VERSION 5.8 ;
BUSBITCHARS "[]" ;
DIVIDERCHAR "/" ;
UNITS
    DATABASE MICRONS 1000 ;
END UNITS

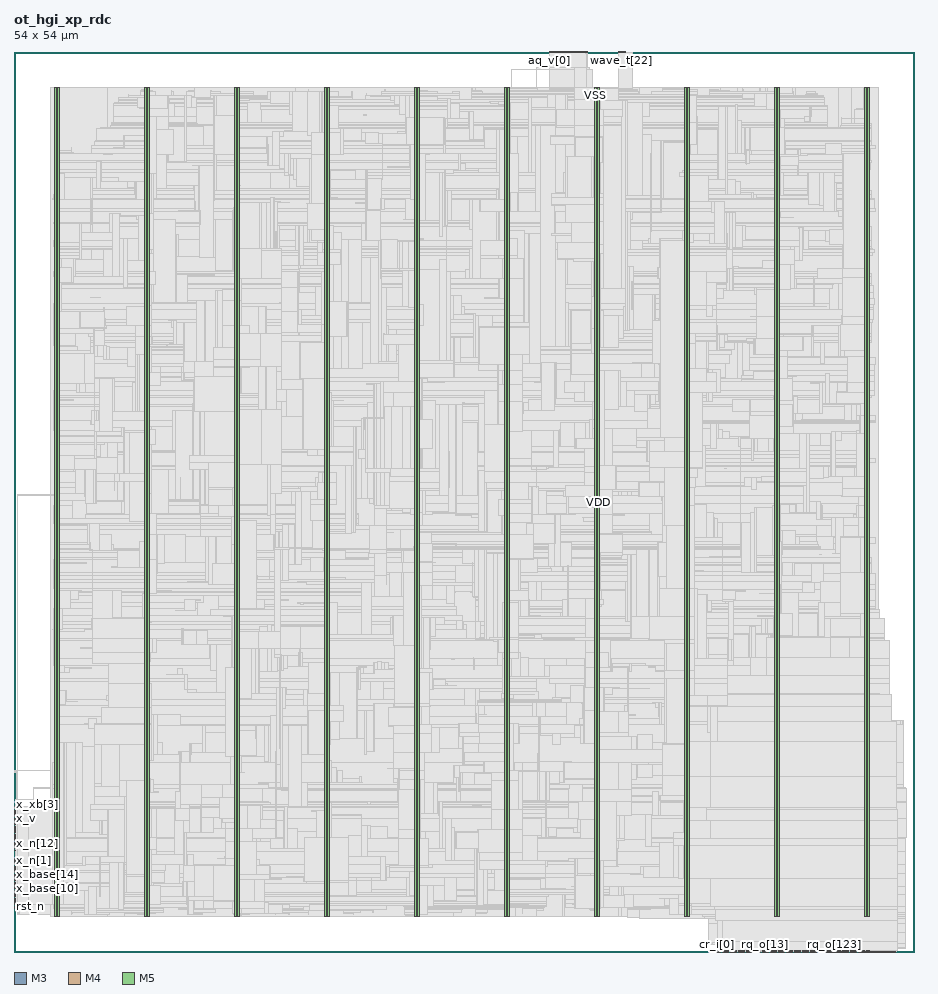
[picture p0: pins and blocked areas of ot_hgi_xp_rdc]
MACRO ot_hgi_xp_rdc
  FOREIGN ot_hgi_xp_rdc 0 0 ;
  CLASS BLOCK ;
  SIZE 54 BY 54 ;
  PIN aq_v[0]
    DIRECTION OUTPUT ;
    USE SIGNAL ;
    PORT
      LAYER M3 ;
        RECT  32.148 53.963 32.166 54 ;
    END
  END aq_v[0]
  PIN aq_v[1]
    DIRECTION OUTPUT ;
    USE SIGNAL ;
    PORT
      LAYER M3 ;
        RECT  32.22 53.963 32.238 54 ;
    END
  END aq_v[1]
  PIN bd_v
    DIRECTION OUTPUT ;
    USE SIGNAL ;
    PORT
      LAYER M3 ;
        RECT  32.292 53.963 32.31 54 ;
    END
  END bd_v
  PIN bf_v
    DIRECTION OUTPUT ;
    USE SIGNAL ;
    PORT
      LAYER M3 ;
        RECT  32.364 53.963 32.382 54 ;
    END
  END bf_v
  PIN clk
    DIRECTION INPUT ;
    USE SIGNAL ;
    PORT
      LAYER M4 ;
        RECT  0 2.64 0.084 2.664 ;
    END
  END clk
  PIN cr_i[0]
    DIRECTION INPUT ;
    USE SIGNAL ;
    PORT
      LAYER M5 ;
        RECT  42.192 0 42.216 0.084 ;
    END
  END cr_i[0]
  PIN cr_i[1]
    DIRECTION INPUT ;
    USE SIGNAL ;
    PORT
      LAYER M5 ;
        RECT  42.288 0 42.312 0.084 ;
    END
  END cr_i[1]
  PIN cr_i[2]
    DIRECTION INPUT ;
    USE SIGNAL ;
    PORT
      LAYER M5 ;
        RECT  42.384 0 42.408 0.084 ;
    END
  END cr_i[2]
  PIN cr_i[3]
    DIRECTION INPUT ;
    USE SIGNAL ;
    PORT
      LAYER M5 ;
        RECT  42.48 0 42.504 0.084 ;
    END
  END cr_i[3]
  PIN cr_i[4]
    DIRECTION INPUT ;
    USE SIGNAL ;
    PORT
      LAYER M5 ;
        RECT  42.576 0 42.6 0.084 ;
    END
  END cr_i[4]
  PIN cr_i[5]
    DIRECTION INPUT ;
    USE SIGNAL ;
    PORT
      LAYER M5 ;
        RECT  42.672 0 42.696 0.084 ;
    END
  END cr_i[5]
  PIN cr_i[6]
    DIRECTION INPUT ;
    USE SIGNAL ;
    PORT
      LAYER M5 ;
        RECT  42.768 0 42.792 0.084 ;
    END
  END cr_i[6]
  PIN cr_i[7]
    DIRECTION INPUT ;
    USE SIGNAL ;
    PORT
      LAYER M5 ;
        RECT  42.864 0 42.888 0.084 ;
    END
  END cr_i[7]
  PIN fault_i[0]
    DIRECTION INPUT ;
    USE SIGNAL ;
    PORT
      LAYER M3 ;
        RECT  32.436 53.963 32.454 54 ;
    END
  END fault_i[0]
  PIN fault_i[1]
    DIRECTION INPUT ;
    USE SIGNAL ;
    PORT
      LAYER M3 ;
        RECT  32.508 53.963 32.526 54 ;
    END
  END fault_i[1]
  PIN fault_i[2]
    DIRECTION INPUT ;
    USE SIGNAL ;
    PORT
      LAYER M3 ;
        RECT  32.58 53.963 32.598 54 ;
    END
  END fault_i[2]
  PIN fault_i[3]
    DIRECTION INPUT ;
    USE SIGNAL ;
    PORT
      LAYER M3 ;
        RECT  32.652 53.963 32.67 54 ;
    END
  END fault_i[3]
  PIN fault_i[4]
    DIRECTION INPUT ;
    USE SIGNAL ;
    PORT
      LAYER M3 ;
        RECT  32.724 53.963 32.742 54 ;
    END
  END fault_i[4]
  PIN fault_i[5]
    DIRECTION INPUT ;
    USE SIGNAL ;
    PORT
      LAYER M3 ;
        RECT  32.796 53.963 32.814 54 ;
    END
  END fault_i[5]
  PIN fault_i[6]
    DIRECTION INPUT ;
    USE SIGNAL ;
    PORT
      LAYER M3 ;
        RECT  32.868 53.963 32.886 54 ;
    END
  END fault_i[6]
  PIN fault_i[7]
    DIRECTION INPUT ;
    USE SIGNAL ;
    PORT
      LAYER M3 ;
        RECT  32.94 53.963 32.958 54 ;
    END
  END fault_i[7]
  PIN fault_i[8]
    DIRECTION INPUT ;
    USE SIGNAL ;
    PORT
      LAYER M3 ;
        RECT  33.012 53.963 33.03 54 ;
    END
  END fault_i[8]
  PIN lpop_o[0]
    DIRECTION OUTPUT ;
    USE SIGNAL ;
    PORT
      LAYER M5 ;
        RECT  42.96 0 42.984 0.084 ;
    END
  END lpop_o[0]
  PIN lpop_o[1]
    DIRECTION OUTPUT ;
    USE SIGNAL ;
    PORT
      LAYER M5 ;
        RECT  43.056 0 43.08 0.084 ;
    END
  END lpop_o[1]
  PIN lpop_o[2]
    DIRECTION OUTPUT ;
    USE SIGNAL ;
    PORT
      LAYER M5 ;
        RECT  43.152 0 43.176 0.084 ;
    END
  END lpop_o[2]
  PIN lpop_o[3]
    DIRECTION OUTPUT ;
    USE SIGNAL ;
    PORT
      LAYER M5 ;
        RECT  43.248 0 43.272 0.084 ;
    END
  END lpop_o[3]
  PIN lpop_o[4]
    DIRECTION OUTPUT ;
    USE SIGNAL ;
    PORT
      LAYER M5 ;
        RECT  43.344 0 43.368 0.084 ;
    END
  END lpop_o[4]
  PIN lpop_o[5]
    DIRECTION OUTPUT ;
    USE SIGNAL ;
    PORT
      LAYER M5 ;
        RECT  43.44 0 43.464 0.084 ;
    END
  END lpop_o[5]
  PIN lpop_o[6]
    DIRECTION OUTPUT ;
    USE SIGNAL ;
    PORT
      LAYER M5 ;
        RECT  43.536 0 43.56 0.084 ;
    END
  END lpop_o[6]
  PIN lpop_o[7]
    DIRECTION OUTPUT ;
    USE SIGNAL ;
    PORT
      LAYER M5 ;
        RECT  43.632 0 43.656 0.084 ;
    END
  END lpop_o[7]
  PIN pop_o
    DIRECTION OUTPUT ;
    USE SIGNAL ;
    PORT
      LAYER M5 ;
        RECT  43.728 0 43.752 0.084 ;
    END
  END pop_o
  PIN rq_o[0]
    DIRECTION OUTPUT ;
    USE SIGNAL ;
    PORT
      LAYER M5 ;
        RECT  43.824 0 43.848 0.084 ;
    END
  END rq_o[0]
  PIN rq_o[100]
    DIRECTION OUTPUT ;
    USE SIGNAL ;
    PORT
      LAYER M3 ;
        RECT  52.164 0 52.182 0.037 ;
    END
  END rq_o[100]
  PIN rq_o[101]
    DIRECTION OUTPUT ;
    USE SIGNAL ;
    PORT
      LAYER M3 ;
        RECT  52.236 0 52.254 0.037 ;
    END
  END rq_o[101]
  PIN rq_o[102]
    DIRECTION OUTPUT ;
    USE SIGNAL ;
    PORT
      LAYER M3 ;
        RECT  52.308 0 52.326 0.037 ;
    END
  END rq_o[102]
  PIN rq_o[103]
    DIRECTION OUTPUT ;
    USE SIGNAL ;
    PORT
      LAYER M3 ;
        RECT  52.38 0 52.398 0.037 ;
    END
  END rq_o[103]
  PIN rq_o[104]
    DIRECTION OUTPUT ;
    USE SIGNAL ;
    PORT
      LAYER M3 ;
        RECT  52.452 0 52.47 0.037 ;
    END
  END rq_o[104]
  PIN rq_o[105]
    DIRECTION OUTPUT ;
    USE SIGNAL ;
    PORT
      LAYER M3 ;
        RECT  52.524 0 52.542 0.037 ;
    END
  END rq_o[105]
  PIN rq_o[106]
    DIRECTION OUTPUT ;
    USE SIGNAL ;
    PORT
      LAYER M3 ;
        RECT  52.596 0 52.614 0.037 ;
    END
  END rq_o[106]
  PIN rq_o[107]
    DIRECTION OUTPUT ;
    USE SIGNAL ;
    PORT
      LAYER M3 ;
        RECT  52.668 0 52.686 0.037 ;
    END
  END rq_o[107]
  PIN rq_o[108]
    DIRECTION OUTPUT ;
    USE SIGNAL ;
    PORT
      LAYER M3 ;
        RECT  52.74 0 52.758 0.037 ;
    END
  END rq_o[108]
  PIN rq_o[109]
    DIRECTION OUTPUT ;
    USE SIGNAL ;
    PORT
      LAYER M3 ;
        RECT  52.812 0 52.83 0.037 ;
    END
  END rq_o[109]
  PIN rq_o[10]
    DIRECTION OUTPUT ;
    USE SIGNAL ;
    PORT
      LAYER M5 ;
        RECT  44.784 0 44.808 0.084 ;
    END
  END rq_o[10]
  PIN rq_o[110]
    DIRECTION OUTPUT ;
    USE SIGNAL ;
    PORT
      LAYER M3 ;
        RECT  52.884 0 52.902 0.037 ;
    END
  END rq_o[110]
  PIN rq_o[111]
    DIRECTION OUTPUT ;
    USE SIGNAL ;
    PORT
      LAYER M3 ;
        RECT  48.348 0 48.366 0.037 ;
    END
  END rq_o[111]
  PIN rq_o[112]
    DIRECTION OUTPUT ;
    USE SIGNAL ;
    PORT
      LAYER M3 ;
        RECT  48.42 0 48.438 0.037 ;
    END
  END rq_o[112]
  PIN rq_o[113]
    DIRECTION OUTPUT ;
    USE SIGNAL ;
    PORT
      LAYER M3 ;
        RECT  48.492 0 48.51 0.037 ;
    END
  END rq_o[113]
  PIN rq_o[114]
    DIRECTION OUTPUT ;
    USE SIGNAL ;
    PORT
      LAYER M3 ;
        RECT  48.564 0 48.582 0.037 ;
    END
  END rq_o[114]
  PIN rq_o[115]
    DIRECTION OUTPUT ;
    USE SIGNAL ;
    PORT
      LAYER M3 ;
        RECT  48.636 0 48.654 0.037 ;
    END
  END rq_o[115]
  PIN rq_o[116]
    DIRECTION OUTPUT ;
    USE SIGNAL ;
    PORT
      LAYER M3 ;
        RECT  48.708 0 48.726 0.037 ;
    END
  END rq_o[116]
  PIN rq_o[117]
    DIRECTION OUTPUT ;
    USE SIGNAL ;
    PORT
      LAYER M3 ;
        RECT  48.78 0 48.798 0.037 ;
    END
  END rq_o[117]
  PIN rq_o[118]
    DIRECTION OUTPUT ;
    USE SIGNAL ;
    PORT
      LAYER M3 ;
        RECT  48.852 0 48.87 0.037 ;
    END
  END rq_o[118]
  PIN rq_o[119]
    DIRECTION OUTPUT ;
    USE SIGNAL ;
    PORT
      LAYER M3 ;
        RECT  48.924 0 48.942 0.037 ;
    END
  END rq_o[119]
  PIN rq_o[11]
    DIRECTION OUTPUT ;
    USE SIGNAL ;
    PORT
      LAYER M5 ;
        RECT  44.88 0 44.904 0.084 ;
    END
  END rq_o[11]
  PIN rq_o[120]
    DIRECTION OUTPUT ;
    USE SIGNAL ;
    PORT
      LAYER M3 ;
        RECT  48.996 0 49.014 0.037 ;
    END
  END rq_o[120]
  PIN rq_o[121]
    DIRECTION OUTPUT ;
    USE SIGNAL ;
    PORT
      LAYER M3 ;
        RECT  49.068 0 49.086 0.037 ;
    END
  END rq_o[121]
  PIN rq_o[122]
    DIRECTION OUTPUT ;
    USE SIGNAL ;
    PORT
      LAYER M3 ;
        RECT  49.14 0 49.158 0.037 ;
    END
  END rq_o[122]
  PIN rq_o[123]
    DIRECTION OUTPUT ;
    USE SIGNAL ;
    PORT
      LAYER M3 ;
        RECT  49.212 0 49.23 0.037 ;
    END
  END rq_o[123]
  PIN rq_o[124]
    DIRECTION OUTPUT ;
    USE SIGNAL ;
    PORT
      LAYER M3 ;
        RECT  49.284 0 49.302 0.037 ;
    END
  END rq_o[124]
  PIN rq_o[125]
    DIRECTION OUTPUT ;
    USE SIGNAL ;
    PORT
      LAYER M3 ;
        RECT  49.356 0 49.374 0.037 ;
    END
  END rq_o[125]
  PIN rq_o[126]
    DIRECTION OUTPUT ;
    USE SIGNAL ;
    PORT
      LAYER M3 ;
        RECT  49.428 0 49.446 0.037 ;
    END
  END rq_o[126]
  PIN rq_o[127]
    DIRECTION OUTPUT ;
    USE SIGNAL ;
    PORT
      LAYER M3 ;
        RECT  49.5 0 49.518 0.037 ;
    END
  END rq_o[127]
  PIN rq_o[12]
    DIRECTION OUTPUT ;
    USE SIGNAL ;
    PORT
      LAYER M5 ;
        RECT  44.976 0 45 0.084 ;
    END
  END rq_o[12]
  PIN rq_o[13]
    DIRECTION OUTPUT ;
    USE SIGNAL ;
    PORT
      LAYER M5 ;
        RECT  45.072 0 45.096 0.084 ;
    END
  END rq_o[13]
  PIN rq_o[14]
    DIRECTION OUTPUT ;
    USE SIGNAL ;
    PORT
      LAYER M5 ;
        RECT  45.168 0 45.192 0.084 ;
    END
  END rq_o[14]
  PIN rq_o[15]
    DIRECTION OUTPUT ;
    USE SIGNAL ;
    PORT
      LAYER M5 ;
        RECT  45.264 0 45.288 0.084 ;
    END
  END rq_o[15]
  PIN rq_o[16]
    DIRECTION OUTPUT ;
    USE SIGNAL ;
    PORT
      LAYER M5 ;
        RECT  45.36 0 45.384 0.084 ;
    END
  END rq_o[16]
  PIN rq_o[17]
    DIRECTION OUTPUT ;
    USE SIGNAL ;
    PORT
      LAYER M5 ;
        RECT  45.456 0 45.48 0.084 ;
    END
  END rq_o[17]
  PIN rq_o[18]
    DIRECTION OUTPUT ;
    USE SIGNAL ;
    PORT
      LAYER M5 ;
        RECT  45.552 0 45.576 0.084 ;
    END
  END rq_o[18]
  PIN rq_o[19]
    DIRECTION OUTPUT ;
    USE SIGNAL ;
    PORT
      LAYER M5 ;
        RECT  45.648 0 45.672 0.084 ;
    END
  END rq_o[19]
  PIN rq_o[1]
    DIRECTION OUTPUT ;
    USE SIGNAL ;
    PORT
      LAYER M5 ;
        RECT  43.92 0 43.944 0.084 ;
    END
  END rq_o[1]
  PIN rq_o[20]
    DIRECTION OUTPUT ;
    USE SIGNAL ;
    PORT
      LAYER M5 ;
        RECT  45.744 0 45.768 0.084 ;
    END
  END rq_o[20]
  PIN rq_o[21]
    DIRECTION OUTPUT ;
    USE SIGNAL ;
    PORT
      LAYER M5 ;
        RECT  45.84 0 45.864 0.084 ;
    END
  END rq_o[21]
  PIN rq_o[22]
    DIRECTION OUTPUT ;
    USE SIGNAL ;
    PORT
      LAYER M5 ;
        RECT  45.936 0 45.96 0.084 ;
    END
  END rq_o[22]
  PIN rq_o[23]
    DIRECTION OUTPUT ;
    USE SIGNAL ;
    PORT
      LAYER M5 ;
        RECT  46.032 0 46.056 0.084 ;
    END
  END rq_o[23]
  PIN rq_o[24]
    DIRECTION OUTPUT ;
    USE SIGNAL ;
    PORT
      LAYER M5 ;
        RECT  46.128 0 46.152 0.084 ;
    END
  END rq_o[24]
  PIN rq_o[25]
    DIRECTION OUTPUT ;
    USE SIGNAL ;
    PORT
      LAYER M5 ;
        RECT  46.224 0 46.248 0.084 ;
    END
  END rq_o[25]
  PIN rq_o[26]
    DIRECTION OUTPUT ;
    USE SIGNAL ;
    PORT
      LAYER M5 ;
        RECT  46.32 0 46.344 0.084 ;
    END
  END rq_o[26]
  PIN rq_o[27]
    DIRECTION OUTPUT ;
    USE SIGNAL ;
    PORT
      LAYER M5 ;
        RECT  46.416 0 46.44 0.084 ;
    END
  END rq_o[27]
  PIN rq_o[28]
    DIRECTION OUTPUT ;
    USE SIGNAL ;
    PORT
      LAYER M5 ;
        RECT  46.512 0 46.536 0.084 ;
    END
  END rq_o[28]
  PIN rq_o[29]
    DIRECTION OUTPUT ;
    USE SIGNAL ;
    PORT
      LAYER M5 ;
        RECT  46.608 0 46.632 0.084 ;
    END
  END rq_o[29]
  PIN rq_o[2]
    DIRECTION OUTPUT ;
    USE SIGNAL ;
    PORT
      LAYER M5 ;
        RECT  44.016 0 44.04 0.084 ;
    END
  END rq_o[2]
  PIN rq_o[30]
    DIRECTION OUTPUT ;
    USE SIGNAL ;
    PORT
      LAYER M5 ;
        RECT  46.704 0 46.728 0.084 ;
    END
  END rq_o[30]
  PIN rq_o[31]
    DIRECTION OUTPUT ;
    USE SIGNAL ;
    PORT
      LAYER M5 ;
        RECT  46.8 0 46.824 0.084 ;
    END
  END rq_o[31]
  PIN rq_o[32]
    DIRECTION OUTPUT ;
    USE SIGNAL ;
    PORT
      LAYER M5 ;
        RECT  46.896 0 46.92 0.084 ;
    END
  END rq_o[32]
  PIN rq_o[33]
    DIRECTION OUTPUT ;
    USE SIGNAL ;
    PORT
      LAYER M5 ;
        RECT  46.992 0 47.016 0.084 ;
    END
  END rq_o[33]
  PIN rq_o[34]
    DIRECTION OUTPUT ;
    USE SIGNAL ;
    PORT
      LAYER M5 ;
        RECT  47.088 0 47.112 0.084 ;
    END
  END rq_o[34]
  PIN rq_o[35]
    DIRECTION OUTPUT ;
    USE SIGNAL ;
    PORT
      LAYER M5 ;
        RECT  47.184 0 47.208 0.084 ;
    END
  END rq_o[35]
  PIN rq_o[36]
    DIRECTION OUTPUT ;
    USE SIGNAL ;
    PORT
      LAYER M5 ;
        RECT  47.28 0 47.304 0.084 ;
    END
  END rq_o[36]
  PIN rq_o[37]
    DIRECTION OUTPUT ;
    USE SIGNAL ;
    PORT
      LAYER M5 ;
        RECT  47.376 0 47.4 0.084 ;
    END
  END rq_o[37]
  PIN rq_o[38]
    DIRECTION OUTPUT ;
    USE SIGNAL ;
    PORT
      LAYER M5 ;
        RECT  47.472 0 47.496 0.084 ;
    END
  END rq_o[38]
  PIN rq_o[39]
    DIRECTION OUTPUT ;
    USE SIGNAL ;
    PORT
      LAYER M5 ;
        RECT  47.568 0 47.592 0.084 ;
    END
  END rq_o[39]
  PIN rq_o[3]
    DIRECTION OUTPUT ;
    USE SIGNAL ;
    PORT
      LAYER M5 ;
        RECT  44.112 0 44.136 0.084 ;
    END
  END rq_o[3]
  PIN rq_o[40]
    DIRECTION OUTPUT ;
    USE SIGNAL ;
    PORT
      LAYER M5 ;
        RECT  47.664 0 47.688 0.084 ;
    END
  END rq_o[40]
  PIN rq_o[41]
    DIRECTION OUTPUT ;
    USE SIGNAL ;
    PORT
      LAYER M5 ;
        RECT  47.76 0 47.784 0.084 ;
    END
  END rq_o[41]
  PIN rq_o[42]
    DIRECTION OUTPUT ;
    USE SIGNAL ;
    PORT
      LAYER M5 ;
        RECT  47.856 0 47.88 0.084 ;
    END
  END rq_o[42]
  PIN rq_o[43]
    DIRECTION OUTPUT ;
    USE SIGNAL ;
    PORT
      LAYER M5 ;
        RECT  47.952 0 47.976 0.084 ;
    END
  END rq_o[43]
  PIN rq_o[44]
    DIRECTION OUTPUT ;
    USE SIGNAL ;
    PORT
      LAYER M5 ;
        RECT  48.048 0 48.072 0.084 ;
    END
  END rq_o[44]
  PIN rq_o[45]
    DIRECTION OUTPUT ;
    USE SIGNAL ;
    PORT
      LAYER M5 ;
        RECT  48.144 0 48.168 0.084 ;
    END
  END rq_o[45]
  PIN rq_o[46]
    DIRECTION OUTPUT ;
    USE SIGNAL ;
    PORT
      LAYER M5 ;
        RECT  48.24 0 48.264 0.084 ;
    END
  END rq_o[46]
  PIN rq_o[47]
    DIRECTION OUTPUT ;
    USE SIGNAL ;
    PORT
      LAYER M5 ;
        RECT  48.336 0 48.36 0.084 ;
    END
  END rq_o[47]
  PIN rq_o[48]
    DIRECTION OUTPUT ;
    USE SIGNAL ;
    PORT
      LAYER M5 ;
        RECT  48.432 0 48.456 0.084 ;
    END
  END rq_o[48]
  PIN rq_o[49]
    DIRECTION OUTPUT ;
    USE SIGNAL ;
    PORT
      LAYER M5 ;
        RECT  48.528 0 48.552 0.084 ;
    END
  END rq_o[49]
  PIN rq_o[4]
    DIRECTION OUTPUT ;
    USE SIGNAL ;
    PORT
      LAYER M5 ;
        RECT  44.208 0 44.232 0.084 ;
    END
  END rq_o[4]
  PIN rq_o[50]
    DIRECTION OUTPUT ;
    USE SIGNAL ;
    PORT
      LAYER M5 ;
        RECT  48.624 0 48.648 0.084 ;
    END
  END rq_o[50]
  PIN rq_o[51]
    DIRECTION OUTPUT ;
    USE SIGNAL ;
    PORT
      LAYER M5 ;
        RECT  48.72 0 48.744 0.084 ;
    END
  END rq_o[51]
  PIN rq_o[52]
    DIRECTION OUTPUT ;
    USE SIGNAL ;
    PORT
      LAYER M5 ;
        RECT  48.816 0 48.84 0.084 ;
    END
  END rq_o[52]
  PIN rq_o[53]
    DIRECTION OUTPUT ;
    USE SIGNAL ;
    PORT
      LAYER M5 ;
        RECT  48.912 0 48.936 0.084 ;
    END
  END rq_o[53]
  PIN rq_o[54]
    DIRECTION OUTPUT ;
    USE SIGNAL ;
    PORT
      LAYER M5 ;
        RECT  49.008 0 49.032 0.084 ;
    END
  END rq_o[54]
  PIN rq_o[55]
    DIRECTION OUTPUT ;
    USE SIGNAL ;
    PORT
      LAYER M5 ;
        RECT  49.104 0 49.128 0.084 ;
    END
  END rq_o[55]
  PIN rq_o[56]
    DIRECTION OUTPUT ;
    USE SIGNAL ;
    PORT
      LAYER M5 ;
        RECT  49.2 0 49.224 0.084 ;
    END
  END rq_o[56]
  PIN rq_o[57]
    DIRECTION OUTPUT ;
    USE SIGNAL ;
    PORT
      LAYER M5 ;
        RECT  49.296 0 49.32 0.084 ;
    END
  END rq_o[57]
  PIN rq_o[58]
    DIRECTION OUTPUT ;
    USE SIGNAL ;
    PORT
      LAYER M5 ;
        RECT  49.392 0 49.416 0.084 ;
    END
  END rq_o[58]
  PIN rq_o[59]
    DIRECTION OUTPUT ;
    USE SIGNAL ;
    PORT
      LAYER M5 ;
        RECT  49.488 0 49.512 0.084 ;
    END
  END rq_o[59]
  PIN rq_o[5]
    DIRECTION OUTPUT ;
    USE SIGNAL ;
    PORT
      LAYER M5 ;
        RECT  44.304 0 44.328 0.084 ;
    END
  END rq_o[5]
  PIN rq_o[60]
    DIRECTION OUTPUT ;
    USE SIGNAL ;
    PORT
      LAYER M5 ;
        RECT  49.584 0 49.608 0.084 ;
    END
  END rq_o[60]
  PIN rq_o[61]
    DIRECTION OUTPUT ;
    USE SIGNAL ;
    PORT
      LAYER M5 ;
        RECT  49.68 0 49.704 0.084 ;
    END
  END rq_o[61]
  PIN rq_o[62]
    DIRECTION OUTPUT ;
    USE SIGNAL ;
    PORT
      LAYER M5 ;
        RECT  49.776 0 49.8 0.084 ;
    END
  END rq_o[62]
  PIN rq_o[63]
    DIRECTION OUTPUT ;
    USE SIGNAL ;
    PORT
      LAYER M5 ;
        RECT  49.872 0 49.896 0.084 ;
    END
  END rq_o[63]
  PIN rq_o[64]
    DIRECTION OUTPUT ;
    USE SIGNAL ;
    PORT
      LAYER M5 ;
        RECT  49.968 0 49.992 0.084 ;
    END
  END rq_o[64]
  PIN rq_o[65]
    DIRECTION OUTPUT ;
    USE SIGNAL ;
    PORT
      LAYER M5 ;
        RECT  50.064 0 50.088 0.084 ;
    END
  END rq_o[65]
  PIN rq_o[66]
    DIRECTION OUTPUT ;
    USE SIGNAL ;
    PORT
      LAYER M5 ;
        RECT  50.16 0 50.184 0.084 ;
    END
  END rq_o[66]
  PIN rq_o[67]
    DIRECTION OUTPUT ;
    USE SIGNAL ;
    PORT
      LAYER M5 ;
        RECT  50.256 0 50.28 0.084 ;
    END
  END rq_o[67]
  PIN rq_o[68]
    DIRECTION OUTPUT ;
    USE SIGNAL ;
    PORT
      LAYER M5 ;
        RECT  50.352 0 50.376 0.084 ;
    END
  END rq_o[68]
  PIN rq_o[69]
    DIRECTION OUTPUT ;
    USE SIGNAL ;
    PORT
      LAYER M5 ;
        RECT  50.448 0 50.472 0.084 ;
    END
  END rq_o[69]
  PIN rq_o[6]
    DIRECTION OUTPUT ;
    USE SIGNAL ;
    PORT
      LAYER M5 ;
        RECT  44.4 0 44.424 0.084 ;
    END
  END rq_o[6]
  PIN rq_o[70]
    DIRECTION OUTPUT ;
    USE SIGNAL ;
    PORT
      LAYER M5 ;
        RECT  50.544 0 50.568 0.084 ;
    END
  END rq_o[70]
  PIN rq_o[71]
    DIRECTION OUTPUT ;
    USE SIGNAL ;
    PORT
      LAYER M5 ;
        RECT  50.64 0 50.664 0.084 ;
    END
  END rq_o[71]
  PIN rq_o[72]
    DIRECTION OUTPUT ;
    USE SIGNAL ;
    PORT
      LAYER M5 ;
        RECT  50.736 0 50.76 0.084 ;
    END
  END rq_o[72]
  PIN rq_o[73]
    DIRECTION OUTPUT ;
    USE SIGNAL ;
    PORT
      LAYER M5 ;
        RECT  50.832 0 50.856 0.084 ;
    END
  END rq_o[73]
  PIN rq_o[74]
    DIRECTION OUTPUT ;
    USE SIGNAL ;
    PORT
      LAYER M5 ;
        RECT  50.928 0 50.952 0.084 ;
    END
  END rq_o[74]
  PIN rq_o[75]
    DIRECTION OUTPUT ;
    USE SIGNAL ;
    PORT
      LAYER M5 ;
        RECT  51.024 0 51.048 0.084 ;
    END
  END rq_o[75]
  PIN rq_o[76]
    DIRECTION OUTPUT ;
    USE SIGNAL ;
    PORT
      LAYER M5 ;
        RECT  51.12 0 51.144 0.084 ;
    END
  END rq_o[76]
  PIN rq_o[77]
    DIRECTION OUTPUT ;
    USE SIGNAL ;
    PORT
      LAYER M5 ;
        RECT  51.216 0 51.24 0.084 ;
    END
  END rq_o[77]
  PIN rq_o[78]
    DIRECTION OUTPUT ;
    USE SIGNAL ;
    PORT
      LAYER M5 ;
        RECT  51.312 0 51.336 0.084 ;
    END
  END rq_o[78]
  PIN rq_o[79]
    DIRECTION OUTPUT ;
    USE SIGNAL ;
    PORT
      LAYER M3 ;
        RECT  50.652 0 50.67 0.037 ;
    END
  END rq_o[79]
  PIN rq_o[7]
    DIRECTION OUTPUT ;
    USE SIGNAL ;
    PORT
      LAYER M5 ;
        RECT  44.496 0 44.52 0.084 ;
    END
  END rq_o[7]
  PIN rq_o[80]
    DIRECTION OUTPUT ;
    USE SIGNAL ;
    PORT
      LAYER M3 ;
        RECT  50.724 0 50.742 0.037 ;
    END
  END rq_o[80]
  PIN rq_o[81]
    DIRECTION OUTPUT ;
    USE SIGNAL ;
    PORT
      LAYER M3 ;
        RECT  50.796 0 50.814 0.037 ;
    END
  END rq_o[81]
  PIN rq_o[82]
    DIRECTION OUTPUT ;
    USE SIGNAL ;
    PORT
      LAYER M3 ;
        RECT  50.868 0 50.886 0.037 ;
    END
  END rq_o[82]
  PIN rq_o[83]
    DIRECTION OUTPUT ;
    USE SIGNAL ;
    PORT
      LAYER M3 ;
        RECT  50.94 0 50.958 0.037 ;
    END
  END rq_o[83]
  PIN rq_o[84]
    DIRECTION OUTPUT ;
    USE SIGNAL ;
    PORT
      LAYER M3 ;
        RECT  51.012 0 51.03 0.037 ;
    END
  END rq_o[84]
  PIN rq_o[85]
    DIRECTION OUTPUT ;
    USE SIGNAL ;
    PORT
      LAYER M3 ;
        RECT  51.084 0 51.102 0.037 ;
    END
  END rq_o[85]
  PIN rq_o[86]
    DIRECTION OUTPUT ;
    USE SIGNAL ;
    PORT
      LAYER M3 ;
        RECT  51.156 0 51.174 0.037 ;
    END
  END rq_o[86]
  PIN rq_o[87]
    DIRECTION OUTPUT ;
    USE SIGNAL ;
    PORT
      LAYER M3 ;
        RECT  51.228 0 51.246 0.037 ;
    END
  END rq_o[87]
  PIN rq_o[88]
    DIRECTION OUTPUT ;
    USE SIGNAL ;
    PORT
      LAYER M3 ;
        RECT  51.3 0 51.318 0.037 ;
    END
  END rq_o[88]
  PIN rq_o[89]
    DIRECTION OUTPUT ;
    USE SIGNAL ;
    PORT
      LAYER M3 ;
        RECT  51.372 0 51.39 0.037 ;
    END
  END rq_o[89]
  PIN rq_o[8]
    DIRECTION OUTPUT ;
    USE SIGNAL ;
    PORT
      LAYER M5 ;
        RECT  44.592 0 44.616 0.084 ;
    END
  END rq_o[8]
  PIN rq_o[90]
    DIRECTION OUTPUT ;
    USE SIGNAL ;
    PORT
      LAYER M3 ;
        RECT  51.444 0 51.462 0.037 ;
    END
  END rq_o[90]
  PIN rq_o[91]
    DIRECTION OUTPUT ;
    USE SIGNAL ;
    PORT
      LAYER M3 ;
        RECT  51.516 0 51.534 0.037 ;
    END
  END rq_o[91]
  PIN rq_o[92]
    DIRECTION OUTPUT ;
    USE SIGNAL ;
    PORT
      LAYER M3 ;
        RECT  51.588 0 51.606 0.037 ;
    END
  END rq_o[92]
  PIN rq_o[93]
    DIRECTION OUTPUT ;
    USE SIGNAL ;
    PORT
      LAYER M3 ;
        RECT  51.66 0 51.678 0.037 ;
    END
  END rq_o[93]
  PIN rq_o[94]
    DIRECTION OUTPUT ;
    USE SIGNAL ;
    PORT
      LAYER M3 ;
        RECT  51.732 0 51.75 0.037 ;
    END
  END rq_o[94]
  PIN rq_o[95]
    DIRECTION OUTPUT ;
    USE SIGNAL ;
    PORT
      LAYER M3 ;
        RECT  51.804 0 51.822 0.037 ;
    END
  END rq_o[95]
  PIN rq_o[96]
    DIRECTION OUTPUT ;
    USE SIGNAL ;
    PORT
      LAYER M3 ;
        RECT  51.876 0 51.894 0.037 ;
    END
  END rq_o[96]
  PIN rq_o[97]
    DIRECTION OUTPUT ;
    USE SIGNAL ;
    PORT
      LAYER M3 ;
        RECT  51.948 0 51.966 0.037 ;
    END
  END rq_o[97]
  PIN rq_o[98]
    DIRECTION OUTPUT ;
    USE SIGNAL ;
    PORT
      LAYER M3 ;
        RECT  52.02 0 52.038 0.037 ;
    END
  END rq_o[98]
  PIN rq_o[99]
    DIRECTION OUTPUT ;
    USE SIGNAL ;
    PORT
      LAYER M3 ;
        RECT  52.092 0 52.11 0.037 ;
    END
  END rq_o[99]
  PIN rq_o[9]
    DIRECTION OUTPUT ;
    USE SIGNAL ;
    PORT
      LAYER M5 ;
        RECT  44.688 0 44.712 0.084 ;
    END
  END rq_o[9]
  PIN rst_n
    DIRECTION INPUT ;
    USE SIGNAL ;
    PORT
      LAYER M4 ;
        RECT  0 2.736 0.084 2.76 ;
    END
  END rst_n
  PIN rsv_i[0]
    DIRECTION INPUT ;
    USE SIGNAL ;
    PORT
      LAYER M3 ;
        RECT  49.572 0 49.59 0.037 ;
    END
  END rsv_i[0]
  PIN rsv_i[1]
    DIRECTION INPUT ;
    USE SIGNAL ;
    PORT
      LAYER M3 ;
        RECT  49.644 0 49.662 0.037 ;
    END
  END rsv_i[1]
  PIN rsv_i[2]
    DIRECTION INPUT ;
    USE SIGNAL ;
    PORT
      LAYER M3 ;
        RECT  49.716 0 49.734 0.037 ;
    END
  END rsv_i[2]
  PIN rsv_i[3]
    DIRECTION INPUT ;
    USE SIGNAL ;
    PORT
      LAYER M3 ;
        RECT  49.788 0 49.806 0.037 ;
    END
  END rsv_i[3]
  PIN rsv_i[4]
    DIRECTION INPUT ;
    USE SIGNAL ;
    PORT
      LAYER M3 ;
        RECT  49.86 0 49.878 0.037 ;
    END
  END rsv_i[4]
  PIN rsv_i[5]
    DIRECTION INPUT ;
    USE SIGNAL ;
    PORT
      LAYER M3 ;
        RECT  49.932 0 49.95 0.037 ;
    END
  END rsv_i[5]
  PIN rsv_i[6]
    DIRECTION INPUT ;
    USE SIGNAL ;
    PORT
      LAYER M3 ;
        RECT  50.004 0 50.022 0.037 ;
    END
  END rsv_i[6]
  PIN rsv_i[7]
    DIRECTION INPUT ;
    USE SIGNAL ;
    PORT
      LAYER M3 ;
        RECT  50.076 0 50.094 0.037 ;
    END
  END rsv_i[7]
  PIN wave_t[0]
    DIRECTION OUTPUT ;
    USE SIGNAL ;
    PORT
      LAYER M3 ;
        RECT  33.084 53.963 33.102 54 ;
    END
  END wave_t[0]
  PIN wave_t[10]
    DIRECTION OUTPUT ;
    USE SIGNAL ;
    PORT
      LAYER M3 ;
        RECT  33.804 53.963 33.822 54 ;
    END
  END wave_t[10]
  PIN wave_t[11]
    DIRECTION OUTPUT ;
    USE SIGNAL ;
    PORT
      LAYER M3 ;
        RECT  33.876 53.963 33.894 54 ;
    END
  END wave_t[11]
  PIN wave_t[12]
    DIRECTION OUTPUT ;
    USE SIGNAL ;
    PORT
      LAYER M3 ;
        RECT  33.948 53.963 33.966 54 ;
    END
  END wave_t[12]
  PIN wave_t[13]
    DIRECTION OUTPUT ;
    USE SIGNAL ;
    PORT
      LAYER M3 ;
        RECT  34.02 53.963 34.038 54 ;
    END
  END wave_t[13]
  PIN wave_t[14]
    DIRECTION OUTPUT ;
    USE SIGNAL ;
    PORT
      LAYER M3 ;
        RECT  34.092 53.963 34.11 54 ;
    END
  END wave_t[14]
  PIN wave_t[15]
    DIRECTION OUTPUT ;
    USE SIGNAL ;
    PORT
      LAYER M3 ;
        RECT  34.164 53.963 34.182 54 ;
    END
  END wave_t[15]
  PIN wave_t[16]
    DIRECTION OUTPUT ;
    USE SIGNAL ;
    PORT
      LAYER M3 ;
        RECT  34.236 53.963 34.254 54 ;
    END
  END wave_t[16]
  PIN wave_t[17]
    DIRECTION OUTPUT ;
    USE SIGNAL ;
    PORT
      LAYER M3 ;
        RECT  34.308 53.963 34.326 54 ;
    END
  END wave_t[17]
  PIN wave_t[18]
    DIRECTION OUTPUT ;
    USE SIGNAL ;
    PORT
      LAYER M3 ;
        RECT  34.38 53.963 34.398 54 ;
    END
  END wave_t[18]
  PIN wave_t[19]
    DIRECTION OUTPUT ;
    USE SIGNAL ;
    PORT
      LAYER M3 ;
        RECT  36.252 53.963 36.27 54 ;
    END
  END wave_t[19]
  PIN wave_t[1]
    DIRECTION OUTPUT ;
    USE SIGNAL ;
    PORT
      LAYER M3 ;
        RECT  33.156 53.963 33.174 54 ;
    END
  END wave_t[1]
  PIN wave_t[20]
    DIRECTION OUTPUT ;
    USE SIGNAL ;
    PORT
      LAYER M3 ;
        RECT  36.324 53.963 36.342 54 ;
    END
  END wave_t[20]
  PIN wave_t[21]
    DIRECTION OUTPUT ;
    USE SIGNAL ;
    PORT
      LAYER M3 ;
        RECT  36.396 53.963 36.414 54 ;
    END
  END wave_t[21]
  PIN wave_t[22]
    DIRECTION OUTPUT ;
    USE SIGNAL ;
    PORT
      LAYER M3 ;
        RECT  36.468 53.963 36.486 54 ;
    END
  END wave_t[22]
  PIN wave_t[23]
    DIRECTION OUTPUT ;
    USE SIGNAL ;
    PORT
      LAYER M3 ;
        RECT  36.54 53.963 36.558 54 ;
    END
  END wave_t[23]
  PIN wave_t[24]
    DIRECTION OUTPUT ;
    USE SIGNAL ;
    PORT
      LAYER M3 ;
        RECT  36.612 53.963 36.63 54 ;
    END
  END wave_t[24]
  PIN wave_t[2]
    DIRECTION OUTPUT ;
    USE SIGNAL ;
    PORT
      LAYER M3 ;
        RECT  33.228 53.963 33.246 54 ;
    END
  END wave_t[2]
  PIN wave_t[3]
    DIRECTION OUTPUT ;
    USE SIGNAL ;
    PORT
      LAYER M3 ;
        RECT  33.3 53.963 33.318 54 ;
    END
  END wave_t[3]
  PIN wave_t[4]
    DIRECTION OUTPUT ;
    USE SIGNAL ;
    PORT
      LAYER M3 ;
        RECT  33.372 53.963 33.39 54 ;
    END
  END wave_t[4]
  PIN wave_t[5]
    DIRECTION OUTPUT ;
    USE SIGNAL ;
    PORT
      LAYER M3 ;
        RECT  33.444 53.963 33.462 54 ;
    END
  END wave_t[5]
  PIN wave_t[6]
    DIRECTION OUTPUT ;
    USE SIGNAL ;
    PORT
      LAYER M3 ;
        RECT  33.516 53.963 33.534 54 ;
    END
  END wave_t[6]
  PIN wave_t[7]
    DIRECTION OUTPUT ;
    USE SIGNAL ;
    PORT
      LAYER M3 ;
        RECT  33.588 53.963 33.606 54 ;
    END
  END wave_t[7]
  PIN wave_t[8]
    DIRECTION OUTPUT ;
    USE SIGNAL ;
    PORT
      LAYER M3 ;
        RECT  33.66 53.963 33.678 54 ;
    END
  END wave_t[8]
  PIN wave_t[9]
    DIRECTION OUTPUT ;
    USE SIGNAL ;
    PORT
      LAYER M3 ;
        RECT  33.732 53.963 33.75 54 ;
    END
  END wave_t[9]
  PIN x_base[0]
    DIRECTION INPUT ;
    USE SIGNAL ;
    PORT
      LAYER M4 ;
        RECT  0 2.832 0.084 2.856 ;
    END
  END x_base[0]
  PIN x_base[10]
    DIRECTION INPUT ;
    USE SIGNAL ;
    PORT
      LAYER M4 ;
        RECT  0 3.792 0.084 3.816 ;
    END
  END x_base[10]
  PIN x_base[11]
    DIRECTION INPUT ;
    USE SIGNAL ;
    PORT
      LAYER M4 ;
        RECT  0 3.888 0.084 3.912 ;
    END
  END x_base[11]
  PIN x_base[12]
    DIRECTION INPUT ;
    USE SIGNAL ;
    PORT
      LAYER M4 ;
        RECT  0 3.984 0.084 4.008 ;
    END
  END x_base[12]
  PIN x_base[13]
    DIRECTION INPUT ;
    USE SIGNAL ;
    PORT
      LAYER M4 ;
        RECT  0 4.08 0.084 4.104 ;
    END
  END x_base[13]
  PIN x_base[14]
    DIRECTION INPUT ;
    USE SIGNAL ;
    PORT
      LAYER M4 ;
        RECT  0 4.176 0.084 4.2 ;
    END
  END x_base[14]
  PIN x_base[15]
    DIRECTION INPUT ;
    USE SIGNAL ;
    PORT
      LAYER M4 ;
        RECT  0 4.272 0.084 4.296 ;
    END
  END x_base[15]
  PIN x_base[16]
    DIRECTION INPUT ;
    USE SIGNAL ;
    PORT
      LAYER M4 ;
        RECT  0 4.368 0.084 4.392 ;
    END
  END x_base[16]
  PIN x_base[17]
    DIRECTION INPUT ;
    USE SIGNAL ;
    PORT
      LAYER M4 ;
        RECT  0 4.464 0.084 4.488 ;
    END
  END x_base[17]
  PIN x_base[1]
    DIRECTION INPUT ;
    USE SIGNAL ;
    PORT
      LAYER M4 ;
        RECT  0 2.928 0.084 2.952 ;
    END
  END x_base[1]
  PIN x_base[2]
    DIRECTION INPUT ;
    USE SIGNAL ;
    PORT
      LAYER M4 ;
        RECT  0 3.024 0.084 3.048 ;
    END
  END x_base[2]
  PIN x_base[3]
    DIRECTION INPUT ;
    USE SIGNAL ;
    PORT
      LAYER M4 ;
        RECT  0 3.12 0.084 3.144 ;
    END
  END x_base[3]
  PIN x_base[4]
    DIRECTION INPUT ;
    USE SIGNAL ;
    PORT
      LAYER M4 ;
        RECT  0 3.216 0.084 3.24 ;
    END
  END x_base[4]
  PIN x_base[5]
    DIRECTION INPUT ;
    USE SIGNAL ;
    PORT
      LAYER M4 ;
        RECT  0 3.312 0.084 3.336 ;
    END
  END x_base[5]
  PIN x_base[6]
    DIRECTION INPUT ;
    USE SIGNAL ;
    PORT
      LAYER M4 ;
        RECT  0 3.408 0.084 3.432 ;
    END
  END x_base[6]
  PIN x_base[7]
    DIRECTION INPUT ;
    USE SIGNAL ;
    PORT
      LAYER M4 ;
        RECT  0 3.504 0.084 3.528 ;
    END
  END x_base[7]
  PIN x_base[8]
    DIRECTION INPUT ;
    USE SIGNAL ;
    PORT
      LAYER M4 ;
        RECT  0 3.6 0.084 3.624 ;
    END
  END x_base[8]
  PIN x_base[9]
    DIRECTION INPUT ;
    USE SIGNAL ;
    PORT
      LAYER M4 ;
        RECT  0 3.696 0.084 3.72 ;
    END
  END x_base[9]
  PIN x_done
    DIRECTION OUTPUT ;
    USE SIGNAL ;
    PORT
      LAYER M4 ;
        RECT  0 4.56 0.084 4.584 ;
    END
  END x_done
  PIN x_fault
    DIRECTION OUTPUT ;
    USE SIGNAL ;
    PORT
      LAYER M4 ;
        RECT  0 4.656 0.084 4.68 ;
    END
  END x_fault
  PIN x_fmt[0]
    DIRECTION INPUT ;
    USE SIGNAL ;
    PORT
      LAYER M4 ;
        RECT  0 4.752 0.084 4.776 ;
    END
  END x_fmt[0]
  PIN x_fmt[1]
    DIRECTION INPUT ;
    USE SIGNAL ;
    PORT
      LAYER M4 ;
        RECT  0 4.848 0.084 4.872 ;
    END
  END x_fmt[1]
  PIN x_n[0]
    DIRECTION INPUT ;
    USE SIGNAL ;
    PORT
      LAYER M4 ;
        RECT  0 4.944 0.084 4.968 ;
    END
  END x_n[0]
  PIN x_n[10]
    DIRECTION INPUT ;
    USE SIGNAL ;
    PORT
      LAYER M4 ;
        RECT  0 6.288 0.084 6.312 ;
    END
  END x_n[10]
  PIN x_n[11]
    DIRECTION INPUT ;
    USE SIGNAL ;
    PORT
      LAYER M4 ;
        RECT  0 6.384 0.084 6.408 ;
    END
  END x_n[11]
  PIN x_n[12]
    DIRECTION INPUT ;
    USE SIGNAL ;
    PORT
      LAYER M4 ;
        RECT  0 6.48 0.084 6.504 ;
    END
  END x_n[12]
  PIN x_n[13]
    DIRECTION INPUT ;
    USE SIGNAL ;
    PORT
      LAYER M4 ;
        RECT  0 6.576 0.084 6.6 ;
    END
  END x_n[13]
  PIN x_n[14]
    DIRECTION INPUT ;
    USE SIGNAL ;
    PORT
      LAYER M4 ;
        RECT  0 6.672 0.084 6.696 ;
    END
  END x_n[14]
  PIN x_n[15]
    DIRECTION INPUT ;
    USE SIGNAL ;
    PORT
      LAYER M4 ;
        RECT  0 6.768 0.084 6.792 ;
    END
  END x_n[15]
  PIN x_n[16]
    DIRECTION INPUT ;
    USE SIGNAL ;
    PORT
      LAYER M4 ;
        RECT  0 6.864 0.084 6.888 ;
    END
  END x_n[16]
  PIN x_n[17]
    DIRECTION INPUT ;
    USE SIGNAL ;
    PORT
      LAYER M4 ;
        RECT  0 6.96 0.084 6.984 ;
    END
  END x_n[17]
  PIN x_n[18]
    DIRECTION INPUT ;
    USE SIGNAL ;
    PORT
      LAYER M4 ;
        RECT  0 7.056 0.084 7.08 ;
    END
  END x_n[18]
  PIN x_n[19]
    DIRECTION INPUT ;
    USE SIGNAL ;
    PORT
      LAYER M4 ;
        RECT  0 7.152 0.084 7.176 ;
    END
  END x_n[19]
  PIN x_n[1]
    DIRECTION INPUT ;
    USE SIGNAL ;
    PORT
      LAYER M4 ;
        RECT  0 5.04 0.084 5.064 ;
    END
  END x_n[1]
  PIN x_n[20]
    DIRECTION INPUT ;
    USE SIGNAL ;
    PORT
      LAYER M4 ;
        RECT  0 7.248 0.084 7.272 ;
    END
  END x_n[20]
  PIN x_n[2]
    DIRECTION INPUT ;
    USE SIGNAL ;
    PORT
      LAYER M4 ;
        RECT  0 5.136 0.084 5.16 ;
    END
  END x_n[2]
  PIN x_n[3]
    DIRECTION INPUT ;
    USE SIGNAL ;
    PORT
      LAYER M4 ;
        RECT  0 5.232 0.084 5.256 ;
    END
  END x_n[3]
  PIN x_n[4]
    DIRECTION INPUT ;
    USE SIGNAL ;
    PORT
      LAYER M4 ;
        RECT  0 5.328 0.084 5.352 ;
    END
  END x_n[4]
  PIN x_n[5]
    DIRECTION INPUT ;
    USE SIGNAL ;
    PORT
      LAYER M4 ;
        RECT  0 5.424 0.084 5.448 ;
    END
  END x_n[5]
  PIN x_n[6]
    DIRECTION INPUT ;
    USE SIGNAL ;
    PORT
      LAYER M4 ;
        RECT  0 5.52 0.084 5.544 ;
    END
  END x_n[6]
  PIN x_n[7]
    DIRECTION INPUT ;
    USE SIGNAL ;
    PORT
      LAYER M4 ;
        RECT  0 5.616 0.084 5.64 ;
    END
  END x_n[7]
  PIN x_n[8]
    DIRECTION INPUT ;
    USE SIGNAL ;
    PORT
      LAYER M4 ;
        RECT  0 6.096 0.084 6.12 ;
    END
  END x_n[8]
  PIN x_n[9]
    DIRECTION INPUT ;
    USE SIGNAL ;
    PORT
      LAYER M4 ;
        RECT  0 6.192 0.084 6.216 ;
    END
  END x_n[9]
  PIN x_p[0]
    DIRECTION INPUT ;
    USE SIGNAL ;
    PORT
      LAYER M4 ;
        RECT  0 7.344 0.084 7.368 ;
    END
  END x_p[0]
  PIN x_p[1]
    DIRECTION INPUT ;
    USE SIGNAL ;
    PORT
      LAYER M4 ;
        RECT  0 7.44 0.084 7.464 ;
    END
  END x_p[1]
  PIN x_p[2]
    DIRECTION INPUT ;
    USE SIGNAL ;
    PORT
      LAYER M4 ;
        RECT  0 7.536 0.084 7.56 ;
    END
  END x_p[2]
  PIN x_p[3]
    DIRECTION INPUT ;
    USE SIGNAL ;
    PORT
      LAYER M4 ;
        RECT  0 7.632 0.084 7.656 ;
    END
  END x_p[3]
  PIN x_rdy
    DIRECTION OUTPUT ;
    USE SIGNAL ;
    PORT
      LAYER M4 ;
        RECT  0 7.728 0.084 7.752 ;
    END
  END x_rdy
  PIN x_space[0]
    DIRECTION INPUT ;
    USE SIGNAL ;
    PORT
      LAYER M4 ;
        RECT  0 7.824 0.084 7.848 ;
    END
  END x_space[0]
  PIN x_space[1]
    DIRECTION INPUT ;
    USE SIGNAL ;
    PORT
      LAYER M4 ;
        RECT  0 7.92 0.084 7.944 ;
    END
  END x_space[1]
  PIN x_v
    DIRECTION INPUT ;
    USE SIGNAL ;
    PORT
      LAYER M4 ;
        RECT  0 8.016 0.084 8.04 ;
    END
  END x_v
  PIN x_xb[0]
    DIRECTION INPUT ;
    USE SIGNAL ;
    PORT
      LAYER M4 ;
        RECT  0 8.112 0.084 8.136 ;
    END
  END x_xb[0]
  PIN x_xb[1]
    DIRECTION INPUT ;
    USE SIGNAL ;
    PORT
      LAYER M4 ;
        RECT  0 8.208 0.084 8.232 ;
    END
  END x_xb[1]
  PIN x_xb[2]
    DIRECTION INPUT ;
    USE SIGNAL ;
    PORT
      LAYER M4 ;
        RECT  0 8.304 0.084 8.328 ;
    END
  END x_xb[2]
  PIN x_xb[3]
    DIRECTION INPUT ;
    USE SIGNAL ;
    PORT
      LAYER M4 ;
        RECT  0 8.4 0.084 8.424 ;
    END
  END x_xb[3]
  PIN x_xb[4]
    DIRECTION INPUT ;
    USE SIGNAL ;
    PORT
      LAYER M4 ;
        RECT  0 8.496 0.084 8.52 ;
    END
  END x_xb[4]
  PIN x_xb[5]
    DIRECTION INPUT ;
    USE SIGNAL ;
    PORT
      LAYER M4 ;
        RECT  0 8.592 0.084 8.616 ;
    END
  END x_xb[5]
  PIN x_xb[6]
    DIRECTION INPUT ;
    USE SIGNAL ;
    PORT
      LAYER M4 ;
        RECT  0 8.688 0.084 8.712 ;
    END
  END x_xb[6]
  PIN xw_eop_i
    DIRECTION INPUT ;
    USE SIGNAL ;
    PORT
      LAYER M3 ;
        RECT  36.684 53.963 36.702 54 ;
    END
  END xw_eop_i
  PIN VDD
    DIRECTION INOUT ;
    USE POWER ;
    PORT
      LAYER M5 ;
        RECT  51.192 2.151 51.312 51.849 ;
        RECT  45.792 2.151 45.912 51.849 ;
        RECT  40.392 2.151 40.512 51.849 ;
        RECT  34.992 2.151 35.112 51.849 ;
        RECT  29.592 2.151 29.712 51.849 ;
        RECT  24.192 2.151 24.312 51.849 ;
        RECT  18.792 2.151 18.912 51.849 ;
        RECT  13.392 2.151 13.512 51.849 ;
        RECT  7.992 2.151 8.112 51.849 ;
        RECT  2.592 2.151 2.712 51.849 ;
    END
  END VDD
  PIN VSS
    DIRECTION INOUT ;
    USE GROUND ;
    PORT
      LAYER M5 ;
        RECT  51 2.137 51.12 51.863 ;
        RECT  45.6 2.137 45.72 51.863 ;
        RECT  40.2 2.137 40.32 51.863 ;
        RECT  34.8 2.137 34.92 51.863 ;
        RECT  29.4 2.137 29.52 51.863 ;
        RECT  24 2.137 24.12 51.863 ;
        RECT  18.6 2.137 18.72 51.863 ;
        RECT  13.2 2.137 13.32 51.863 ;
        RECT  7.8 2.137 7.92 51.863 ;
        RECT  2.4 2.137 2.52 51.863 ;
    END
  END VSS
  # OT_OBS_CLOSED layer=M5 d_um=1.536 added=251
  OBS
    LAYER RVTN ;
     RECT  2.16 2.16 51.84 2.295 ;
     RECT  2.16 2.565 51.84 2.835 ;
     RECT  2.16 3.105 51.84 3.375 ;
     RECT  2.16 3.645 51.84 3.915 ;
     RECT  2.16 4.185 51.84 4.455 ;
     RECT  2.16 4.725 51.84 4.995 ;
     RECT  2.16 5.265 51.84 5.535 ;
     RECT  2.16 5.805 51.84 6.075 ;
     RECT  2.16 6.345 51.84 6.615 ;
     RECT  2.16 6.885 51.84 7.155 ;
     RECT  2.16 7.425 51.84 7.695 ;
     RECT  2.16 7.965 51.84 8.235 ;
     RECT  2.16 8.505 51.84 8.775 ;
     RECT  2.16 9.045 51.84 9.315 ;
     RECT  2.16 9.585 51.84 9.855 ;
     RECT  2.16 10.125 51.84 10.395 ;
     RECT  2.16 10.665 51.84 10.935 ;
     RECT  2.16 11.205 51.84 11.475 ;
     RECT  2.16 11.745 51.84 12.015 ;
     RECT  2.16 12.285 51.84 12.555 ;
     RECT  2.16 12.825 51.84 13.095 ;
     RECT  2.16 13.365 51.84 13.635 ;
     RECT  2.16 13.905 51.84 14.175 ;
     RECT  2.16 14.445 51.84 14.715 ;
     RECT  2.16 14.985 51.84 15.255 ;
     RECT  2.16 15.525 51.84 15.795 ;
     RECT  2.16 16.065 51.84 16.335 ;
     RECT  2.16 16.605 51.84 16.875 ;
     RECT  2.16 17.145 51.84 17.415 ;
     RECT  2.16 17.685 51.84 17.955 ;
     RECT  2.16 18.225 51.84 18.495 ;
     RECT  2.16 18.765 51.84 19.035 ;
     RECT  2.16 19.305 51.84 19.575 ;
     RECT  2.16 19.845 51.84 20.115 ;
     RECT  2.16 20.385 51.84 20.655 ;
     RECT  2.16 20.925 51.84 21.195 ;
     RECT  2.16 21.465 51.84 21.735 ;
     RECT  2.16 22.005 51.84 22.275 ;
     RECT  2.16 22.545 51.84 22.815 ;
     RECT  2.16 23.085 51.84 23.355 ;
     RECT  2.16 23.625 51.84 23.895 ;
     RECT  2.16 24.165 51.84 24.435 ;
     RECT  2.16 24.705 51.84 24.975 ;
     RECT  2.16 25.245 51.84 25.515 ;
     RECT  2.16 25.785 51.84 26.055 ;
     RECT  2.16 26.325 51.84 26.595 ;
     RECT  2.16 26.865 51.84 27.135 ;
     RECT  2.16 27.405 51.84 27.675 ;
     RECT  2.16 27.945 51.84 28.215 ;
     RECT  2.16 28.485 51.84 28.755 ;
     RECT  2.16 29.025 51.84 29.295 ;
     RECT  2.16 29.565 51.84 29.835 ;
     RECT  2.16 30.105 51.84 30.375 ;
     RECT  2.16 30.645 51.84 30.915 ;
     RECT  2.16 31.185 51.84 31.455 ;
     RECT  2.16 31.725 51.84 31.995 ;
     RECT  2.16 32.265 51.84 32.535 ;
     RECT  2.16 32.805 51.84 33.075 ;
     RECT  2.16 33.345 51.84 33.615 ;
     RECT  2.16 33.885 51.84 34.155 ;
     RECT  2.16 34.425 51.84 34.695 ;
     RECT  2.16 34.965 51.84 35.235 ;
     RECT  2.16 35.505 51.84 35.775 ;
     RECT  2.16 36.045 51.84 36.315 ;
     RECT  2.16 36.585 51.84 36.855 ;
     RECT  2.16 37.125 51.84 37.395 ;
     RECT  2.16 37.665 51.84 37.935 ;
     RECT  2.16 38.205 51.84 38.475 ;
     RECT  2.16 38.745 51.84 39.015 ;
     RECT  2.16 39.285 51.84 39.555 ;
     RECT  2.16 39.825 51.84 40.095 ;
     RECT  2.16 40.365 51.84 40.635 ;
     RECT  2.16 40.905 51.84 41.175 ;
     RECT  2.16 41.445 51.84 41.715 ;
     RECT  2.16 41.985 51.84 42.255 ;
     RECT  2.16 42.525 51.84 42.795 ;
     RECT  2.16 43.065 51.84 43.335 ;
     RECT  2.16 43.605 51.84 43.875 ;
     RECT  2.16 44.145 51.84 44.415 ;
     RECT  2.16 44.685 51.84 44.955 ;
     RECT  2.16 45.225 51.84 45.495 ;
     RECT  2.16 45.765 51.84 46.035 ;
     RECT  2.16 46.305 51.84 46.575 ;
     RECT  2.16 46.845 51.84 47.115 ;
     RECT  2.16 47.385 51.84 47.655 ;
     RECT  2.16 47.925 51.84 48.195 ;
     RECT  2.16 48.465 51.84 48.735 ;
     RECT  2.16 49.005 51.84 49.275 ;
     RECT  2.16 49.545 51.84 49.815 ;
     RECT  2.16 50.085 51.84 50.355 ;
     RECT  2.16 50.625 51.84 50.895 ;
     RECT  2.16 51.165 51.84 51.435 ;
     RECT  2.16 51.705 51.84 51.84 ;
    LAYER RVTP ;
     RECT  2.16 2.295 51.84 2.565 ;
     RECT  2.16 2.835 51.84 3.105 ;
     RECT  2.16 3.375 51.84 3.645 ;
     RECT  2.16 3.915 51.84 4.185 ;
     RECT  2.16 4.455 51.84 4.725 ;
     RECT  2.16 4.995 51.84 5.265 ;
     RECT  2.16 5.535 51.84 5.805 ;
     RECT  2.16 6.075 51.84 6.345 ;
     RECT  2.16 6.615 51.84 6.885 ;
     RECT  2.16 7.155 51.84 7.425 ;
     RECT  2.16 7.695 51.84 7.965 ;
     RECT  2.16 8.235 51.84 8.505 ;
     RECT  2.16 8.775 51.84 9.045 ;
     RECT  2.16 9.315 51.84 9.585 ;
     RECT  2.16 9.855 51.84 10.125 ;
     RECT  2.16 10.395 51.84 10.665 ;
     RECT  2.16 10.935 51.84 11.205 ;
     RECT  2.16 11.475 51.84 11.745 ;
     RECT  2.16 12.015 51.84 12.285 ;
     RECT  2.16 12.555 51.84 12.825 ;
     RECT  2.16 13.095 51.84 13.365 ;
     RECT  2.16 13.635 51.84 13.905 ;
     RECT  2.16 14.175 51.84 14.445 ;
     RECT  2.16 14.715 51.84 14.985 ;
     RECT  2.16 15.255 51.84 15.525 ;
     RECT  2.16 15.795 51.84 16.065 ;
     RECT  2.16 16.335 51.84 16.605 ;
     RECT  2.16 16.875 51.84 17.145 ;
     RECT  2.16 17.415 51.84 17.685 ;
     RECT  2.16 17.955 51.84 18.225 ;
     RECT  2.16 18.495 51.84 18.765 ;
     RECT  2.16 19.035 51.84 19.305 ;
     RECT  2.16 19.575 51.84 19.845 ;
     RECT  2.16 20.115 51.84 20.385 ;
     RECT  2.16 20.655 51.84 20.925 ;
     RECT  2.16 21.195 51.84 21.465 ;
     RECT  2.16 21.735 51.84 22.005 ;
     RECT  2.16 22.275 51.84 22.545 ;
     RECT  2.16 22.815 51.84 23.085 ;
     RECT  2.16 23.355 51.84 23.625 ;
     RECT  2.16 23.895 51.84 24.165 ;
     RECT  2.16 24.435 51.84 24.705 ;
     RECT  2.16 24.975 51.84 25.245 ;
     RECT  2.16 25.515 51.84 25.785 ;
     RECT  2.16 26.055 51.84 26.325 ;
     RECT  2.16 26.595 51.84 26.865 ;
     RECT  2.16 27.135 51.84 27.405 ;
     RECT  2.16 27.675 51.84 27.945 ;
     RECT  2.16 28.215 51.84 28.485 ;
     RECT  2.16 28.755 51.84 29.025 ;
     RECT  2.16 29.295 51.84 29.565 ;
     RECT  2.16 29.835 51.84 30.105 ;
     RECT  2.16 30.375 51.84 30.645 ;
     RECT  2.16 30.915 51.84 31.185 ;
     RECT  2.16 31.455 51.84 31.725 ;
     RECT  2.16 31.995 51.84 32.265 ;
     RECT  2.16 32.535 51.84 32.805 ;
     RECT  2.16 33.075 51.84 33.345 ;
     RECT  2.16 33.615 51.84 33.885 ;
     RECT  2.16 34.155 51.84 34.425 ;
     RECT  2.16 34.695 51.84 34.965 ;
     RECT  2.16 35.235 51.84 35.505 ;
     RECT  2.16 35.775 51.84 36.045 ;
     RECT  2.16 36.315 51.84 36.585 ;
     RECT  2.16 36.855 51.84 37.125 ;
     RECT  2.16 37.395 51.84 37.665 ;
     RECT  2.16 37.935 51.84 38.205 ;
     RECT  2.16 38.475 51.84 38.745 ;
     RECT  2.16 39.015 51.84 39.285 ;
     RECT  2.16 39.555 51.84 39.825 ;
     RECT  2.16 40.095 51.84 40.365 ;
     RECT  2.16 40.635 51.84 40.905 ;
     RECT  2.16 41.175 51.84 41.445 ;
     RECT  2.16 41.715 51.84 41.985 ;
     RECT  2.16 42.255 51.84 42.525 ;
     RECT  2.16 42.795 51.84 43.065 ;
     RECT  2.16 43.335 51.84 43.605 ;
     RECT  2.16 43.875 51.84 44.145 ;
     RECT  2.16 44.415 51.84 44.685 ;
     RECT  2.16 44.955 51.84 45.225 ;
     RECT  2.16 45.495 51.84 45.765 ;
     RECT  2.16 46.035 51.84 46.305 ;
     RECT  2.16 46.575 51.84 46.845 ;
     RECT  2.16 47.115 51.84 47.385 ;
     RECT  2.16 47.655 51.84 47.925 ;
     RECT  2.16 48.195 51.84 48.465 ;
     RECT  2.16 48.735 51.84 49.005 ;
     RECT  2.16 49.275 51.84 49.545 ;
     RECT  2.16 49.815 51.84 50.085 ;
     RECT  2.16 50.355 51.84 50.625 ;
     RECT  2.16 50.895 51.84 51.165 ;
     RECT  2.16 51.435 51.84 51.705 ;
    LAYER M1 ;
     RECT  2.16 2.151 51.84 51.849 ;
    LAYER M2 ;
     RECT  0.103 2.502 0.139 2.52 ;
     RECT  0.103 3.96 0.139 5.022 ;
     RECT  0.031 10.791 0.167 10.89 ;
     RECT  0.139 2.502 0.211 5.022 ;
     RECT  0.103 6.822 0.247 6.912 ;
     RECT  0.175 7.668 0.247 7.686 ;
     RECT  0.211 2.232 0.319 5.022 ;
     RECT  0.247 6.822 0.419 7.686 ;
     RECT  0.103 9.126 1.147 9.144 ;
     RECT  1.147 9.126 1.175 9.846 ;
     RECT  0.319 2.232 2.16 5.058 ;
     RECT  1.723 6.012 2.16 6.03 ;
     RECT  0.419 6.822 2.16 7.38 ;
     RECT  1.175 9.828 2.16 9.846 ;
     RECT  0.167 10.872 2.16 10.89 ;
     RECT  2.16 2.151 5.611 51.849 ;
     RECT  5.611 2.106 27.707 51.849 ;
     RECT  27.707 2.151 30.091 51.849 ;
     RECT  29.839 52.956 31.351 52.974 ;
     RECT  30.091 2.151 31.379 51.894 ;
     RECT  31.351 52.956 32.531 53.046 ;
     RECT  32.531 52.956 32.603 52.974 ;
     RECT  31.379 2.151 32.899 51.849 ;
     RECT  32.899 2.151 33.035 51.894 ;
     RECT  33.295 52.911 33.367 52.929 ;
     RECT  33.367 52.911 33.899 53.01 ;
     RECT  33.727 53.946 34.007 53.964 ;
     RECT  33.899 52.956 34.015 53.01 ;
     RECT  34.015 52.956 34.547 53.046 ;
     RECT  34.547 52.956 34.727 52.974 ;
     RECT  33.035 2.151 36.247 51.849 ;
     RECT  36.247 2.151 36.455 51.894 ;
     RECT  36.283 52.992 36.491 53.01 ;
     RECT  36.535 53.874 36.607 53.892 ;
     RECT  36.607 53.874 36.635 53.964 ;
     RECT  36.455 2.151 36.787 51.849 ;
     RECT  36.635 53.91 36.923 53.964 ;
     RECT  36.923 53.946 37.103 53.964 ;
     RECT  36.787 2.07 37.507 51.849 ;
     RECT  37.507 1.998 42.403 51.849 ;
     RECT  42.403 1.962 43.403 51.849 ;
     RECT  43.403 1.998 43.727 51.849 ;
     RECT  43.727 2.07 45.067 51.849 ;
     RECT  45.067 1.998 45.239 51.849 ;
     RECT  43.159 0.846 45.283 0.864 ;
     RECT  45.283 0.846 45.455 1.17 ;
     RECT  45.455 0.846 46.687 0.864 ;
     RECT  45.239 2.07 46.715 51.849 ;
     RECT  46.687 0.846 46.831 0.9 ;
     RECT  46.715 2.106 46.895 51.849 ;
     RECT  46.831 0.846 47.515 1.17 ;
     RECT  48.307 0.036 48.343 0.054 ;
     RECT  47.515 0.846 48.343 1.242 ;
     RECT  48.343 0.036 48.443 1.242 ;
     RECT  48.443 0.18 49.279 1.242 ;
     RECT  49.279 0.036 49.343 1.242 ;
     RECT  46.895 2.151 49.459 51.849 ;
     RECT  49.343 0.036 49.595 1.17 ;
     RECT  49.595 0.036 49.739 0.126 ;
     RECT  49.595 0.882 49.739 1.17 ;
     RECT  49.459 2.106 50.251 51.849 ;
     RECT  49.739 1.152 50.719 1.17 ;
     RECT  50.719 0.531 50.755 1.17 ;
     RECT  50.755 0.531 50.791 1.242 ;
     RECT  50.791 0.108 50.827 1.242 ;
     RECT  50.827 0.036 50.971 1.242 ;
     RECT  50.251 1.998 50.971 51.849 ;
     RECT  50.971 0.036 51.251 51.849 ;
     RECT  51.251 0.036 51.323 1.17 ;
     RECT  51.323 1.152 51.755 1.17 ;
     RECT  51.323 0.036 51.827 0.198 ;
     RECT  51.251 1.998 51.84 51.849 ;
     RECT  51.84 1.998 51.899 15.624 ;
     RECT  51.84 20.016 51.935 20.574 ;
     RECT  51.899 1.998 51.971 15.048 ;
     RECT  51.971 5.706 52.151 15.048 ;
     RECT  51.84 18.666 52.187 18.954 ;
     RECT  51.935 20.016 52.259 20.034 ;
     RECT  51.971 1.998 52.331 4.716 ;
     RECT  52.151 15.03 52.403 15.048 ;
     RECT  52.151 5.706 52.475 13.896 ;
     RECT  51.84 16.506 52.475 16.524 ;
     RECT  52.187 18.666 52.547 18.684 ;
     RECT  51.827 0.18 52.591 0.198 ;
     RECT  52.475 5.706 52.619 6.102 ;
     RECT  52.475 6.966 52.619 13.896 ;
     RECT  52.331 2.106 52.763 4.716 ;
     RECT  52.619 6.966 52.763 10.188 ;
     RECT  52.619 10.944 52.799 13.896 ;
     RECT  52.763 8.586 52.871 10.188 ;
     RECT  52.591 0.108 52.879 0.198 ;
     RECT  52.763 6.966 52.907 7.614 ;
     RECT  52.879 0.036 52.943 0.198 ;
     RECT  52.943 0.036 52.979 0.054 ;
     RECT  52.619 5.706 53.051 5.724 ;
     RECT  52.907 6.966 53.087 7.416 ;
     RECT  52.799 10.944 53.087 11.844 ;
     RECT  52.763 2.232 53.159 4.716 ;
     RECT  53.087 11.25 53.159 11.844 ;
     RECT  53.087 6.966 53.195 7.074 ;
     RECT  52.799 12.996 53.195 13.896 ;
     RECT  53.159 2.232 53.231 4.284 ;
     RECT  53.159 11.376 53.231 11.844 ;
     RECT  53.231 3.186 53.267 4.284 ;
     RECT  53.231 11.826 53.267 11.844 ;
     RECT  53.267 3.186 53.303 3.978 ;
     RECT  53.303 3.186 53.339 3.834 ;
     RECT  53.195 13.446 53.339 13.896 ;
     RECT  53.339 3.816 53.375 3.834 ;
     RECT  53.339 13.878 53.375 13.896 ;
     RECT  53.195 6.966 53.383 6.984 ;
     RECT  53.383 6.858 53.411 6.984 ;
     RECT  53.231 2.232 53.447 2.322 ;
     RECT  52.871 8.586 53.447 9.882 ;
     RECT  53.447 9.126 53.483 9.882 ;
     RECT  53.447 2.232 53.519 2.25 ;
     RECT  53.483 9.126 53.519 9.81 ;
     RECT  53.411 6.858 53.555 6.876 ;
     RECT  53.519 9.792 53.555 9.81 ;
    LAYER M3 ;
     RECT  48.348 0.012 52.902 0.031 ;
     RECT  48.312 0.031 52.974 0.091 ;
     RECT  46.98 0.091 52.974 0.187 ;
     RECT  46.98 0.187 53.406 0.235 ;
     RECT  41.688 0.475 41.706 0.523 ;
     RECT  45.432 0.091 46.17 0.523 ;
     RECT  46.98 0.235 53.478 0.523 ;
     RECT  41.688 0.523 41.958 0.571 ;
     RECT  42.948 0.091 44.226 0.571 ;
     RECT  45.072 0.523 53.478 1.147 ;
     RECT  41.688 0.571 44.226 1.723 ;
     RECT  45 1.147 53.478 1.723 ;
     RECT  41.688 1.723 53.478 2.029 ;
     RECT  37.512 1.993 37.53 2.065 ;
     RECT  41.4 2.029 53.478 2.101 ;
     RECT  13.215 2.143 13.305 2.191 ;
     RECT  24.015 2.143 24.105 2.191 ;
     RECT  13.215 2.191 13.662 2.227 ;
     RECT  23.472 2.191 24.105 2.227 ;
     RECT  41.328 2.101 53.478 2.227 ;
     RECT  4.248 2.227 4.266 2.251 ;
     RECT  5.616 2.101 5.634 2.251 ;
     RECT  0.216 2.227 0.234 2.263 ;
     RECT  4.248 2.251 5.634 2.263 ;
     RECT  7.815 2.143 7.905 2.263 ;
     RECT  10.728 2.227 10.746 2.263 ;
     RECT  13.215 2.227 14.13 2.263 ;
     RECT  23.472 2.227 24.822 2.263 ;
     RECT  7.416 2.263 7.905 2.299 ;
     RECT  10.728 2.263 11.286 2.299 ;
     RECT  13.14 2.263 14.13 2.299 ;
     RECT  15.696 2.227 15.714 2.299 ;
     RECT  16.488 2.227 16.506 2.299 ;
     RECT  18.615 2.143 18.705 2.299 ;
     RECT  27.684 2.101 27.702 2.299 ;
     RECT  3.42 2.263 3.438 2.335 ;
     RECT  6.624 2.191 6.642 2.335 ;
     RECT  7.416 2.299 8.478 2.335 ;
     RECT  20.376 2.263 20.394 2.335 ;
     RECT  39.348 2.251 39.366 2.335 ;
     RECT  40.215 2.143 40.305 2.335 ;
     RECT  3.42 2.335 3.51 2.371 ;
     RECT  4.248 2.263 5.742 2.371 ;
     RECT  6.624 2.335 8.478 2.371 ;
     RECT  10.584 2.299 11.286 2.371 ;
     RECT  15.696 2.299 16.506 2.371 ;
     RECT  17.676 2.263 17.694 2.371 ;
     RECT  19.764 2.335 20.394 2.371 ;
     RECT  23.436 2.263 24.822 2.371 ;
     RECT  26.352 2.191 26.37 2.371 ;
     RECT  27.684 2.299 28.35 2.371 ;
     RECT  41.328 2.227 53.514 2.371 ;
     RECT  2.415 2.143 2.505 2.413 ;
     RECT  18.615 2.299 18.774 2.413 ;
     RECT  29.415 2.143 29.505 2.413 ;
     RECT  34.815 2.143 34.905 2.413 ;
     RECT  39.348 2.335 40.305 2.413 ;
     RECT  2.415 2.413 2.697 2.461 ;
     RECT  3.42 2.371 8.946 2.461 ;
     RECT  15.66 2.371 17.694 2.461 ;
     RECT  18.615 2.413 18.897 2.461 ;
     RECT  19.764 2.371 20.79 2.461 ;
     RECT  21.528 2.371 21.546 2.461 ;
     RECT  15.588 2.461 17.694 2.491 ;
     RECT  0.216 2.263 0.27 2.497 ;
     RECT  34.815 2.413 35.097 2.497 ;
     RECT  18.615 2.461 21.582 2.533 ;
     RECT  23.4 2.371 26.838 2.533 ;
     RECT  13.14 2.299 14.562 2.539 ;
     RECT  15.588 2.491 17.874 2.539 ;
     RECT  10.584 2.371 12.114 2.569 ;
     RECT  18.615 2.533 21.906 2.569 ;
     RECT  23.4 2.533 26.874 2.569 ;
     RECT  27.684 2.371 28.386 2.569 ;
     RECT  29.415 2.413 29.697 2.569 ;
     RECT  34.596 2.497 35.097 2.569 ;
     RECT  36.792 2.065 37.53 2.569 ;
     RECT  9.864 2.569 12.114 2.587 ;
     RECT  13.14 2.539 17.874 2.587 ;
     RECT  34.524 2.569 35.097 2.587 ;
     RECT  2.415 2.461 8.946 2.605 ;
     RECT  23.4 2.569 26.91 2.605 ;
     RECT  27.684 2.569 29.697 2.605 ;
     RECT  30.492 2.299 30.51 2.605 ;
     RECT  31.356 2.461 31.77 2.605 ;
     RECT  36.792 2.569 38.178 2.605 ;
     RECT  39.348 2.413 40.497 2.605 ;
     RECT  2.34 2.605 8.946 2.641 ;
     RECT  9.864 2.587 17.874 2.641 ;
     RECT  23.4 2.605 29.697 2.641 ;
     RECT  30.492 2.605 31.77 2.641 ;
     RECT  34.524 2.587 35.154 2.641 ;
     RECT  36.792 2.605 40.497 2.641 ;
     RECT  33.084 2.641 35.154 2.683 ;
     RECT  0.108 2.497 0.27 2.731 ;
     RECT  23.4 2.641 31.842 2.731 ;
     RECT  36.576 2.641 40.497 2.731 ;
     RECT  41.22 2.371 53.514 2.731 ;
     RECT  18.615 2.569 22.374 2.779 ;
     RECT  23.364 2.731 31.95 2.779 ;
     RECT  2.34 2.641 17.874 2.911 ;
     RECT  18.615 2.779 31.95 2.911 ;
     RECT  33.084 2.683 35.622 2.911 ;
     RECT  2.34 2.911 31.95 3.019 ;
     RECT  33.084 2.911 35.802 3.137 ;
     RECT  2.304 3.019 31.95 3.307 ;
     RECT  2.304 3.307 32.094 3.451 ;
     RECT  33.084 3.137 35.73 3.451 ;
     RECT  36.576 2.731 53.514 3.451 ;
     RECT  2.304 3.451 35.73 3.569 ;
     RECT  21.456 3.569 35.73 3.749 ;
     RECT  34.56 3.749 35.73 3.955 ;
     RECT  36.54 3.451 53.514 3.955 ;
     RECT  2.304 3.569 20.538 4.109 ;
     RECT  0.108 2.731 0.846 4.145 ;
     RECT  2.304 4.109 9.018 4.189 ;
     RECT  9.9 4.109 20.538 4.459 ;
     RECT  21.456 3.749 33.822 4.459 ;
     RECT  9.9 4.459 33.822 4.693 ;
     RECT  34.56 3.955 53.514 4.693 ;
     RECT  2.232 4.189 9.018 4.747 ;
     RECT  1.728 4.747 9.018 4.891 ;
     RECT  0.108 4.145 0.126 4.999 ;
     RECT  0.108 4.999 0.27 5.035 ;
     RECT  0.108 5.035 0.342 5.165 ;
     RECT  0.252 5.165 0.342 5.213 ;
     RECT  1.728 4.891 9.09 5.269 ;
     RECT  9.9 4.693 53.514 5.269 ;
     RECT  1.728 5.269 53.514 6.035 ;
     RECT  0.324 5.213 0.342 6.221 ;
     RECT  2.268 6.035 53.514 6.817 ;
     RECT  2.232 6.817 53.514 6.853 ;
     RECT  2.232 6.853 53.55 6.893 ;
     RECT  0.108 6.817 0.198 6.955 ;
     RECT  0.108 6.955 0.342 7.531 ;
     RECT  0.108 7.531 0.378 7.66 ;
     RECT  0.108 7.66 0.414 7.757 ;
     RECT  2.268 6.893 53.55 8.033 ;
     RECT  2.268 8.033 33.282 8.683 ;
     RECT  2.232 8.683 33.282 8.735 ;
     RECT  2.304 8.735 33.282 8.879 ;
     RECT  2.304 8.879 15.39 8.969 ;
     RECT  16.452 8.879 33.282 8.971 ;
     RECT  34.092 8.033 53.55 8.971 ;
     RECT  2.304 8.969 15.282 9.005 ;
     RECT  16.452 8.971 53.55 9.005 ;
     RECT  32.112 9.005 53.55 9.011 ;
     RECT  0.108 7.757 0.162 9.149 ;
     RECT  16.452 9.005 31.374 9.661 ;
     RECT  16.056 9.661 31.374 9.751 ;
     RECT  32.112 9.011 33.246 9.751 ;
     RECT  2.304 9.005 14.886 9.787 ;
     RECT  15.804 9.751 33.246 9.787 ;
     RECT  34.092 9.011 53.55 9.815 ;
     RECT  1.152 9.121 1.17 9.851 ;
     RECT  34.092 9.815 53.478 9.887 ;
     RECT  2.304 9.787 33.354 10.021 ;
     RECT  34.092 9.887 53.37 10.021 ;
     RECT  0.144 9.149 0.162 10.786 ;
     RECT  0.036 10.786 0.162 10.814 ;
     RECT  0.036 10.814 0.054 10.895 ;
     RECT  2.304 10.021 53.37 11.399 ;
     RECT  2.415 11.399 53.37 13.631 ;
     RECT  33.912 13.631 53.37 13.667 ;
     RECT  53.352 13.667 53.37 13.901 ;
     RECT  33.912 13.667 52.542 14.009 ;
     RECT  2.415 13.631 33.174 14.135 ;
     RECT  2.415 14.135 31.086 14.813 ;
     RECT  34.128 14.009 52.542 14.917 ;
     RECT  27.792 14.813 31.086 14.953 ;
     RECT  31.896 14.135 33.174 14.953 ;
     RECT  27.792 14.953 33.174 14.989 ;
     RECT  27.792 14.989 33.246 15.025 ;
     RECT  27.792 15.025 33.282 15.089 ;
     RECT  27.9 15.089 33.282 15.151 ;
     RECT  34.056 14.917 52.542 15.151 ;
     RECT  2.415 14.813 27.018 15.179 ;
     RECT  27.9 15.151 52.542 15.179 ;
     RECT  32.328 15.179 52.542 15.251 ;
     RECT  27.9 15.179 31.482 15.629 ;
     RECT  22.14 15.179 27.018 15.835 ;
     RECT  27.9 15.629 31.374 15.835 ;
     RECT  32.508 15.251 52.542 16.105 ;
     RECT  2.415 15.179 21.402 16.231 ;
     RECT  22.14 15.835 31.374 16.231 ;
     RECT  2.415 16.231 31.374 16.411 ;
     RECT  32.112 16.105 52.542 16.411 ;
     RECT  2.415 16.411 52.542 17.179 ;
     RECT  2.376 17.179 52.542 17.581 ;
     RECT  2.34 17.581 52.542 18.689 ;
     RECT  2.34 18.689 52.254 18.803 ;
     RECT  27.9 18.803 52.254 18.869 ;
     RECT  27.972 18.869 52.254 19.139 ;
     RECT  2.34 18.803 27.126 19.373 ;
     RECT  27.972 19.139 44.838 19.607 ;
     RECT  2.376 19.373 27.126 19.679 ;
     RECT  2.376 19.679 26.946 19.853 ;
     RECT  28.008 19.607 44.838 20.011 ;
     RECT  45.576 19.139 52.254 20.011 ;
     RECT  28.008 20.011 52.254 20.039 ;
     RECT  2.376 19.853 26.91 20.183 ;
     RECT  11.772 20.183 26.91 20.219 ;
     RECT  28.008 20.039 51.93 20.353 ;
     RECT  11.772 20.219 26.55 20.579 ;
     RECT  27.936 20.353 51.93 20.579 ;
     RECT  27.936 20.579 51.678 20.587 ;
     RECT  2.376 20.183 10.998 20.621 ;
     RECT  27.9 20.587 51.678 20.731 ;
     RECT  12.24 20.579 26.55 20.759 ;
     RECT  2.415 20.621 10.998 20.965 ;
     RECT  27.684 20.731 51.678 21.119 ;
     RECT  27.684 21.119 30.906 21.149 ;
     RECT  27.684 21.149 30.87 21.271 ;
     RECT  2.415 20.965 11.358 21.361 ;
     RECT  12.24 20.759 26.406 21.361 ;
     RECT  2.415 21.361 26.406 21.541 ;
     RECT  27.54 21.271 30.87 21.541 ;
     RECT  2.415 21.541 26.514 21.631 ;
     RECT  31.644 21.119 51.678 21.731 ;
     RECT  2.415 21.631 26.586 21.811 ;
     RECT  27.396 21.541 30.87 21.811 ;
     RECT  48.564 21.731 51.678 22.045 ;
     RECT  2.376 21.811 30.87 22.199 ;
     RECT  27.612 22.199 30.87 22.207 ;
     RECT  31.644 21.731 47.826 22.207 ;
     RECT  2.376 22.199 26.478 22.343 ;
     RECT  2.376 22.343 14.598 22.577 ;
     RECT  27.612 22.207 47.826 22.577 ;
     RECT  48.564 22.045 51.714 22.739 ;
     RECT  2.376 22.577 14.562 22.781 ;
     RECT  15.336 22.343 26.478 22.811 ;
     RECT  27.612 22.577 46.098 22.847 ;
     RECT  27.612 22.847 32.238 23.009 ;
     RECT  18.576 22.811 26.478 23.161 ;
     RECT  27.612 23.009 32.202 23.161 ;
     RECT  32.976 22.847 46.098 23.189 ;
     RECT  33.12 23.189 46.098 23.279 ;
     RECT  46.836 22.577 47.826 23.287 ;
     RECT  48.564 22.739 51.462 23.287 ;
     RECT  33.192 23.279 46.098 23.359 ;
     RECT  46.836 23.287 51.462 23.359 ;
     RECT  2.376 22.781 14.526 23.521 ;
     RECT  15.336 22.811 17.802 23.521 ;
     RECT  2.376 23.521 17.802 23.549 ;
     RECT  33.192 23.359 51.462 23.657 ;
     RECT  2.415 23.549 17.802 23.665 ;
     RECT  18.576 23.161 32.202 23.665 ;
     RECT  2.415 23.665 32.202 23.971 ;
     RECT  33.192 23.657 51.297 24.161 ;
     RECT  2.415 23.971 32.31 24.169 ;
     RECT  33.192 24.161 48.402 24.169 ;
     RECT  2.415 24.169 48.402 24.233 ;
     RECT  23.94 24.233 48.402 24.269 ;
     RECT  23.94 24.269 24.318 24.359 ;
     RECT  25.056 24.269 48.402 24.359 ;
     RECT  25.056 24.359 48.258 24.431 ;
     RECT  49.176 24.161 51.297 24.511 ;
     RECT  25.056 24.431 48.222 24.629 ;
     RECT  49.176 24.511 51.714 24.899 ;
     RECT  49.176 24.899 51.297 24.907 ;
     RECT  25.056 24.629 48.15 25.079 ;
     RECT  24.015 24.359 24.297 25.177 ;
     RECT  25.056 25.079 38.25 25.177 ;
     RECT  24.015 25.177 38.25 25.205 ;
     RECT  2.415 24.233 23.202 25.321 ;
     RECT  24.015 25.205 38.142 25.321 ;
     RECT  38.988 25.079 48.15 25.591 ;
     RECT  49.14 24.907 51.297 25.591 ;
     RECT  2.415 25.321 38.142 25.613 ;
     RECT  2.415 25.613 20.682 25.681 ;
     RECT  2.376 25.681 20.682 26.015 ;
     RECT  4.284 26.015 20.682 26.249 ;
     RECT  4.32 26.249 20.682 26.285 ;
     RECT  21.6 25.613 38.142 26.293 ;
     RECT  38.988 25.591 51.297 26.293 ;
     RECT  7.236 26.285 20.682 26.321 ;
     RECT  2.376 26.015 3.51 26.789 ;
     RECT  7.236 26.321 20.574 26.789 ;
     RECT  21.6 26.293 51.297 26.905 ;
     RECT  4.32 26.285 6.426 27.031 ;
     RECT  7.236 26.789 20.502 27.031 ;
     RECT  4.32 27.031 20.502 27.067 ;
     RECT  2.415 26.789 3.51 27.103 ;
     RECT  4.284 27.067 20.502 27.103 ;
     RECT  21.312 26.905 51.297 27.401 ;
     RECT  2.415 27.103 20.502 27.787 ;
     RECT  21.312 27.401 36.27 27.787 ;
     RECT  2.415 27.787 36.27 28.147 ;
     RECT  37.044 27.401 51.297 28.147 ;
     RECT  2.415 28.147 51.297 28.823 ;
     RECT  2.415 28.823 3.546 28.985 ;
     RECT  4.5 28.823 51.297 29.117 ;
     RECT  4.5 29.117 39.15 29.219 ;
     RECT  40.14 29.117 51.297 29.219 ;
     RECT  40.176 29.219 51.297 29.371 ;
     RECT  40.176 29.371 51.714 29.633 ;
     RECT  4.5 29.219 5.382 29.641 ;
     RECT  4.104 29.641 5.382 29.645 ;
     RECT  2.415 28.985 3.366 29.755 ;
     RECT  4.104 29.645 5.166 29.755 ;
     RECT  40.176 29.633 51.297 29.831 ;
     RECT  6.228 29.219 39.15 29.995 ;
     RECT  6.228 29.995 39.222 30.001 ;
     RECT  40.212 29.831 51.297 30.065 ;
     RECT  2.415 29.755 5.166 30.451 ;
     RECT  6.192 30.001 39.222 30.541 ;
     RECT  2.415 30.451 5.454 30.577 ;
     RECT  6.192 30.541 39.33 30.577 ;
     RECT  2.415 30.577 39.33 30.955 ;
     RECT  2.415 30.955 39.402 31.019 ;
     RECT  2.415 31.019 39.33 31.261 ;
     RECT  40.215 30.065 51.297 31.729 ;
     RECT  40.176 31.729 51.297 31.765 ;
     RECT  40.176 31.765 51.714 31.801 ;
     RECT  2.376 31.261 39.33 31.891 ;
     RECT  40.14 31.801 51.714 31.891 ;
     RECT  2.376 31.891 51.714 31.919 ;
     RECT  47.268 31.919 49.806 31.955 ;
     RECT  50.544 31.919 51.714 32.189 ;
     RECT  2.376 31.919 46.278 32.737 ;
     RECT  47.304 31.955 49.806 32.737 ;
     RECT  2.376 32.737 49.806 32.845 ;
     RECT  50.544 32.189 51.354 32.845 ;
     RECT  2.376 32.845 51.354 33.241 ;
     RECT  2.376 33.241 51.462 33.385 ;
     RECT  2.376 33.385 51.606 33.719 ;
     RECT  2.415 33.719 51.606 34.253 ;
     RECT  2.415 34.253 42.678 34.493 ;
     RECT  43.632 34.253 51.606 34.619 ;
     RECT  43.776 34.619 51.606 34.889 ;
     RECT  44.136 34.889 51.606 35.275 ;
     RECT  2.415 34.493 37.638 35.311 ;
     RECT  38.412 34.493 42.678 35.311 ;
     RECT  44.136 35.275 51.714 35.699 ;
     RECT  2.415 35.311 42.93 35.851 ;
     RECT  2.415 35.851 43.074 36.077 ;
     RECT  4.608 36.077 43.074 36.121 ;
     RECT  2.415 36.077 3.798 36.311 ;
     RECT  2.415 36.311 3.69 36.391 ;
     RECT  44.136 35.699 51.354 36.481 ;
     RECT  44.028 36.481 51.354 36.553 ;
     RECT  4.608 36.121 43.254 36.589 ;
     RECT  43.992 36.553 51.354 36.589 ;
     RECT  4.608 36.589 51.462 36.689 ;
     RECT  4.608 36.689 51.426 36.931 ;
     RECT  2.376 36.391 3.69 37.093 ;
     RECT  4.464 36.931 51.426 37.093 ;
     RECT  2.376 37.093 51.426 37.741 ;
     RECT  2.376 37.741 51.498 37.975 ;
     RECT  2.376 37.975 51.57 38.579 ;
     RECT  49.68 38.579 51.57 38.669 ;
     RECT  50.04 38.669 51.57 38.821 ;
     RECT  50.04 38.821 51.642 38.849 ;
     RECT  2.376 38.579 48.942 38.939 ;
     RECT  50.076 38.849 51.642 39.209 ;
     RECT  50.076 39.209 51.57 39.595 ;
     RECT  2.415 38.939 48.942 39.793 ;
     RECT  49.968 39.595 51.57 40.019 ;
     RECT  2.415 39.793 49.122 40.063 ;
     RECT  2.415 40.063 49.194 40.135 ;
     RECT  49.968 40.019 51.426 40.135 ;
     RECT  2.415 40.135 51.426 40.531 ;
     RECT  2.376 40.531 51.426 40.703 ;
     RECT  2.376 40.703 51.354 40.829 ;
     RECT  2.415 40.829 51.354 41.791 ;
     RECT  2.415 41.791 51.498 41.989 ;
     RECT  2.415 41.989 51.642 42.179 ;
     RECT  2.415 42.179 51.498 42.215 ;
     RECT  2.415 42.215 51.426 42.331 ;
     RECT  2.376 42.331 51.426 42.719 ;
     RECT  2.415 42.719 51.426 43.529 ;
     RECT  2.415 43.529 51.354 43.681 ;
     RECT  2.376 43.681 51.354 43.799 ;
     RECT  2.415 43.799 51.354 44.455 ;
     RECT  2.415 44.455 51.714 44.609 ;
     RECT  2.415 44.609 51.642 45.157 ;
     RECT  2.34 45.157 51.642 45.185 ;
     RECT  2.34 45.185 51.462 45.455 ;
     RECT  2.415 45.455 51.462 45.689 ;
     RECT  2.415 45.689 51.354 45.833 ;
     RECT  16.524 45.833 51.354 46.615 ;
     RECT  2.415 45.833 15.39 46.777 ;
     RECT  16.236 46.615 51.354 46.777 ;
     RECT  2.415 46.777 51.354 46.921 ;
     RECT  2.415 46.921 51.39 47.389 ;
     RECT  2.415 47.389 51.462 47.489 ;
     RECT  2.415 47.489 51.39 47.885 ;
     RECT  2.415 47.885 3.582 47.957 ;
     RECT  2.415 47.957 3.474 48.119 ;
     RECT  4.644 47.885 51.39 48.235 ;
     RECT  3.456 48.119 3.474 48.263 ;
     RECT  4.644 48.235 51.714 48.389 ;
     RECT  4.824 48.389 51.462 48.659 ;
     RECT  4.896 48.659 51.462 48.695 ;
     RECT  4.968 48.695 51.462 49.421 ;
     RECT  5.184 49.421 51.462 49.469 ;
     RECT  5.796 49.469 48.798 49.577 ;
     RECT  49.572 49.469 51.462 49.613 ;
     RECT  5.832 49.577 48.798 49.649 ;
     RECT  5.868 49.649 10.998 49.739 ;
     RECT  49.644 49.613 51.462 49.739 ;
     RECT  5.868 49.739 10.926 49.775 ;
     RECT  12.06 49.649 48.798 49.775 ;
     RECT  50.4 49.739 51.354 50.009 ;
     RECT  49.644 49.739 49.662 50.045 ;
     RECT  5.976 49.775 10.926 50.153 ;
     RECT  14.832 49.775 48.798 50.521 ;
     RECT  50.4 50.009 51.297 50.549 ;
     RECT  12.06 49.775 14.022 50.557 ;
     RECT  50.544 50.549 51.297 50.585 ;
     RECT  9.612 50.153 10.926 50.701 ;
     RECT  12.024 50.557 14.022 50.701 ;
     RECT  14.796 50.521 48.798 50.701 ;
     RECT  5.976 50.153 8.622 50.791 ;
     RECT  14.796 50.701 48.834 50.819 ;
     RECT  5.94 50.791 8.622 50.891 ;
     RECT  6.012 50.891 8.622 50.935 ;
     RECT  9.612 50.701 14.022 50.935 ;
     RECT  6.012 50.935 14.022 50.963 ;
     RECT  6.264 50.963 14.022 50.971 ;
     RECT  14.796 50.819 48.618 50.971 ;
     RECT  6.264 50.971 48.618 50.999 ;
     RECT  6.264 50.999 8.586 51.089 ;
     RECT  6.264 51.089 8.514 51.125 ;
     RECT  9.324 50.999 48.618 51.125 ;
     RECT  9.432 51.125 20.286 51.269 ;
     RECT  27.468 51.125 48.618 51.269 ;
     RECT  6.264 51.125 8.478 51.293 ;
     RECT  9.432 51.269 10.854 51.359 ;
     RECT  11.808 51.269 20.286 51.359 ;
     RECT  27.468 51.269 48.546 51.359 ;
     RECT  21.096 51.125 26.73 51.389 ;
     RECT  6.84 51.293 8.478 51.395 ;
     RECT  11.808 51.359 17.874 51.395 ;
     RECT  21.096 51.389 21.15 51.395 ;
     RECT  41.724 51.359 48.546 51.395 ;
     RECT  27.468 51.359 40.986 51.431 ;
     RECT  47.484 51.395 48.222 51.431 ;
     RECT  6.84 51.395 6.858 51.467 ;
     RECT  27.468 51.431 37.458 51.503 ;
     RECT  41.724 51.395 46.746 51.503 ;
     RECT  11.808 51.395 14.346 51.539 ;
     RECT  21.132 51.395 21.15 51.539 ;
     RECT  22.068 51.389 26.73 51.539 ;
     RECT  47.52 51.431 48.222 51.539 ;
     RECT  2.415 48.119 2.697 51.587 ;
     RECT  51.015 50.585 51.297 51.587 ;
     RECT  7.596 51.395 8.478 51.629 ;
     RECT  9.432 51.359 9.594 51.629 ;
     RECT  10.368 51.359 10.854 51.629 ;
     RECT  11.808 51.539 12.402 51.629 ;
     RECT  13.215 51.539 14.346 51.629 ;
     RECT  15.228 51.395 17.874 51.629 ;
     RECT  18.615 51.359 19.494 51.629 ;
     RECT  20.268 51.359 20.286 51.629 ;
     RECT  22.068 51.539 25.398 51.629 ;
     RECT  26.28 51.539 26.73 51.629 ;
     RECT  27.468 51.503 28.098 51.629 ;
     RECT  29.415 51.503 37.458 51.629 ;
     RECT  38.268 51.431 40.986 51.629 ;
     RECT  41.724 51.503 45.954 51.629 ;
     RECT  46.728 51.503 46.746 51.629 ;
     RECT  47.52 51.539 48.114 51.629 ;
     RECT  16.308 51.629 17.694 51.635 ;
     RECT  7.596 51.629 8.334 51.665 ;
     RECT  9.432 51.629 9.45 51.665 ;
     RECT  10.476 51.629 10.854 51.665 ;
     RECT  11.808 51.629 11.826 51.665 ;
     RECT  24.015 51.629 24.786 51.665 ;
     RECT  27.468 51.629 28.026 51.665 ;
     RECT  29.415 51.629 37.386 51.665 ;
     RECT  41.724 51.629 42.93 51.665 ;
     RECT  22.248 51.629 22.266 51.737 ;
     RECT  41.724 51.665 42.246 51.737 ;
     RECT  7.632 51.665 7.905 51.773 ;
     RECT  17.676 51.635 17.694 51.773 ;
     RECT  32.148 51.665 37.386 51.773 ;
     RECT  38.88 51.629 40.986 51.773 ;
     RECT  43.74 51.629 43.758 51.773 ;
     RECT  10.836 51.665 10.854 51.809 ;
     RECT  16.884 51.635 16.902 51.809 ;
     RECT  27.468 51.665 27.486 51.809 ;
     RECT  29.415 51.665 31.41 51.809 ;
     RECT  32.148 51.773 37.098 51.809 ;
     RECT  38.88 51.773 40.305 51.809 ;
     RECT  44.748 51.629 44.766 51.809 ;
     RECT  32.148 51.809 35.514 51.821 ;
     RECT  2.415 51.587 2.505 51.857 ;
     RECT  7.815 51.773 7.905 51.857 ;
     RECT  13.215 51.629 13.305 51.857 ;
     RECT  18.615 51.629 18.705 51.857 ;
     RECT  24.015 51.665 24.105 51.857 ;
     RECT  29.415 51.809 30.114 51.857 ;
     RECT  32.148 51.821 34.905 51.857 ;
     RECT  40.215 51.809 40.305 51.857 ;
     RECT  45.615 51.629 45.705 51.857 ;
     RECT  51.015 51.587 51.105 51.857 ;
     RECT  29.844 51.857 30.114 51.899 ;
     RECT  29.844 51.899 29.862 52.979 ;
     RECT  32.148 51.857 34.722 52.979 ;
     RECT  31.356 51.809 31.374 53.051 ;
     RECT  32.148 52.979 34.542 53.051 ;
     RECT  36.252 51.809 37.098 53.969 ;
     RECT  32.148 53.051 34.398 53.981 ;
     RECT  36.252 53.969 36.702 53.981 ;
    LAYER M4 ;
     RECT  0.06 2.64 0.227 8.712 ;
     RECT  0.227 2.736 0.857 8.712 ;
     RECT  0.857 2.832 2.293 8.712 ;
     RECT  2.293 2.832 2.408 8.76 ;
     RECT  2.365 17.184 2.408 17.208 ;
     RECT  2.329 19.344 2.408 19.368 ;
     RECT  2.365 20.592 2.408 20.616 ;
     RECT  2.365 23.376 2.408 23.4 ;
     RECT  0.181 27.408 2.408 27.432 ;
     RECT  2.365 33.12 2.408 33.144 ;
     RECT  2.365 38.16 2.408 38.184 ;
     RECT  2.365 40.56 2.408 40.584 ;
     RECT  2.329 45.168 2.408 45.192 ;
     RECT  2.408 2.148 2.512 51.852 ;
     RECT  2.512 2.418 2.704 51.582 ;
     RECT  2.704 38.16 2.873 41.592 ;
     RECT  2.704 2.832 2.945 12.552 ;
     RECT  2.945 5.04 3.017 12.552 ;
     RECT  2.704 16.8 3.053 17.208 ;
     RECT  2.704 45.168 3.053 46.728 ;
     RECT  2.704 14.832 3.089 15.72 ;
     RECT  3.017 5.184 3.125 12.552 ;
     RECT  3.089 15.024 3.161 15.72 ;
     RECT  3.053 16.8 3.341 17.064 ;
     RECT  2.704 20.592 3.413 21.672 ;
     RECT  2.704 33.12 3.593 33.144 ;
     RECT  2.873 40.176 3.593 41.592 ;
     RECT  2.704 28.944 3.635 29.784 ;
     RECT  3.125 6.864 3.665 12.552 ;
     RECT  2.704 27.504 3.697 27.864 ;
     RECT  3.635 28.944 3.697 29.256 ;
     RECT  3.593 40.512 3.701 41.592 ;
     RECT  2.704 34.608 3.733 35.064 ;
     RECT  3.161 15.024 3.809 15.048 ;
     RECT  3.413 21.168 3.881 21.672 ;
     RECT  2.873 38.16 3.884 38.424 ;
     RECT  3.733 33.552 3.949 35.064 ;
     RECT  3.701 41.568 3.949 41.592 ;
     RECT  2.704 42.576 3.949 43.704 ;
     RECT  3.881 21.648 4.061 21.672 ;
     RECT  3.949 41.568 4.061 43.704 ;
     RECT  3.125 5.184 4.129 5.304 ;
     RECT  3.665 7.2 4.133 12.552 ;
     RECT  3.697 27.504 4.201 29.256 ;
     RECT  2.945 2.832 4.237 3.672 ;
     RECT  2.704 19.248 4.241 19.416 ;
     RECT  4.129 5.184 4.277 5.736 ;
     RECT  3.884 37.44 4.277 38.424 ;
     RECT  3.949 33.552 4.3 35.88 ;
     RECT  4.201 27.36 4.309 29.256 ;
     RECT  2.704 23.328 4.349 23.4 ;
     RECT  2.704 24.48 4.381 24.552 ;
     RECT  2.704 25.68 4.381 25.704 ;
     RECT  4.237 2.256 4.453 3.672 ;
     RECT  4.237 13.68 4.453 13.704 ;
     RECT  4.453 13.392 4.489 13.704 ;
     RECT  4.381 24.48 4.549 25.704 ;
     RECT  4.417 31.872 4.561 31.896 ;
     RECT  4.3 35.712 4.597 35.88 ;
     RECT  4.061 43.152 4.604 43.704 ;
     RECT  3.053 45.168 4.604 46.488 ;
     RECT  4.241 19.392 4.652 19.416 ;
     RECT  4.561 31.632 4.669 31.896 ;
     RECT  4.061 41.568 4.669 42.168 ;
     RECT  3.341 17.04 4.673 17.064 ;
     RECT  4.604 43.152 4.691 46.488 ;
     RECT  3.985 18.24 4.693 18.264 ;
     RECT  4.652 19.392 4.709 19.992 ;
     RECT  4.309 26.928 4.789 29.256 ;
     RECT  4.597 35.712 4.789 36.36 ;
     RECT  4.277 37.44 4.789 38.04 ;
     RECT  4.789 26.928 4.892 29.64 ;
     RECT  4.489 13.392 4.925 13.992 ;
     RECT  4.892 26.928 4.925 30.12 ;
     RECT  4.669 31.632 4.957 32.472 ;
     RECT  4.691 45.792 4.957 46.488 ;
     RECT  4.453 2.256 4.961 3.912 ;
     RECT  4.925 27.072 4.979 30.12 ;
     RECT  4.789 35.712 5.033 38.04 ;
     RECT  4.957 31.44 5.077 32.472 ;
     RECT  4.133 7.2 5.101 12.36 ;
     RECT  5.077 31.248 5.137 32.472 ;
     RECT  4.3 33.552 5.137 34.392 ;
     RECT  4.549 24.096 5.141 25.704 ;
     RECT  4.561 39.264 5.177 39.288 ;
     RECT  4.693 17.328 5.213 18.264 ;
     RECT  4.957 45.792 5.213 47.448 ;
     RECT  5.101 7.056 5.221 12.36 ;
     RECT  4.925 13.392 5.221 13.56 ;
     RECT  5.213 46.224 5.267 47.448 ;
     RECT  5.221 7.056 5.308 13.56 ;
     RECT  5.033 37.44 5.372 38.04 ;
     RECT  5.033 35.712 5.389 36.408 ;
     RECT  3.701 40.512 5.389 40.536 ;
     RECT  4.669 41.52 5.389 42.168 ;
     RECT  5.372 37.44 5.459 38.664 ;
     RECT  5.459 37.44 5.465 38.04 ;
     RECT  5.221 14.64 5.501 14.664 ;
     RECT  5.465 37.44 5.555 37.608 ;
     RECT  5.389 35.52 5.573 36.408 ;
     RECT  4.277 5.712 5.605 5.736 ;
     RECT  5.605 5.376 5.651 5.736 ;
     RECT  5.308 7.056 5.713 13.32 ;
     RECT  4.691 43.152 5.713 43.704 ;
     RECT  4.961 2.64 5.749 3.912 ;
     RECT  5.651 5.376 5.749 5.4 ;
     RECT  5.573 35.52 5.753 36.36 ;
     RECT  5.141 24.096 5.825 25.032 ;
     RECT  5.213 17.424 5.852 18.264 ;
     RECT  4.957 49.392 5.861 49.416 ;
     RECT  4.709 19.968 5.893 19.992 ;
     RECT  5.425 21.648 5.893 21.672 ;
     RECT  5.389 40.512 5.893 42.168 ;
     RECT  5.713 43.152 5.893 44.328 ;
     RECT  5.713 7.008 5.897 13.32 ;
     RECT  5.137 31.248 5.897 34.392 ;
     RECT  5.353 47.856 5.897 47.88 ;
     RECT  5.852 17.424 5.939 18.744 ;
     RECT  5.825 24.096 5.969 24.456 ;
     RECT  5.897 11.664 6.041 13.32 ;
     RECT  5.897 32.448 6.041 34.392 ;
     RECT  6.041 11.664 6.077 13.08 ;
     RECT  5.821 23.088 6.181 23.112 ;
     RECT  5.969 24.096 6.181 24.12 ;
     RECT  4.979 27.072 6.217 29.64 ;
     RECT  5.897 7.008 6.253 10.632 ;
     RECT  5.749 2.64 6.289 5.4 ;
     RECT  5.267 46.224 6.293 46.488 ;
     RECT  5.533 15.12 6.329 15.384 ;
     RECT  5.893 40.512 6.329 44.328 ;
     RECT  6.329 44.112 6.401 44.328 ;
     RECT  5.897 31.248 6.433 31.464 ;
     RECT  5.893 19.968 6.437 21.672 ;
     RECT  6.289 2.544 6.545 5.4 ;
     RECT  6.217 27.072 6.577 29.88 ;
     RECT  6.433 30.96 6.577 31.464 ;
     RECT  6.329 40.512 6.577 42.792 ;
     RECT  5.965 48.24 6.577 48.264 ;
     RECT  6.577 27.072 6.613 31.464 ;
     RECT  6.545 2.832 6.617 5.4 ;
     RECT  6.577 48.24 6.617 48.984 ;
     RECT  6.613 26.256 6.653 31.464 ;
     RECT  6.617 3.552 6.659 5.4 ;
     RECT  6.253 6.816 6.689 10.632 ;
     RECT  6.659 3.552 6.755 4.68 ;
     RECT  5.555 37.584 6.757 37.608 ;
     RECT  6.689 6.816 6.761 9.624 ;
     RECT  6.329 15.12 6.793 15.192 ;
     RECT  5.753 35.52 6.793 36.264 ;
     RECT  6.293 46.224 6.793 46.248 ;
     RECT  6.577 39.888 6.797 42.792 ;
     RECT  6.653 26.256 6.901 31.176 ;
     RECT  6.689 10.608 7.009 10.632 ;
     RECT  6.041 32.448 7.117 33.96 ;
     RECT  6.793 45.888 7.225 46.248 ;
     RECT  7.225 45.456 7.261 46.248 ;
     RECT  7.117 32.448 7.297 34.152 ;
     RECT  6.793 35.136 7.297 36.264 ;
     RECT  6.401 44.112 7.369 44.184 ;
     RECT  7.261 45.216 7.369 46.248 ;
     RECT  6.253 51.264 7.381 51.288 ;
     RECT  7.297 32.448 7.405 36.264 ;
     RECT  6.797 41.472 7.477 42.792 ;
     RECT  7.369 43.92 7.477 44.184 ;
     RECT  7.405 32.448 7.513 36.36 ;
     RECT  6.181 23.088 7.549 24.12 ;
     RECT  7.381 50.688 7.549 51.288 ;
     RECT  6.077 12.528 7.657 12.792 ;
     RECT  6.793 14.208 7.657 15.192 ;
     RECT  6.761 9.6 7.669 9.624 ;
     RECT  7.009 10.608 7.669 11.4 ;
     RECT  7.657 12.528 7.669 15.192 ;
     RECT  6.437 19.968 7.729 20.712 ;
     RECT  6.755 3.552 7.808 4.536 ;
     RECT  6.761 6.816 7.808 8.568 ;
     RECT  7.669 9.6 7.808 15.192 ;
     RECT  5.939 17.424 7.808 18.552 ;
     RECT  7.729 19.968 7.808 21.528 ;
     RECT  7.549 23.088 7.808 24.648 ;
     RECT  6.901 25.824 7.808 31.176 ;
     RECT  7.513 32.448 7.808 36.504 ;
     RECT  6.757 37.584 7.808 38.76 ;
     RECT  6.797 39.888 7.808 40.056 ;
     RECT  7.477 41.472 7.808 44.184 ;
     RECT  7.369 45.168 7.808 46.248 ;
     RECT  6.617 48.96 7.808 48.984 ;
     RECT  7.549 50.592 7.808 51.288 ;
     RECT  7.808 2.148 7.912 51.852 ;
     RECT  7.912 2.418 8.104 51.582 ;
     RECT  8.104 9.6 8.165 10.44 ;
     RECT  8.104 17.424 8.201 18.792 ;
     RECT  8.104 26.256 8.237 31.512 ;
     RECT  8.104 33.984 8.237 37.608 ;
     RECT  8.104 5.184 8.243 8.616 ;
     RECT  8.104 11.472 8.243 16.104 ;
     RECT  8.237 36.24 8.243 37.608 ;
     RECT  8.104 38.736 8.243 49.56 ;
     RECT  8.104 19.776 8.273 19.8 ;
     RECT  8.243 36.24 8.284 36.936 ;
     RECT  8.243 11.472 8.345 14.232 ;
     RECT  8.104 2.832 8.381 4.152 ;
     RECT  8.165 9.6 8.381 10.344 ;
     RECT  8.243 38.976 8.387 49.56 ;
     RECT  8.201 18 8.525 18.792 ;
     RECT  8.387 45.216 8.525 49.56 ;
     RECT  8.243 5.856 8.572 8.616 ;
     RECT  8.104 21.504 8.579 21.672 ;
     RECT  8.345 11.856 8.597 14.232 ;
     RECT  8.104 22.704 8.633 25.08 ;
     RECT  8.381 9.6 8.669 9.624 ;
     RECT  8.237 33.984 8.812 35.16 ;
     RECT  8.381 2.832 8.819 3.96 ;
     RECT  8.597 11.856 8.921 12.552 ;
     RECT  8.633 23.328 9.029 25.08 ;
     RECT  8.525 45.792 9.164 49.56 ;
     RECT  8.104 50.592 9.164 50.856 ;
     RECT  9.164 45.792 9.173 50.856 ;
     RECT  9.173 47.424 9.205 50.856 ;
     RECT  8.237 26.304 9.245 28.92 ;
     RECT  9.205 47.424 9.251 51.384 ;
     RECT  8.284 36.24 9.313 36.456 ;
     RECT  9.241 37.872 9.421 37.896 ;
     RECT  8.579 21.648 9.425 21.672 ;
     RECT  8.237 30.096 9.529 31.512 ;
     RECT  9.313 36.24 9.565 36.504 ;
     RECT  9.421 37.488 9.565 37.896 ;
     RECT  8.572 5.856 9.637 5.88 ;
     RECT  8.572 6.864 9.637 8.616 ;
     RECT  9.245 27.12 9.709 28.92 ;
     RECT  9.529 30.096 9.709 32.472 ;
     RECT  8.387 38.976 9.713 43.944 ;
     RECT  9.565 36.24 9.749 37.896 ;
     RECT  9.713 38.976 9.749 43.032 ;
     RECT  9.673 9.6 9.757 9.624 ;
     RECT  9.133 16.656 9.817 16.68 ;
     RECT  8.921 11.856 9.889 11.88 ;
     RECT  9.749 41.76 9.893 43.032 ;
     RECT  8.597 13.584 10.001 14.232 ;
     RECT  9.889 11.856 10.033 12.024 ;
     RECT  8.812 34.512 10.033 35.16 ;
     RECT  8.525 18.72 10.069 18.792 ;
     RECT  8.819 3.312 10.105 3.96 ;
     RECT  9.817 16.656 10.109 17.016 ;
     RECT  10.069 18.432 10.153 19.416 ;
     RECT  10.105 3.312 10.165 4.248 ;
     RECT  9.637 5.856 10.165 8.616 ;
     RECT  10.033 34.32 10.165 35.16 ;
     RECT  9.749 36.24 10.165 37.752 ;
     RECT  10.165 34.32 10.211 37.752 ;
     RECT  10.109 16.656 10.213 16.68 ;
     RECT  9.709 20.496 10.213 20.52 ;
     RECT  9.251 47.424 10.213 49.512 ;
     RECT  9.251 51.216 10.213 51.384 ;
     RECT  9.029 23.376 10.289 25.08 ;
     RECT  10.213 47.424 10.325 51.384 ;
     RECT  10.165 3.312 10.357 8.616 ;
     RECT  10.357 2.832 10.361 8.616 ;
     RECT  10.361 2.832 10.405 5.88 ;
     RECT  10.213 15.744 10.429 16.68 ;
     RECT  10.429 15.552 10.433 16.68 ;
     RECT  9.749 38.976 10.433 40.632 ;
     RECT  10.033 11.376 10.537 12.024 ;
     RECT  10.537 11.376 10.613 12.504 ;
     RECT  10.613 11.856 10.649 12.504 ;
     RECT  10.325 50.688 10.649 51.384 ;
     RECT  9.709 27.12 10.681 32.472 ;
     RECT  10.681 27.12 10.753 32.904 ;
     RECT  10.211 34.32 10.753 34.344 ;
     RECT  10.405 2.256 10.757 5.88 ;
     RECT  9.173 45.792 10.789 46.008 ;
     RECT  9.853 44.448 10.825 44.472 ;
     RECT  10.789 45.696 10.825 46.008 ;
     RECT  10.757 2.592 10.835 5.16 ;
     RECT  10.213 20.496 10.865 21.144 ;
     RECT  10.211 35.424 10.933 37.752 ;
     RECT  10.433 38.976 10.933 39.096 ;
     RECT  10.433 15.552 10.937 15.768 ;
     RECT  10.649 50.688 10.937 51.24 ;
     RECT  10.153 18.432 10.973 19.32 ;
     RECT  10.825 44.448 11.041 46.008 ;
     RECT  10.717 47.184 11.041 47.208 ;
     RECT  9.893 41.76 11.125 42.744 ;
     RECT  11.041 44.448 11.125 47.208 ;
     RECT  10.753 27.12 11.132 34.344 ;
     RECT  11.125 41.76 11.149 47.208 ;
     RECT  10.361 7.2 11.18 8.616 ;
     RECT  10.865 21.12 11.189 21.144 ;
     RECT  11.132 26.256 11.219 34.344 ;
     RECT  11.18 7.2 11.267 8.904 ;
     RECT  10.649 11.952 11.329 12.504 ;
     RECT  10.001 13.584 11.329 13.608 ;
     RECT  10.325 48.384 11.365 49.512 ;
     RECT  10.835 2.592 11.369 5.016 ;
     RECT  11.219 26.832 11.413 34.344 ;
     RECT  10.933 35.424 11.413 39.096 ;
     RECT  11.329 11.952 11.477 13.608 ;
     RECT  11.413 26.832 11.477 39.096 ;
     RECT  10.393 22.224 11.509 22.248 ;
     RECT  10.289 23.376 11.509 24.936 ;
     RECT  11.477 26.832 11.513 32.472 ;
     RECT  10.973 18.432 11.621 19.272 ;
     RECT  11.509 22.224 11.689 24.936 ;
     RECT  11.621 18.432 11.725 18.456 ;
     RECT  11.513 26.832 11.729 32.328 ;
     RECT  11.725 17.664 11.761 18.456 ;
     RECT  10.937 51.216 11.797 51.24 ;
     RECT  11.369 4.128 11.833 5.016 ;
     RECT  11.797 51.216 11.941 51.384 ;
     RECT  11.267 7.2 11.945 8.088 ;
     RECT  11.149 41.664 11.945 47.208 ;
     RECT  11.369 2.592 11.987 3.144 ;
     RECT  11.833 4.128 11.987 5.16 ;
     RECT  11.945 45.072 11.989 47.208 ;
     RECT  11.365 48.384 11.989 49.608 ;
     RECT  11.941 50.88 11.989 51.384 ;
     RECT  10.433 40.56 12.053 40.632 ;
     RECT  11.989 45.072 12.053 51.384 ;
     RECT  11.477 33.504 12.085 39.096 ;
     RECT  11.945 41.664 12.085 43.944 ;
     RECT  11.689 22.08 12.089 24.936 ;
     RECT  12.089 22.704 12.125 24.936 ;
     RECT  10.937 15.552 12.157 15.576 ;
     RECT  11.761 16.896 12.157 18.456 ;
     RECT  12.053 45.696 12.161 51.384 ;
     RECT  12.085 33.504 12.197 39.72 ;
     RECT  11.729 26.832 12.229 28.728 ;
     RECT  10.717 10.032 12.325 10.056 ;
     RECT  11.945 7.44 12.445 8.088 ;
     RECT  12.325 9.264 12.445 10.056 ;
     RECT  12.229 5.616 12.625 5.64 ;
     RECT  12.625 5.616 12.661 5.736 ;
     RECT  11.477 11.952 12.661 11.976 ;
     RECT  11.477 13.152 12.697 13.608 ;
     RECT  12.661 11.712 12.769 11.976 ;
     RECT  12.697 13.056 12.769 13.608 ;
     RECT  12.229 26.16 12.769 28.728 ;
     RECT  12.445 7.44 12.913 10.056 ;
     RECT  12.913 7.392 12.997 10.056 ;
     RECT  12.769 11.712 12.997 13.608 ;
     RECT  12.661 5.616 13.021 6.168 ;
     RECT  12.125 23.28 13.045 24.936 ;
     RECT  12.769 26.16 13.045 29.256 ;
     RECT  12.157 15.552 13.057 18.456 ;
     RECT  12.589 20.16 13.057 20.184 ;
     RECT  13.057 15.552 13.093 20.184 ;
     RECT  12.085 40.896 13.093 43.944 ;
     RECT  11.987 2.592 13.129 3.048 ;
     RECT  13.045 23.28 13.165 29.256 ;
     RECT  13.093 40.896 13.165 44.472 ;
     RECT  12.161 48.384 13.201 51.384 ;
     RECT  13.129 2.304 13.208 3.048 ;
     RECT  11.987 4.128 13.208 4.536 ;
     RECT  13.021 5.616 13.208 6.408 ;
     RECT  12.997 7.392 13.208 13.608 ;
     RECT  13.093 15.504 13.208 20.184 ;
     RECT  13.165 22.752 13.208 29.256 ;
     RECT  11.729 30.336 13.208 32.328 ;
     RECT  12.197 33.552 13.208 39.72 ;
     RECT  13.165 40.896 13.208 44.664 ;
     RECT  12.161 45.696 13.208 47.208 ;
     RECT  13.201 48.24 13.208 51.384 ;
     RECT  13.208 2.148 13.312 51.852 ;
     RECT  13.312 2.304 13.504 51.582 ;
     RECT  13.504 33.504 13.565 39.624 ;
     RECT  13.504 45.984 13.601 46.008 ;
     RECT  13.565 33.504 13.667 39.096 ;
     RECT  13.504 10.752 13.673 11.784 ;
     RECT  13.673 10.752 13.853 10.776 ;
     RECT  13.504 30.336 13.961 32.52 ;
     RECT  13.504 2.304 14.033 8.808 ;
     RECT  13.504 51.12 14.105 51.192 ;
     RECT  14.033 2.304 14.213 5.592 ;
     RECT  13.504 15.216 14.249 18.456 ;
     RECT  14.213 2.304 14.437 5.544 ;
     RECT  13.504 13.296 14.497 13.608 ;
     RECT  14.249 15.504 14.497 18.456 ;
     RECT  13.504 20.64 14.537 25.896 ;
     RECT  13.673 11.76 14.569 11.784 ;
     RECT  14.497 12.816 14.569 13.608 ;
     RECT  14.537 22.512 14.573 22.776 ;
     RECT  13.961 30.72 14.641 32.52 ;
     RECT  13.667 33.504 14.641 38.76 ;
     RECT  14.497 15.504 14.677 18.744 ;
     RECT  14.677 15.504 14.713 19.224 ;
     RECT  13.504 40.608 14.713 45 ;
     RECT  14.437 4.368 14.717 5.544 ;
     RECT  14.713 15.504 14.753 19.56 ;
     RECT  14.033 6.624 14.789 8.808 ;
     RECT  14.713 40.416 14.867 45 ;
     RECT  14.789 7.968 14.897 8.808 ;
     RECT  14.569 11.76 15.037 13.608 ;
     RECT  14.537 20.64 15.041 21.144 ;
     RECT  14.641 30.72 15.113 38.76 ;
     RECT  13.504 48.24 15.145 48.936 ;
     RECT  15.113 32.16 15.149 38.76 ;
     RECT  14.867 40.608 15.149 45 ;
     RECT  14.753 16.848 15.181 19.56 ;
     RECT  15.145 47.904 15.212 48.936 ;
     RECT  13.504 26.88 15.217 29.256 ;
     RECT  14.105 51.168 15.217 51.192 ;
     RECT  14.677 10.128 15.253 10.2 ;
     RECT  15.037 11.424 15.253 13.608 ;
     RECT  14.437 2.304 15.293 3 ;
     RECT  14.789 6.624 15.361 6.84 ;
     RECT  15.253 11.376 15.361 13.608 ;
     RECT  15.217 26.208 15.361 29.256 ;
     RECT  15.113 30.72 15.361 30.84 ;
     RECT  15.149 40.896 15.361 45 ;
     RECT  15.217 51.168 15.361 51.624 ;
     RECT  14.717 4.368 15.365 5.16 ;
     RECT  15.361 26.208 15.395 30.84 ;
     RECT  15.395 26.88 15.443 30.84 ;
     RECT  15.181 16.848 15.473 19.656 ;
     RECT  15.212 47.184 15.505 48.936 ;
     RECT  14.537 24.096 15.541 25.08 ;
     RECT  15.361 40.896 15.545 45.288 ;
     RECT  15.545 42.096 15.617 45.288 ;
     RECT  15.443 29.232 15.653 30.84 ;
     RECT  15.361 11.376 15.721 14.184 ;
     RECT  14.753 15.504 15.721 15.864 ;
     RECT  14.897 7.968 15.757 8.52 ;
     RECT  15.721 11.376 15.757 15.864 ;
     RECT  15.473 16.848 15.797 19.608 ;
     RECT  15.617 42.096 15.833 45.048 ;
     RECT  14.573 22.512 15.865 22.536 ;
     RECT  15.541 24.096 15.865 25.224 ;
     RECT  15.505 47.184 15.901 49.224 ;
     RECT  15.833 42.096 15.905 43.608 ;
     RECT  15.865 22.512 15.937 25.224 ;
     RECT  15.901 47.04 15.941 49.224 ;
     RECT  15.253 9.888 15.973 10.2 ;
     RECT  15.757 11.28 15.973 15.864 ;
     RECT  15.797 16.896 15.977 19.608 ;
     RECT  15.653 29.232 15.977 29.256 ;
     RECT  15.833 44.976 15.977 45.048 ;
     RECT  15.977 18.96 16.019 19.608 ;
     RECT  15.041 20.88 16.019 21.144 ;
     RECT  15.365 4.368 16.049 4.392 ;
     RECT  15.977 16.896 16.06 17.88 ;
     RECT  15.293 2.304 16.085 2.856 ;
     RECT  15.973 9.888 16.085 15.864 ;
     RECT  15.937 22.272 16.117 25.224 ;
     RECT  16.06 16.896 16.157 17.784 ;
     RECT  15.941 48.912 16.157 49.224 ;
     RECT  15.361 6.24 16.189 6.84 ;
     RECT  15.757 7.92 16.189 8.52 ;
     RECT  16.189 6.24 16.225 8.52 ;
     RECT  15.941 47.04 16.225 47.928 ;
     RECT  16.157 49.2 16.225 49.224 ;
     RECT  16.085 14.64 16.265 15.864 ;
     RECT  15.937 38.976 16.333 39 ;
     RECT  16.265 15.456 16.337 15.864 ;
     RECT  16.225 49.2 16.337 49.272 ;
     RECT  15.149 32.16 16.373 37.608 ;
     RECT  16.373 33.264 16.396 37.608 ;
     RECT  16.225 6.24 16.409 8.76 ;
     RECT  16.157 17.04 16.409 17.784 ;
     RECT  16.409 8.736 16.441 8.76 ;
     RECT  16.085 9.888 16.441 13.608 ;
     RECT  15.653 30.816 16.441 30.84 ;
     RECT  16.373 32.16 16.441 32.184 ;
     RECT  16.117 22.272 16.445 25.656 ;
     RECT  16.225 46.752 16.477 47.928 ;
     RECT  16.019 21.072 16.481 21.144 ;
     RECT  16.085 2.592 16.517 2.856 ;
     RECT  15.361 50.88 16.549 51.624 ;
     RECT  15.977 44.976 16.553 45 ;
     RECT  16.477 46.656 16.589 47.928 ;
     RECT  16.441 30.816 16.621 32.184 ;
     RECT  15.443 26.88 16.657 27.912 ;
     RECT  16.337 49.248 16.693 49.272 ;
     RECT  16.549 50.256 16.693 51.624 ;
     RECT  16.621 30.72 16.729 32.184 ;
     RECT  16.589 46.656 16.765 47.592 ;
     RECT  15.545 40.896 16.837 41.016 ;
     RECT  16.445 23.232 16.841 25.656 ;
     RECT  16.841 23.28 16.873 25.656 ;
     RECT  16.657 26.832 16.873 27.912 ;
     RECT  16.396 33.456 16.909 37.608 ;
     RECT  16.333 38.976 16.909 39.912 ;
     RECT  15.905 42.096 16.909 42.312 ;
     RECT  15.905 43.344 16.909 43.608 ;
     RECT  16.765 46.368 16.945 47.592 ;
     RECT  16.909 33.456 16.948 39.912 ;
     RECT  16.837 40.896 16.948 41.064 ;
     RECT  16.409 6.24 17.021 7.416 ;
     RECT  16.409 17.136 17.053 17.784 ;
     RECT  16.948 33.456 17.053 41.064 ;
     RECT  16.909 42.096 17.053 43.608 ;
     RECT  17.053 33.456 17.093 43.608 ;
     RECT  17.093 39.552 17.123 43.608 ;
     RECT  17.053 17.136 17.125 17.976 ;
     RECT  16.981 20.928 17.197 20.952 ;
     RECT  17.125 17.136 17.219 18.216 ;
     RECT  16.019 19.344 17.219 19.608 ;
     RECT  16.441 8.736 17.237 13.608 ;
     RECT  16.873 23.28 17.237 27.912 ;
     RECT  17.093 33.456 17.237 38.52 ;
     RECT  17.219 19.488 17.26 19.608 ;
     RECT  17.237 38.16 17.273 38.52 ;
     RECT  17.219 17.136 17.309 17.976 ;
     RECT  16.729 30.288 17.317 32.184 ;
     RECT  17.123 40.944 17.345 43.608 ;
     RECT  17.237 33.456 17.363 37.128 ;
     RECT  16.333 4.512 17.372 4.536 ;
     RECT  16.517 2.592 17.377 2.712 ;
     RECT  16.337 15.456 17.377 15.768 ;
     RECT  17.197 20.832 17.381 20.952 ;
     RECT  17.017 22.224 17.521 22.248 ;
     RECT  17.372 4.224 17.557 4.536 ;
     RECT  17.317 30.144 17.593 32.184 ;
     RECT  16.693 49.248 17.593 51.624 ;
     RECT  17.237 8.736 17.597 10.2 ;
     RECT  17.237 11.856 17.605 13.608 ;
     RECT  17.377 14.784 17.605 15.768 ;
     RECT  17.345 42.576 17.605 43.608 ;
     RECT  17.521 44.88 17.605 44.904 ;
     RECT  17.597 9.6 17.633 10.2 ;
     RECT  17.605 11.856 17.665 15.768 ;
     RECT  17.309 17.136 17.665 17.352 ;
     RECT  17.377 2.496 17.701 2.712 ;
     RECT  17.605 42.576 17.701 44.904 ;
     RECT  16.945 45.936 17.701 47.592 ;
     RECT  17.237 24.24 18.061 27.912 ;
     RECT  17.273 38.208 18.061 38.52 ;
     RECT  17.123 39.552 18.061 39.912 ;
     RECT  17.021 6.24 18.133 7.224 ;
     RECT  17.845 8.448 18.133 8.472 ;
     RECT  17.593 29.76 18.205 32.184 ;
     RECT  18.061 24.24 18.277 28.44 ;
     RECT  17.593 48.96 18.349 51.624 ;
     RECT  17.363 35.328 18.421 37.128 ;
     RECT  18.061 38.208 18.421 39.912 ;
     RECT  17.345 40.944 18.421 41.544 ;
     RECT  18.349 48.816 18.421 51.624 ;
     RECT  18.421 35.328 18.429 41.544 ;
     RECT  17.701 42.576 18.429 47.592 ;
     RECT  17.363 33.456 18.457 34.296 ;
     RECT  18.429 35.328 18.457 47.592 ;
     RECT  18.421 48.72 18.493 51.624 ;
     RECT  18.277 24.24 18.529 28.776 ;
     RECT  17.701 2.496 18.608 2.856 ;
     RECT  17.557 4.128 18.608 4.536 ;
     RECT  18.133 6.24 18.608 8.472 ;
     RECT  17.633 10.176 18.608 10.2 ;
     RECT  17.665 11.856 18.608 17.352 ;
     RECT  17.26 19.584 18.608 19.608 ;
     RECT  17.381 20.928 18.608 20.952 ;
     RECT  17.521 22.032 18.608 22.248 ;
     RECT  18.529 24.096 18.608 28.776 ;
     RECT  18.205 29.76 18.608 32.328 ;
     RECT  18.457 33.456 18.608 47.592 ;
     RECT  18.493 48.672 18.608 51.624 ;
     RECT  18.608 2.148 18.712 51.852 ;
     RECT  18.712 2.418 18.904 51.582 ;
     RECT  18.904 12.48 18.929 16.92 ;
     RECT  18.929 12.48 18.965 16.776 ;
     RECT  18.904 45.264 19.001 46.872 ;
     RECT  18.904 30.336 19.037 33.576 ;
     RECT  18.904 5.712 19.073 9 ;
     RECT  18.904 10.176 19.073 11.496 ;
     RECT  19.037 30.336 19.181 33.096 ;
     RECT  18.904 34.992 19.181 43.608 ;
     RECT  19.073 10.176 19.361 11.064 ;
     RECT  19.361 10.176 19.433 10.92 ;
     RECT  18.904 19.056 19.433 20.952 ;
     RECT  19.001 45.264 19.433 45.288 ;
     RECT  18.904 47.856 19.433 49.512 ;
     RECT  18.904 50.64 19.497 50.76 ;
     RECT  18.965 12.768 19.541 16.776 ;
     RECT  19.181 34.992 19.649 43.176 ;
     RECT  19.433 10.176 19.721 10.872 ;
     RECT  19.181 33.072 19.757 33.096 ;
     RECT  19.433 47.856 19.757 49.416 ;
     RECT  18.904 22.368 19.865 22.488 ;
     RECT  18.904 23.568 19.865 24.12 ;
     RECT  18.904 25.104 19.897 25.224 ;
     RECT  18.904 26.304 19.897 29.208 ;
     RECT  19.073 5.712 20.041 6.888 ;
     RECT  19.649 34.992 20.044 42.744 ;
     RECT  18.904 3.408 20.053 4.152 ;
     RECT  19.897 25.104 20.261 29.208 ;
     RECT  20.261 25.2 20.365 29.208 ;
     RECT  19.181 30.336 20.365 31.512 ;
     RECT  19.497 50.736 20.405 50.76 ;
     RECT  20.365 25.2 20.477 31.512 ;
     RECT  19.001 46.368 20.509 46.872 ;
     RECT  20.477 25.392 20.513 31.512 ;
     RECT  19.541 12.816 20.545 16.776 ;
     RECT  20.053 3.408 20.549 4.296 ;
     RECT  20.513 25.584 20.549 31.512 ;
     RECT  20.545 12.816 20.585 17.064 ;
     RECT  20.585 15.744 20.684 17.064 ;
     RECT  19.721 10.176 20.725 10.392 ;
     RECT  20.684 15.744 20.801 17.112 ;
     RECT  20.041 5.712 20.833 6.984 ;
     RECT  19.073 8.208 20.833 8.232 ;
     RECT  19.433 19.056 20.833 20.376 ;
     RECT  20.437 22.176 20.833 22.2 ;
     RECT  20.549 27.216 20.833 31.512 ;
     RECT  20.044 38.976 20.833 42.744 ;
     RECT  20.725 10.176 20.837 10.536 ;
     RECT  19.757 48.672 20.837 49.416 ;
     RECT  20.833 5.712 20.873 8.232 ;
     RECT  20.833 38.976 20.873 43.704 ;
     RECT  20.837 10.176 20.909 10.2 ;
     RECT  20.044 34.992 20.909 37.8 ;
     RECT  20.801 16.704 20.941 17.112 ;
     RECT  20.585 12.816 21.013 14.52 ;
     RECT  20.873 42.672 21.085 43.704 ;
     RECT  20.509 44.928 21.085 44.952 ;
     RECT  20.509 46.368 21.085 46.92 ;
     RECT  20.837 48.672 21.085 49.176 ;
     RECT  21.013 11.856 21.155 14.52 ;
     RECT  21.085 42.672 21.155 46.92 ;
     RECT  20.977 50.208 21.161 50.232 ;
     RECT  21.121 8.832 21.193 8.856 ;
     RECT  21.155 44.448 21.196 46.92 ;
     RECT  20.873 5.712 21.197 7.608 ;
     RECT  21.196 44.544 21.197 46.92 ;
     RECT  20.833 27.216 21.229 32.04 ;
     RECT  19.865 23.568 21.26 23.64 ;
     RECT  21.26 23.568 21.269 23.928 ;
     RECT  21.197 6.816 21.377 7.608 ;
     RECT  20.909 35.328 21.409 37.8 ;
     RECT  20.873 38.976 21.409 41.64 ;
     RECT  21.193 8.832 21.413 9.048 ;
     RECT  20.833 19.056 21.449 22.2 ;
     RECT  21.155 42.672 21.485 43.32 ;
     RECT  21.155 12.048 21.589 14.52 ;
     RECT  20.941 16.704 21.589 17.208 ;
     RECT  21.229 27.216 21.589 33 ;
     RECT  21.157 34.08 21.589 34.104 ;
     RECT  21.589 26.88 21.625 34.104 ;
     RECT  21.589 12.048 21.629 14.904 ;
     RECT  21.589 16.704 21.629 17.4 ;
     RECT  21.449 21.312 21.637 22.2 ;
     RECT  21.269 23.904 21.637 23.928 ;
     RECT  20.549 25.584 21.637 25.608 ;
     RECT  21.625 26.784 21.637 34.104 ;
     RECT  21.637 23.904 21.683 24.12 ;
     RECT  21.637 25.584 21.737 34.104 ;
     RECT  21.629 16.944 21.805 17.4 ;
     RECT  21.409 35.328 21.845 41.64 ;
     RECT  21.845 35.424 21.877 41.64 ;
     RECT  21.485 42.672 21.877 42.744 ;
     RECT  21.085 48.528 21.881 49.176 ;
     RECT  20.549 4.272 21.985 4.296 ;
     RECT  21.197 5.712 21.985 5.736 ;
     RECT  21.737 26.496 21.985 34.104 ;
     RECT  21.197 44.544 22.025 46.392 ;
     RECT  21.805 16.944 22.061 17.448 ;
     RECT  21.877 35.424 22.061 42.744 ;
     RECT  22.025 46.368 22.115 46.392 ;
     RECT  22.028 47.472 22.115 47.496 ;
     RECT  22.061 16.944 22.205 17.4 ;
     RECT  22.025 44.544 22.205 45.192 ;
     RECT  21.985 26.496 22.211 34.248 ;
     RECT  21.985 4.272 22.313 5.736 ;
     RECT  22.313 4.272 22.349 5.16 ;
     RECT  22.061 35.424 22.349 39.864 ;
     RECT  21.377 6.816 22.385 7.512 ;
     RECT  22.349 35.424 22.457 37.608 ;
     RECT  22.205 16.944 22.493 17.352 ;
     RECT  21.637 21.312 22.525 22.632 ;
     RECT  21.409 51.36 22.561 51.384 ;
     RECT  22.349 4.464 22.573 5.16 ;
     RECT  21.449 19.056 22.597 19.656 ;
     RECT  22.211 26.496 22.637 34.152 ;
     RECT  22.597 19.056 22.705 20.088 ;
     RECT  22.493 16.944 22.709 17.016 ;
     RECT  21.629 12.816 22.741 14.904 ;
     RECT  22.381 10.992 22.777 11.016 ;
     RECT  22.741 12.768 22.777 14.904 ;
     RECT  22.093 25.152 22.781 25.176 ;
     RECT  22.777 10.176 22.787 11.016 ;
     RECT  22.705 19.056 22.789 20.184 ;
     RECT  22.561 51.12 22.813 51.384 ;
     RECT  21.409 2.784 22.889 2.808 ;
     RECT  22.457 35.424 22.961 37.368 ;
     RECT  21.881 48.528 22.993 49.128 ;
     RECT  22.061 40.992 22.997 42.744 ;
     RECT  21.413 9.024 23.029 9.048 ;
     RECT  22.787 10.176 23.029 10.392 ;
     RECT  22.813 50.832 23.101 51.384 ;
     RECT  23.029 9.024 23.125 10.392 ;
     RECT  22.997 40.992 23.125 42.648 ;
     RECT  23.125 40.896 23.137 42.648 ;
     RECT  22.525 21.312 23.279 22.776 ;
     RECT  21.683 24.096 23.279 24.12 ;
     RECT  22.637 26.496 23.281 33.96 ;
     RECT  22.349 38.736 23.281 39.864 ;
     RECT  23.137 40.848 23.281 42.648 ;
     RECT  22.385 6.816 23.353 6.84 ;
     RECT  22.777 12.48 23.389 14.904 ;
     RECT  22.789 18.384 23.389 20.184 ;
     RECT  23.279 21.312 23.389 24.12 ;
     RECT  23.125 8.832 23.461 10.392 ;
     RECT  23.389 11.952 23.461 14.904 ;
     RECT  23.353 43.92 23.461 43.944 ;
     RECT  22.205 45.168 23.461 45.192 ;
     RECT  22.993 48.528 23.468 49.224 ;
     RECT  23.468 48.432 23.509 49.224 ;
     RECT  23.101 50.256 23.509 51.384 ;
     RECT  23.533 3.312 23.569 3.336 ;
     RECT  22.573 4.464 23.569 4.872 ;
     RECT  23.281 38.736 23.641 42.648 ;
     RECT  23.353 6.816 23.677 7.464 ;
     RECT  22.381 47.088 23.713 47.112 ;
     RECT  23.509 48.432 23.713 51.384 ;
     RECT  23.461 11.952 23.785 15.864 ;
     RECT  22.709 16.992 23.785 17.016 ;
     RECT  23.281 26.352 23.785 33.96 ;
     RECT  23.713 2.256 24.008 2.28 ;
     RECT  23.569 3.312 24.008 4.872 ;
     RECT  23.677 6.288 24.008 7.464 ;
     RECT  23.461 8.496 24.008 10.392 ;
     RECT  23.785 11.952 24.008 17.016 ;
     RECT  23.389 18.384 24.008 24.12 ;
     RECT  23.785 26.256 24.008 33.96 ;
     RECT  22.961 36.096 24.008 37.368 ;
     RECT  23.641 38.688 24.008 42.648 ;
     RECT  23.461 43.92 24.008 45.192 ;
     RECT  23.713 47.088 24.008 51.384 ;
     RECT  24.008 2.148 24.112 51.852 ;
     RECT  24.112 2.256 24.304 51.582 ;
     RECT  24.304 50.832 24.329 51.336 ;
     RECT  24.304 5.088 24.419 10.872 ;
     RECT  24.304 11.952 24.467 20.088 ;
     RECT  24.304 28.992 24.473 34.392 ;
     RECT  24.473 29.04 24.509 34.392 ;
     RECT  24.304 25.584 24.515 27.672 ;
     RECT  24.467 14.736 24.545 20.088 ;
     RECT  24.304 42.768 24.545 42.792 ;
     RECT  24.419 8.304 24.617 10.872 ;
     RECT  24.419 5.088 24.689 7.224 ;
     RECT  24.515 26.256 24.689 27.672 ;
     RECT  24.304 43.872 24.689 47.88 ;
     RECT  24.304 49.008 24.689 49.56 ;
     RECT  24.304 2.256 24.833 4.008 ;
     RECT  24.509 34.176 24.833 34.392 ;
     RECT  24.545 15.744 24.905 20.088 ;
     RECT  24.905 15.744 24.941 17.16 ;
     RECT  24.689 47.856 24.941 47.88 ;
     RECT  24.545 14.736 24.969 14.76 ;
     RECT  24.905 18.144 25.013 20.088 ;
     RECT  24.467 11.952 25.043 13.656 ;
     RECT  24.689 5.088 25.085 5.256 ;
     RECT  24.304 21.168 25.085 24.504 ;
     RECT  24.941 15.744 25.091 17.016 ;
     RECT  25.085 21.168 25.091 23.4 ;
     RECT  25.091 21.168 25.121 22.2 ;
     RECT  24.689 26.256 25.121 26.424 ;
     RECT  24.833 2.736 25.157 4.008 ;
     RECT  25.091 15.744 25.157 16.344 ;
     RECT  24.617 8.304 25.193 10.2 ;
     RECT  25.013 18.96 25.265 20.088 ;
     RECT  25.091 23.376 25.265 23.4 ;
     RECT  24.509 29.04 25.301 33.096 ;
     RECT  25.193 8.304 25.409 10.152 ;
     RECT  24.329 51.12 25.409 51.336 ;
     RECT  25.409 8.304 25.441 9.048 ;
     RECT  24.689 43.872 25.513 46.776 ;
     RECT  25.043 11.952 25.517 13.464 ;
     RECT  24.689 6.24 25.549 7.224 ;
     RECT  25.441 8.208 25.549 9.048 ;
     RECT  24.689 27.408 25.549 27.672 ;
     RECT  25.301 29.04 25.549 32.856 ;
     RECT  24.304 35.472 25.549 40.92 ;
     RECT  25.513 42.912 25.697 46.776 ;
     RECT  25.549 6.24 25.733 9.048 ;
     RECT  25.693 47.904 25.765 47.928 ;
     RECT  24.689 49.008 25.765 49.512 ;
     RECT  25.157 3.072 25.801 4.008 ;
     RECT  25.697 43.536 25.801 46.776 ;
     RECT  25.265 19.632 25.805 20.088 ;
     RECT  24.833 34.176 25.841 34.2 ;
     RECT  25.733 6.24 25.873 7.992 ;
     RECT  25.157 15.984 25.877 16.344 ;
     RECT  25.765 47.904 25.877 50.04 ;
     RECT  25.801 43.536 25.913 46.92 ;
     RECT  25.121 21.168 25.945 22.008 ;
     RECT  25.549 35.472 25.955 41.544 ;
     RECT  25.877 49.488 25.981 50.04 ;
     RECT  25.409 51.12 25.981 51.192 ;
     RECT  25.913 43.536 25.996 45.72 ;
     RECT  25.877 15.984 26.021 16.104 ;
     RECT  25.981 49.488 26.021 51.192 ;
     RECT  25.121 26.352 26.053 26.424 ;
     RECT  25.549 27.408 26.053 32.856 ;
     RECT  25.733 8.976 26.165 9.048 ;
     RECT  26.021 50.016 26.165 51.192 ;
     RECT  25.955 35.472 26.201 40.824 ;
     RECT  26.201 37.92 26.209 40.824 ;
     RECT  25.996 43.872 26.237 45.72 ;
     RECT  25.873 5.472 26.273 7.992 ;
     RECT  25.409 10.128 26.348 10.152 ;
     RECT  26.201 35.472 26.348 36.84 ;
     RECT  26.209 37.92 26.381 39.384 ;
     RECT  25.913 46.704 26.381 46.92 ;
     RECT  26.348 10.128 26.389 10.488 ;
     RECT  25.945 20.928 26.417 22.008 ;
     RECT  26.348 34.512 26.435 36.84 ;
     RECT  26.273 5.472 26.453 7.464 ;
     RECT  26.233 17.568 26.453 17.592 ;
     RECT  25.085 24.48 26.485 24.504 ;
     RECT  26.053 26.352 26.485 32.856 ;
     RECT  26.165 9.024 26.521 9.048 ;
     RECT  26.389 10.128 26.521 11.208 ;
     RECT  25.801 3.072 26.525 4.488 ;
     RECT  26.021 15.984 26.525 16.008 ;
     RECT  26.485 24.144 26.525 24.504 ;
     RECT  26.485 26.208 26.525 32.856 ;
     RECT  25.805 19.632 26.557 19.896 ;
     RECT  26.525 3.072 26.561 3.72 ;
     RECT  26.381 46.896 26.665 46.92 ;
     RECT  25.877 47.904 26.665 47.928 ;
     RECT  25.517 12.192 26.693 13.464 ;
     RECT  26.165 50.016 26.705 50.904 ;
     RECT  26.665 46.896 26.777 47.928 ;
     RECT  26.521 9.024 26.813 11.208 ;
     RECT  26.435 35.328 26.813 36.84 ;
     RECT  26.381 38.256 26.849 39.384 ;
     RECT  26.525 24.144 26.881 24.168 ;
     RECT  26.525 27.408 26.881 32.856 ;
     RECT  26.813 10.08 26.884 11.208 ;
     RECT  26.693 12.192 26.884 13.704 ;
     RECT  26.557 19.344 26.885 19.896 ;
     RECT  26.881 27.408 26.885 33 ;
     RECT  26.813 9.024 26.921 9.048 ;
     RECT  26.885 19.344 26.957 19.848 ;
     RECT  26.885 32.88 27.029 33 ;
     RECT  26.849 38.256 27.029 38.76 ;
     RECT  26.209 40.416 27.061 40.824 ;
     RECT  26.777 46.896 27.065 47.304 ;
     RECT  26.705 50.016 27.241 50.424 ;
     RECT  27.061 40.416 27.313 40.968 ;
     RECT  26.341 42.192 27.313 42.216 ;
     RECT  26.237 43.872 27.349 45.144 ;
     RECT  27.241 49.536 27.349 50.424 ;
     RECT  26.525 26.208 27.421 26.232 ;
     RECT  26.417 21.648 27.493 22.008 ;
     RECT  27.313 40.416 27.493 42.216 ;
     RECT  27.349 43.344 27.493 45.144 ;
     RECT  27.457 17.616 27.541 17.64 ;
     RECT  26.813 35.664 27.565 36.84 ;
     RECT  27.029 38.256 27.565 38.28 ;
     RECT  27.349 48.768 27.569 50.424 ;
     RECT  27.493 21.312 27.601 22.2 ;
     RECT  26.881 23.328 27.601 24.168 ;
     RECT  26.884 10.08 27.605 13.704 ;
     RECT  27.541 16.944 27.628 17.64 ;
     RECT  26.561 3.408 27.637 3.72 ;
     RECT  26.453 5.472 27.637 7.224 ;
     RECT  27.605 10.704 27.685 13.704 ;
     RECT  27.349 14.784 27.685 14.808 ;
     RECT  27.565 35.664 27.713 38.28 ;
     RECT  27.637 3.408 27.745 7.224 ;
     RECT  26.885 27.408 27.821 31.752 ;
     RECT  27.745 2.784 27.829 7.224 ;
     RECT  27.421 26.064 27.853 26.232 ;
     RECT  27.821 27.408 27.853 28.872 ;
     RECT  27.713 35.664 27.853 38.184 ;
     RECT  27.065 46.896 27.853 47.016 ;
     RECT  27.685 10.704 27.875 14.808 ;
     RECT  26.957 19.824 27.889 19.848 ;
     RECT  27.601 21.312 27.889 24.168 ;
     RECT  27.821 30 27.889 31.752 ;
     RECT  27.029 32.88 27.889 32.904 ;
     RECT  27.875 12.528 27.923 13.176 ;
     RECT  27.529 8.784 28.037 8.808 ;
     RECT  27.569 48.768 28.145 49.56 ;
     RECT  27.829 2.784 28.181 7.368 ;
     RECT  27.709 18.768 28.213 18.792 ;
     RECT  27.889 19.824 28.213 24.168 ;
     RECT  27.889 30 28.213 32.904 ;
     RECT  28.145 48.768 28.249 49.32 ;
     RECT  27.875 14.256 28.253 14.808 ;
     RECT  27.853 25.248 28.259 28.872 ;
     RECT  28.253 14.256 28.325 14.28 ;
     RECT  28.259 25.248 28.325 28.152 ;
     RECT  28.213 18.768 28.361 24.168 ;
     RECT  28.325 25.248 28.393 27.672 ;
     RECT  28.181 2.832 28.397 7.368 ;
     RECT  28.501 50.976 28.609 51 ;
     RECT  28.397 4.704 28.645 7.368 ;
     RECT  27.875 10.704 28.645 11.4 ;
     RECT  28.645 10.272 28.681 11.4 ;
     RECT  28.361 18.768 28.789 23.928 ;
     RECT  28.681 9.6 28.897 11.4 ;
     RECT  27.923 12.528 28.897 13.128 ;
     RECT  27.493 40.416 28.933 45.144 ;
     RECT  27.853 46.752 28.969 47.016 ;
     RECT  28.249 48.192 28.969 49.32 ;
     RECT  28.213 30 28.997 33.672 ;
     RECT  27.853 34.896 28.997 38.184 ;
     RECT  27.628 17.184 29.036 17.64 ;
     RECT  28.789 18.624 29.036 23.928 ;
     RECT  28.249 39.216 29.041 39.24 ;
     RECT  28.933 40.416 29.041 45.768 ;
     RECT  28.609 50.928 29.041 51 ;
     RECT  29.041 39.216 29.149 45.768 ;
     RECT  28.969 46.752 29.149 49.32 ;
     RECT  29.257 15.216 29.269 15.24 ;
     RECT  28.393 25.2 29.269 27.672 ;
     RECT  28.645 4.704 29.329 8.328 ;
     RECT  28.397 2.832 29.408 3.72 ;
     RECT  29.329 4.704 29.408 8.568 ;
     RECT  28.897 9.6 29.408 13.128 ;
     RECT  29.269 15.216 29.408 15.528 ;
     RECT  29.036 17.184 29.408 23.928 ;
     RECT  29.269 25.056 29.408 27.672 ;
     RECT  28.997 30 29.408 38.184 ;
     RECT  29.149 39.216 29.408 49.32 ;
     RECT  29.041 50.832 29.408 51 ;
     RECT  29.408 2.148 29.512 51.852 ;
     RECT  29.512 2.418 29.704 51.582 ;
     RECT  29.704 32.256 29.765 33.672 ;
     RECT  29.704 44.448 29.765 50.952 ;
     RECT  29.765 32.256 29.837 33 ;
     RECT  29.704 16.56 29.873 23.592 ;
     RECT  29.704 5.472 29.945 13.704 ;
     RECT  29.704 15.216 29.981 15.48 ;
     RECT  29.945 5.472 30.035 11.4 ;
     RECT  29.704 34.752 30.089 34.776 ;
     RECT  29.765 44.448 30.233 48.936 ;
     RECT  29.945 12.528 30.269 13.704 ;
     RECT  29.873 19.008 30.275 23.592 ;
     RECT  30.233 44.448 30.275 45.72 ;
     RECT  29.704 24.72 30.305 25.752 ;
     RECT  30.269 12.528 30.341 13.56 ;
     RECT  29.873 16.56 30.377 17.976 ;
     RECT  30.275 20.112 30.413 23.592 ;
     RECT  30.035 7.968 30.515 11.4 ;
     RECT  30.515 7.968 30.521 8.088 ;
     RECT  29.837 32.304 30.557 33 ;
     RECT  29.704 36 30.629 43.32 ;
     RECT  30.233 46.752 30.841 48.936 ;
     RECT  29.765 49.968 30.841 50.952 ;
     RECT  30.377 16.56 30.845 17.688 ;
     RECT  29.704 27.12 30.845 28.152 ;
     RECT  30.629 36 30.869 43.128 ;
     RECT  30.845 16.56 30.877 17.64 ;
     RECT  30.557 32.496 30.877 33 ;
     RECT  30.841 46.752 30.877 50.952 ;
     RECT  29.704 2.832 30.881 2.856 ;
     RECT  30.413 20.112 30.899 21.672 ;
     RECT  30.869 35.856 30.913 43.128 ;
     RECT  30.899 20.112 30.94 21.144 ;
     RECT  29.704 29.616 31.021 31.272 ;
     RECT  30.877 46.752 31.025 51.24 ;
     RECT  30.305 25.056 31.045 25.752 ;
     RECT  30.845 27.12 31.045 27.912 ;
     RECT  31.021 28.944 31.061 31.272 ;
     RECT  31.045 25.056 31.097 27.912 ;
     RECT  29.981 15.456 31.205 15.48 ;
     RECT  30.275 19.008 31.237 19.032 ;
     RECT  30.275 44.448 31.309 45.576 ;
     RECT  31.025 46.752 31.309 49.56 ;
     RECT  30.035 5.472 31.385 6.984 ;
     RECT  30.413 22.752 31.421 23.592 ;
     RECT  30.515 9.072 31.436 11.4 ;
     RECT  30.341 13.104 31.477 13.56 ;
     RECT  31.097 25.584 31.493 27.912 ;
     RECT  31.436 9.072 31.523 11.928 ;
     RECT  29.704 4.368 31.561 4.392 ;
     RECT  30.94 20.112 31.565 20.184 ;
     RECT  31.237 34.176 31.597 34.2 ;
     RECT  30.913 35.328 31.597 43.128 ;
     RECT  31.309 44.448 31.597 49.56 ;
     RECT  31.477 13.008 31.601 14.088 ;
     RECT  31.597 34.176 31.601 49.56 ;
     RECT  30.877 32.496 31.633 33.144 ;
     RECT  31.601 34.176 31.633 35.352 ;
     RECT  31.237 18.816 31.637 19.032 ;
     RECT  31.385 6.864 31.669 6.984 ;
     RECT  30.521 8.064 31.669 8.088 ;
     RECT  31.637 18.816 31.777 18.84 ;
     RECT  30.877 16.512 31.817 17.64 ;
     RECT  31.777 18.72 31.853 18.84 ;
     RECT  31.561 3.792 31.861 4.392 ;
     RECT  31.385 5.472 31.861 5.496 ;
     RECT  31.669 6.864 31.861 8.088 ;
     RECT  31.523 9.072 31.861 10.872 ;
     RECT  31.861 3.792 31.907 5.496 ;
     RECT  31.493 25.584 31.925 27.672 ;
     RECT  31.061 28.944 31.925 29.112 ;
     RECT  31.861 6.864 31.948 10.872 ;
     RECT  31.025 50.64 31.993 51.24 ;
     RECT  31.907 5.136 31.997 5.496 ;
     RECT  31.993 50.64 32.029 51.384 ;
     RECT  31.421 23.136 32.065 23.592 ;
     RECT  31.948 6.864 32.069 7.464 ;
     RECT  31.925 28.992 32.069 29.112 ;
     RECT  31.948 9.12 32.141 10.872 ;
     RECT  31.817 16.512 32.141 17.208 ;
     RECT  31.601 13.008 32.317 13.128 ;
     RECT  32.069 29.088 32.353 29.112 ;
     RECT  31.061 30.336 32.353 31.272 ;
     RECT  31.633 32.496 32.429 35.352 ;
     RECT  32.065 23.136 32.437 24.552 ;
     RECT  31.925 25.584 32.437 26.28 ;
     RECT  31.601 36.336 32.461 49.56 ;
     RECT  32.029 50.64 32.461 51.48 ;
     RECT  32.429 32.928 32.465 35.352 ;
     RECT  32.069 6.96 32.537 7.464 ;
     RECT  32.465 33.216 32.537 35.352 ;
     RECT  32.353 29.088 32.645 31.272 ;
     RECT  32.645 30.336 32.713 31.272 ;
     RECT  32.141 10.128 32.753 10.872 ;
     RECT  31.565 20.112 32.785 20.136 ;
     RECT  32.713 30.336 32.785 31.368 ;
     RECT  32.317 12.48 32.789 13.128 ;
     RECT  32.437 23.136 32.789 26.28 ;
     RECT  32.569 14.976 32.821 15 ;
     RECT  32.785 20.112 32.893 20.376 ;
     RECT  32.753 10.176 32.965 10.872 ;
     RECT  31.925 27.648 32.965 27.672 ;
     RECT  32.965 10.176 33.011 11.448 ;
     RECT  32.965 27.312 33.061 27.672 ;
     RECT  31.907 3.792 33.113 3.816 ;
     RECT  32.461 36.336 33.113 51.48 ;
     RECT  32.141 17.184 33.145 17.208 ;
     RECT  32.789 26.256 33.145 26.28 ;
     RECT  33.061 27.312 33.145 27.96 ;
     RECT  33.113 40.032 33.185 51.48 ;
     RECT  32.893 20.112 33.205 21.144 ;
     RECT  33.185 40.032 33.221 51.384 ;
     RECT  33.145 26.256 33.257 27.96 ;
     RECT  33.113 36.336 33.257 38.952 ;
     RECT  31.997 5.424 33.289 5.496 ;
     RECT  33.205 20.112 33.292 21.672 ;
     RECT  33.257 26.256 33.299 27.672 ;
     RECT  33.257 36.336 33.361 38.568 ;
     RECT  32.821 14.976 33.397 15.192 ;
     RECT  33.361 35.904 33.401 38.568 ;
     RECT  33.011 11.424 33.437 11.448 ;
     RECT  33.401 35.904 33.445 38.472 ;
     RECT  32.789 23.136 33.473 24.552 ;
     RECT  32.537 7.44 33.577 7.464 ;
     RECT  31.853 18.72 33.577 18.744 ;
     RECT  32.789 12.864 33.613 13.128 ;
     RECT  32.785 30.336 33.613 31.8 ;
     RECT  32.537 33.216 33.613 34.92 ;
     RECT  33.505 2.832 33.637 2.856 ;
     RECT  33.469 3.936 33.637 3.96 ;
     RECT  33.289 5.424 33.637 5.592 ;
     RECT  33.577 18.72 33.661 18.84 ;
     RECT  33.661 18.72 33.676 18.744 ;
     RECT  33.637 2.592 33.683 2.856 ;
     RECT  33.637 3.936 33.683 5.592 ;
     RECT  33.299 26.256 33.689 26.28 ;
     RECT  33.605 53.04 33.689 53.064 ;
     RECT  33.577 7.2 33.829 7.464 ;
     RECT  33.683 4.56 33.833 5.592 ;
     RECT  33.829 7.2 34.009 7.992 ;
     RECT  33.613 12.864 34.009 13.608 ;
     RECT  34.009 12.528 34.161 13.608 ;
     RECT  33.397 14.976 34.161 16.008 ;
     RECT  34.117 26.064 34.189 26.088 ;
     RECT  32.645 29.088 34.213 29.256 ;
     RECT  34.161 12.528 34.22 16.008 ;
     RECT  33.145 17.184 34.22 17.64 ;
     RECT  33.292 20.112 34.261 21.192 ;
     RECT  34.213 28.8 34.297 29.256 ;
     RECT  33.613 30.24 34.297 31.8 ;
     RECT  34.268 53.904 34.355 53.928 ;
     RECT  34.297 28.8 34.549 31.8 ;
     RECT  33.613 33.024 34.585 34.92 ;
     RECT  33.445 36.528 34.604 38.472 ;
     RECT  34.604 36.528 34.621 38.568 ;
     RECT  34.621 36.528 34.629 38.712 ;
     RECT  33.221 40.032 34.629 51.096 ;
     RECT  34.549 28.8 34.693 31.944 ;
     RECT  34.585 33.024 34.693 35.352 ;
     RECT  33.299 27.312 34.729 27.672 ;
     RECT  34.693 28.8 34.729 35.352 ;
     RECT  34.729 27.312 34.765 35.352 ;
     RECT  34.629 36.528 34.765 51.096 ;
     RECT  33.683 2.592 34.808 2.808 ;
     RECT  33.833 4.704 34.808 5.592 ;
     RECT  34.009 6.816 34.808 7.992 ;
     RECT  33.788 8.976 34.808 9 ;
     RECT  33.011 10.368 34.808 10.392 ;
     RECT  34.22 12.528 34.808 17.64 ;
     RECT  34.261 19.968 34.808 21.192 ;
     RECT  33.473 23.136 34.808 23.592 ;
     RECT  34.189 25.824 34.808 26.088 ;
     RECT  34.765 27.312 34.808 51.096 ;
     RECT  34.808 2.148 34.912 51.852 ;
     RECT  34.912 2.418 35.104 51.816 ;
     RECT  35.104 2.592 35.165 5.592 ;
     RECT  35.104 36.288 35.165 51.816 ;
     RECT  35.104 22.752 35.219 23.976 ;
     RECT  35.165 2.688 35.345 5.592 ;
     RECT  35.165 39.792 35.363 51.816 ;
     RECT  35.345 4.704 35.381 5.592 ;
     RECT  35.104 6.816 35.381 15.864 ;
     RECT  35.165 36.288 35.381 38.472 ;
     RECT  35.381 14.4 35.417 15.864 ;
     RECT  35.104 29.184 35.417 34.872 ;
     RECT  35.104 16.848 35.813 18.744 ;
     RECT  35.813 16.848 35.849 17.64 ;
     RECT  35.104 27.456 35.849 28.2 ;
     RECT  35.849 16.848 35.885 17.304 ;
     RECT  35.417 29.184 35.885 31.416 ;
     RECT  35.381 6.816 35.921 13.176 ;
     RECT  35.417 15.456 35.921 15.864 ;
     RECT  35.104 25.056 35.939 26.232 ;
     RECT  35.921 6.816 36.097 12.936 ;
     RECT  35.885 29.184 36.131 29.208 ;
     RECT  35.381 5.136 36.133 5.592 ;
     RECT  36.097 6.768 36.133 12.936 ;
     RECT  36.133 5.136 36.22 12.936 ;
     RECT  36.22 5.136 36.245 5.16 ;
     RECT  35.417 32.544 36.245 34.872 ;
     RECT  36.22 6.24 36.275 12.936 ;
     RECT  35.381 36.288 36.281 38.184 ;
     RECT  35.363 50.832 36.281 51.816 ;
     RECT  36.275 6.672 36.317 12.936 ;
     RECT  35.921 15.792 36.353 15.864 ;
     RECT  36.245 32.736 36.389 34.872 ;
     RECT  36.281 50.832 36.421 51.096 ;
     RECT  35.219 23.568 36.469 23.592 ;
     RECT  35.363 39.792 36.469 49.608 ;
     RECT  36.421 50.784 36.469 51.096 ;
     RECT  35.939 25.056 36.515 25.08 ;
     RECT  36.281 36.816 36.565 38.184 ;
     RECT  36.565 36.816 36.569 38.712 ;
     RECT  35.345 2.688 36.601 3.384 ;
     RECT  35.417 14.4 36.601 14.424 ;
     RECT  36.317 9.36 36.641 12.936 ;
     RECT  35.939 26.208 36.641 26.232 ;
     RECT  36.317 6.672 36.659 8.232 ;
     RECT  36.469 39.792 36.677 51.096 ;
     RECT  35.104 20.112 36.709 21.672 ;
     RECT  36.569 37.296 36.709 38.712 ;
     RECT  36.677 39.792 36.709 44.424 ;
     RECT  36.389 32.736 36.749 34.2 ;
     RECT  36.709 19.824 36.781 22.248 ;
     RECT  36.469 23.568 36.781 23.832 ;
     RECT  36.677 45.408 36.785 51.096 ;
     RECT  36.709 37.296 36.821 44.424 ;
     RECT  36.601 14.4 36.857 14.808 ;
     RECT  35.813 18.72 36.889 18.744 ;
     RECT  35.885 17.088 36.925 17.304 ;
     RECT  36.889 18.72 36.929 18.84 ;
     RECT  36.821 37.296 36.929 41.112 ;
     RECT  36.929 18.816 36.997 18.84 ;
     RECT  36.781 19.824 36.997 23.832 ;
     RECT  36.821 42.144 37.001 44.424 ;
     RECT  36.997 18.816 37.043 23.832 ;
     RECT  36.925 16.848 37.073 17.304 ;
     RECT  37.001 43.92 37.109 44.424 ;
     RECT  36.601 2.688 37.145 3.48 ;
     RECT  36.929 37.344 37.145 41.112 ;
     RECT  37.145 37.344 37.181 40.584 ;
     RECT  36.749 32.736 37.217 33.672 ;
     RECT  37.217 32.736 37.249 33.48 ;
     RECT  36.925 14.208 37.289 14.232 ;
     RECT  35.885 30.384 37.321 31.416 ;
     RECT  36.641 10.368 37.325 12.936 ;
     RECT  37.043 19.344 37.357 23.832 ;
     RECT  37.325 10.464 37.393 12.936 ;
     RECT  35.849 27.648 37.477 28.2 ;
     RECT  37.477 27.312 37.564 28.2 ;
     RECT  36.997 4.656 37.609 4.68 ;
     RECT  37.001 42.144 37.685 42.696 ;
     RECT  36.785 45.408 37.685 50.952 ;
     RECT  37.609 4.656 37.789 5.112 ;
     RECT  37.073 17.184 37.865 17.304 ;
     RECT  36.659 6.768 37.897 8.232 ;
     RECT  37.321 30.288 37.969 31.416 ;
     RECT  37.969 29.424 38.005 31.416 ;
     RECT  37.249 32.448 38.005 33.48 ;
     RECT  37.357 19.344 38.06 24.168 ;
     RECT  37.685 42.528 38.077 42.696 ;
     RECT  37.564 27.648 38.101 28.2 ;
     RECT  38.005 29.424 38.101 33.48 ;
     RECT  36.353 15.792 38.117 15.816 ;
     RECT  38.06 18.768 38.147 24.168 ;
     RECT  37.685 50.16 38.153 50.952 ;
     RECT  38.101 27.648 38.189 33.48 ;
     RECT  38.077 42.528 38.197 42.792 ;
     RECT  37.897 6.336 38.225 8.232 ;
     RECT  37.685 45.408 38.225 49.08 ;
     RECT  37.181 37.344 38.293 39.432 ;
     RECT  37.393 10.464 38.297 13.08 ;
     RECT  38.189 27.648 38.297 31.704 ;
     RECT  38.225 8.208 38.329 8.232 ;
     RECT  36.641 9.36 38.329 9.384 ;
     RECT  38.297 10.608 38.333 13.08 ;
     RECT  37.105 35.328 38.401 35.352 ;
     RECT  38.293 36.912 38.401 39.432 ;
     RECT  38.297 28.944 38.441 31.704 ;
     RECT  38.293 14.928 38.473 14.952 ;
     RECT  38.041 17.088 38.473 17.112 ;
     RECT  38.473 16.848 38.513 17.112 ;
     RECT  38.189 32.832 38.513 33.48 ;
     RECT  38.401 35.328 38.513 39.432 ;
     RECT  38.147 19.2 38.629 24.168 ;
     RECT  37.181 40.56 38.629 40.584 ;
     RECT  38.513 35.328 38.684 37.992 ;
     RECT  38.473 14.688 38.689 14.952 ;
     RECT  38.513 33.024 38.689 33.48 ;
     RECT  38.329 8.208 38.693 9.624 ;
     RECT  37.789 4.464 38.725 5.112 ;
     RECT  38.225 6.336 38.725 6.6 ;
     RECT  38.689 14.112 38.725 14.952 ;
     RECT  38.297 27.648 38.725 27.672 ;
     RECT  38.689 33.024 38.765 34.248 ;
     RECT  38.513 39.216 38.765 39.432 ;
     RECT  38.693 8.208 38.771 9.384 ;
     RECT  38.629 19.2 38.771 24.552 ;
     RECT  38.725 27.36 38.771 27.672 ;
     RECT  38.771 20.496 38.772 22.056 ;
     RECT  37.109 44.4 38.797 44.424 ;
     RECT  38.225 45.408 38.797 48.696 ;
     RECT  38.771 8.208 38.801 9.096 ;
     RECT  38.765 33.024 38.801 33.24 ;
     RECT  38.771 23.52 38.819 24.552 ;
     RECT  38.725 13.632 38.837 14.952 ;
     RECT  38.797 44.4 38.837 48.696 ;
     RECT  38.771 27.36 38.869 27.384 ;
     RECT  38.765 39.312 38.873 39.432 ;
     RECT  38.869 27.072 38.915 27.384 ;
     RECT  38.772 20.496 38.945 22.008 ;
     RECT  38.819 24.096 38.965 24.552 ;
     RECT  38.965 24.096 38.977 25.272 ;
     RECT  38.333 10.608 38.981 12.6 ;
     RECT  38.837 45.216 38.981 48.696 ;
     RECT  38.915 27.072 39.011 27.096 ;
     RECT  38.513 16.848 39.013 16.872 ;
     RECT  38.945 20.496 39.017 21.96 ;
     RECT  38.725 3.216 39.049 3.24 ;
     RECT  38.977 24.096 39.049 25.56 ;
     RECT  38.441 28.944 39.089 31.416 ;
     RECT  38.873 39.408 39.121 39.432 ;
     RECT  38.629 40.416 39.121 41.064 ;
     RECT  38.771 19.2 39.157 19.32 ;
     RECT  38.765 34.224 39.229 34.248 ;
     RECT  38.684 35.232 39.229 37.992 ;
     RECT  38.837 13.632 39.233 14.76 ;
     RECT  39.049 2.784 39.337 3.24 ;
     RECT  38.725 4.464 39.541 6.6 ;
     RECT  39.157 18.768 39.777 19.32 ;
     RECT  39.089 28.944 39.805 31.176 ;
     RECT  39.337 2.256 39.877 3.24 ;
     RECT  39.541 4.464 39.877 7.176 ;
     RECT  39.121 39.408 39.877 41.064 ;
     RECT  39.877 4.416 40.165 7.176 ;
     RECT  38.801 8.208 40.165 9 ;
     RECT  39.229 34.224 40.165 37.992 ;
     RECT  39.877 2.256 40.208 3.432 ;
     RECT  40.165 4.416 40.208 9 ;
     RECT  38.981 10.608 40.208 12.552 ;
     RECT  39.233 14.112 40.208 14.76 ;
     RECT  39.013 16.032 40.208 16.872 ;
     RECT  39.777 18.528 40.208 19.32 ;
     RECT  39.017 20.496 40.208 21.816 ;
     RECT  39.913 22.848 40.208 22.872 ;
     RECT  39.049 24.096 40.208 26.424 ;
     RECT  39.805 28.416 40.208 31.176 ;
     RECT  38.801 33.024 40.208 33.048 ;
     RECT  40.165 34.128 40.208 37.992 ;
     RECT  39.877 39.024 40.208 41.064 ;
     RECT  38.197 42.528 40.208 43.272 ;
     RECT  38.981 45.216 40.208 48.552 ;
     RECT  38.153 50.928 40.208 50.952 ;
     RECT  40.208 2.148 40.312 51.852 ;
     RECT  40.312 2.256 40.504 51.582 ;
     RECT  40.504 16.848 40.565 21.816 ;
     RECT  40.504 47.856 40.565 51.384 ;
     RECT  40.504 22.8 40.601 22.872 ;
     RECT  40.504 2.256 40.643 8.232 ;
     RECT  40.504 24.096 40.739 26.856 ;
     RECT  40.504 42.576 40.745 43.128 ;
     RECT  40.565 17.088 40.787 21.816 ;
     RECT  40.504 27.888 40.883 30.408 ;
     RECT  40.504 34.128 40.889 37.08 ;
     RECT  40.504 31.392 40.925 33.048 ;
     RECT  40.787 17.616 40.997 21.816 ;
     RECT  40.565 47.856 40.997 50.136 ;
     RECT  40.997 47.856 41.02 49.752 ;
     RECT  40.643 2.88 41.249 8.232 ;
     RECT  40.601 22.848 41.357 22.872 ;
     RECT  40.883 27.936 41.465 30.408 ;
     RECT  41.249 4.416 41.468 8.232 ;
     RECT  40.925 33.024 41.533 33.048 ;
     RECT  40.889 34.128 41.533 36.648 ;
     RECT  40.504 38.784 41.533 39.816 ;
     RECT  40.997 17.616 41.537 21.48 ;
     RECT  40.739 24.864 41.537 26.856 ;
     RECT  41.468 40.8 41.555 40.824 ;
     RECT  41.537 20.016 41.573 21.48 ;
     RECT  40.504 13.824 41.603 15.384 ;
     RECT  41.603 13.824 41.605 14.952 ;
     RECT  41.573 20.448 41.609 21.48 ;
     RECT  41.533 33.024 41.645 36.648 ;
     RECT  40.504 45.024 41.645 46.584 ;
     RECT  41.537 17.616 41.681 18.792 ;
     RECT  41.645 45.024 41.681 45.288 ;
     RECT  41.468 4.416 41.713 8.664 ;
     RECT  41.713 4.416 41.749 8.76 ;
     RECT  40.504 10.416 41.749 12.024 ;
     RECT  40.745 43.104 41.749 43.128 ;
     RECT  41.465 30.24 41.785 30.408 ;
     RECT  40.925 31.392 41.785 31.704 ;
     RECT  41.249 2.88 41.797 3.384 ;
     RECT  41.749 4.416 41.797 12.024 ;
     RECT  41.605 13.152 41.797 14.952 ;
     RECT  41.681 45.024 41.857 45.048 ;
     RECT  41.609 20.448 41.861 21.096 ;
     RECT  41.645 33.024 41.897 34.92 ;
     RECT  41.677 0.48 41.929 0.504 ;
     RECT  41.533 38.16 41.933 39.816 ;
     RECT  41.537 24.864 41.969 26.376 ;
     RECT  41.749 42.528 42.001 43.128 ;
     RECT  41.857 44.352 42.001 45.048 ;
     RECT  41.969 24.864 42.005 26.088 ;
     RECT  41.797 2.736 42.037 3.384 ;
     RECT  42.037 2.544 42.085 3.384 ;
     RECT  41.645 36.096 42.133 36.648 ;
     RECT  41.785 30.24 42.149 31.704 ;
     RECT  41.933 38.784 42.179 39.816 ;
     RECT  41.929 0.48 42.181 0.552 ;
     RECT  41.645 46.32 42.181 46.584 ;
     RECT  41.02 47.856 42.181 49.368 ;
     RECT  40.565 51.36 42.185 51.384 ;
     RECT  42.133 36.096 42.22 37.608 ;
     RECT  42.005 24.864 42.221 26.04 ;
     RECT  42.181 0.48 42.253 0.6 ;
     RECT  42.181 46.32 42.253 49.368 ;
     RECT  42.149 30.816 42.257 31.704 ;
     RECT  42.085 1.872 42.277 3.384 ;
     RECT  41.797 4.416 42.277 14.952 ;
     RECT  42.253 46.32 42.289 49.896 ;
     RECT  42.22 36.096 42.329 37.032 ;
     RECT  41.897 33.552 42.365 34.92 ;
     RECT  42.277 1.872 42.428 14.952 ;
     RECT  42.257 30.816 42.509 31.368 ;
     RECT  42.179 39.216 42.545 39.816 ;
     RECT  42.253 0.48 42.649 0.648 ;
     RECT  42.428 1.68 42.649 14.952 ;
     RECT  42.329 36.24 42.653 37.032 ;
     RECT  42.001 42.528 42.653 45.048 ;
     RECT  41.861 20.928 42.685 21.096 ;
     RECT  42.289 46.32 42.685 50.76 ;
     RECT  42.653 42.528 42.721 44.376 ;
     RECT  42.545 39.696 42.757 39.816 ;
     RECT  42.721 41.088 42.757 41.112 ;
     RECT  42.613 28.992 42.761 29.016 ;
     RECT  42.653 36.624 42.797 37.032 ;
     RECT  41.681 17.856 42.805 18.792 ;
     RECT  42.685 45.456 42.833 50.76 ;
     RECT  42.805 17.472 42.853 18.792 ;
     RECT  42.685 20.928 42.853 21.192 ;
     RECT  42.757 39.696 42.901 41.112 ;
     RECT  42.721 42.24 42.901 44.376 ;
     RECT  42.509 30.816 42.905 31.224 ;
     RECT  42.649 0.48 42.937 14.952 ;
     RECT  42.853 20.4 42.94 21.192 ;
     RECT  42.937 0.096 43.009 14.952 ;
     RECT  42.853 17.472 43.017 19.032 ;
     RECT  42.901 39.696 43.139 44.376 ;
     RECT  43.139 39.696 43.157 41.112 ;
     RECT  42.94 21.12 43.201 21.192 ;
     RECT  43.201 21.168 43.237 21.192 ;
     RECT  43.139 42.24 43.265 44.376 ;
     RECT  43.237 21.168 43.283 21.672 ;
     RECT  43.009 0.096 43.285 15.384 ;
     RECT  42.833 47.904 43.297 50.76 ;
     RECT  42.833 45.456 43.301 46.344 ;
     RECT  43.297 47.904 43.409 50.856 ;
     RECT  42.905 30.816 43.441 30.936 ;
     RECT  43.157 41.04 43.445 41.112 ;
     RECT  41.749 23.712 43.573 23.736 ;
     RECT  42.221 24.864 43.573 25.752 ;
     RECT  43.441 30.336 43.573 30.936 ;
     RECT  43.301 45.456 43.589 46.248 ;
     RECT  43.409 47.904 43.625 49.896 ;
     RECT  43.573 23.712 43.657 25.752 ;
     RECT  42.365 34.224 43.661 34.392 ;
     RECT  43.265 42.24 43.697 43.608 ;
     RECT  41.465 27.936 43.837 27.96 ;
     RECT  43.625 47.904 43.837 49.464 ;
     RECT  43.697 42.72 43.877 43.608 ;
     RECT  43.837 47.856 43.909 49.464 ;
     RECT  43.283 21.648 43.913 21.672 ;
     RECT  42.797 36.624 43.945 36.648 ;
     RECT  43.285 0.096 44.089 16.008 ;
     RECT  43.017 17.04 44.089 19.032 ;
     RECT  43.117 32.448 44.101 33.144 ;
     RECT  44.089 0.096 44.125 19.032 ;
     RECT  43.909 47.28 44.129 49.464 ;
     RECT  43.657 22.8 44.161 25.752 ;
     RECT  44.101 32.16 44.188 33.144 ;
     RECT  44.188 32.448 44.209 33.144 ;
     RECT  43.837 27.936 44.233 28.488 ;
     RECT  43.573 30.24 44.233 30.936 ;
     RECT  44.129 47.856 44.236 49.464 ;
     RECT  44.125 0.096 44.237 19.512 ;
     RECT  43.589 45.456 44.269 45.576 ;
     RECT  43.661 34.368 44.341 34.392 ;
     RECT  44.233 29.472 44.345 30.936 ;
     RECT  44.269 45.216 44.345 45.576 ;
     RECT  43.945 36.624 44.377 36.792 ;
     RECT  44.161 22.8 44.413 26.376 ;
     RECT  43.157 39.696 44.413 39.864 ;
     RECT  44.345 30 44.449 30.936 ;
     RECT  43.729 51.216 44.449 51.528 ;
     RECT  44.377 35.856 44.483 36.792 ;
     RECT  44.237 0.192 44.489 19.512 ;
     RECT  44.413 22.8 44.525 26.664 ;
     RECT  44.345 45.216 44.525 45.48 ;
     RECT  44.413 39.456 44.533 39.864 ;
     RECT  44.233 27.744 44.561 28.488 ;
     RECT  44.161 38.112 44.579 38.136 ;
     RECT  44.449 30 44.593 31.128 ;
     RECT  44.561 28.224 44.845 28.488 ;
     RECT  43.445 41.04 44.881 41.064 ;
     RECT  44.449 50.736 45.169 51.528 ;
     RECT  44.593 30 45.241 31.416 ;
     RECT  44.209 33.12 45.241 33.144 ;
     RECT  44.489 0.192 45.253 19.08 ;
     RECT  44.525 23.808 45.493 26.664 ;
     RECT  45.253 0.096 45.565 19.08 ;
     RECT  44.629 20.16 45.565 20.184 ;
     RECT  45.241 30 45.565 33.144 ;
     RECT  45.493 23.808 45.601 26.76 ;
     RECT  44.525 45.216 45.601 45.24 ;
     RECT  45.565 0.096 45.608 20.184 ;
     RECT  44.737 21.504 45.608 21.528 ;
     RECT  44.525 22.8 45.608 22.824 ;
     RECT  45.601 23.808 45.608 26.856 ;
     RECT  44.845 28.224 45.608 28.536 ;
     RECT  45.565 30 45.608 33.336 ;
     RECT  44.341 34.368 45.608 34.824 ;
     RECT  44.483 35.952 45.608 36.792 ;
     RECT  44.533 39.312 45.608 39.864 ;
     RECT  44.881 41.04 45.608 41.496 ;
     RECT  43.877 42.72 45.608 42.744 ;
     RECT  45.601 44.064 45.608 44.088 ;
     RECT  45.601 45.216 45.608 46.104 ;
     RECT  44.236 47.856 45.608 48.936 ;
     RECT  45.169 50.544 45.608 51.528 ;
     RECT  45.608 0.096 45.712 51.852 ;
     RECT  45.712 0.096 45.904 51.582 ;
     RECT  45.904 44.064 46.001 44.376 ;
     RECT  45.904 23.856 46.019 26.856 ;
     RECT  45.904 45.408 46.019 50.568 ;
     RECT  45.904 0.096 46.067 22.056 ;
     RECT  46.019 23.856 46.109 25.272 ;
     RECT  45.904 34.368 46.145 37.032 ;
     RECT  46.019 45.408 46.181 46.776 ;
     RECT  46.019 47.76 46.259 50.04 ;
     RECT  46.259 47.76 46.289 48.696 ;
     RECT  46.019 26.304 46.505 26.856 ;
     RECT  45.904 39.744 46.577 42.312 ;
     RECT  46.145 34.368 46.739 34.536 ;
     RECT  45.904 31.104 46.78 33.336 ;
     RECT  46.001 44.064 46.793 44.088 ;
     RECT  46.577 39.792 46.835 42.312 ;
     RECT  46.109 24.48 46.901 25.272 ;
     RECT  46.505 26.352 46.901 26.856 ;
     RECT  46.901 26.4 46.933 26.856 ;
     RECT  46.739 34.512 46.937 34.536 ;
     RECT  46.835 39.792 46.973 40.44 ;
     RECT  46.181 46.56 46.988 46.776 ;
     RECT  46.289 47.76 46.988 48.168 ;
     RECT  46.78 32.304 47.009 33.336 ;
     RECT  46.067 0.096 47.045 21.576 ;
     RECT  46.988 46.56 47.075 48.168 ;
     RECT  45.904 29.04 47.113 29.688 ;
     RECT  46.78 31.104 47.113 31.128 ;
     RECT  46.835 41.472 47.113 42.312 ;
     RECT  47.077 43.44 47.113 43.464 ;
     RECT  46.901 24.48 47.117 24.936 ;
     RECT  47.075 47.808 47.189 48.168 ;
     RECT  47.045 21.552 47.329 21.576 ;
     RECT  47.113 41.472 47.333 43.464 ;
     RECT  46.933 26.4 47.365 26.904 ;
     RECT  45.904 27.936 47.365 27.96 ;
     RECT  47.333 42.144 47.369 43.464 ;
     RECT  46.259 50.016 47.401 50.04 ;
     RECT  47.401 49.824 47.437 50.04 ;
     RECT  47.365 26.4 47.545 27.96 ;
     RECT  47.113 29.04 47.545 31.128 ;
     RECT  47.189 47.808 47.585 47.88 ;
     RECT  46.181 45.408 47.617 45.48 ;
     RECT  47.075 46.56 47.617 46.776 ;
     RECT  47.617 45.408 47.653 46.776 ;
     RECT  47.369 42.144 47.693 43.32 ;
     RECT  47.437 49.824 47.725 50.136 ;
     RECT  47.545 26.4 47.747 31.128 ;
     RECT  47.725 49.824 47.765 50.76 ;
     RECT  47.693 42.144 47.801 42.168 ;
     RECT  47.765 50.112 47.843 50.76 ;
     RECT  46.145 35.712 47.845 37.032 ;
     RECT  45.904 38.736 47.941 38.76 ;
     RECT  46.973 40.416 47.941 40.44 ;
     RECT  47.845 35.712 47.945 37.608 ;
     RECT  47.941 38.736 48.028 40.44 ;
     RECT  47.329 21.552 48.053 22.2 ;
     RECT  47.747 26.4 48.157 27 ;
     RECT  48.028 40.416 48.193 40.44 ;
     RECT  47.045 0.096 48.233 20.328 ;
     RECT  48.233 0.144 48.265 20.328 ;
     RECT  47.977 51.36 48.305 51.384 ;
     RECT  47.009 32.304 48.337 33.144 ;
     RECT  47.761 34.128 48.337 34.152 ;
     RECT  47.653 44.832 48.337 46.776 ;
     RECT  47.945 35.712 48.409 36.552 ;
     RECT  48.157 25.968 48.413 27 ;
     RECT  48.337 23.856 48.449 23.88 ;
     RECT  48.413 25.968 48.449 26.904 ;
     RECT  48.449 25.968 48.485 26.808 ;
     RECT  48.337 32.304 48.485 34.152 ;
     RECT  48.337 44.784 48.589 46.776 ;
     RECT  47.747 28.416 48.593 29.112 ;
     RECT  48.409 35.328 48.629 36.552 ;
     RECT  48.485 32.928 48.697 34.152 ;
     RECT  47.693 43.296 48.697 43.32 ;
     RECT  47.585 47.856 48.697 47.88 ;
     RECT  48.265 0.144 48.755 21 ;
     RECT  48.028 38.736 48.773 38.76 ;
     RECT  48.593 28.464 48.845 29.112 ;
     RECT  48.697 42.624 48.901 43.32 ;
     RECT  48.901 42.48 48.947 43.32 ;
     RECT  48.697 32.928 48.953 34.728 ;
     RECT  48.845 28.512 48.985 29.112 ;
     RECT  47.747 30.384 48.985 31.128 ;
     RECT  48.947 42.48 48.989 42.648 ;
     RECT  48.755 2.016 49.021 21 ;
     RECT  48.053 22.176 49.021 22.2 ;
     RECT  48.989 42.624 49.025 42.648 ;
     RECT  47.117 24.912 49.057 24.936 ;
     RECT  48.485 25.968 49.057 26.088 ;
     RECT  48.985 28.512 49.057 31.128 ;
     RECT  48.589 44.448 49.205 46.776 ;
     RECT  49.129 23.904 49.273 23.928 ;
     RECT  49.057 24.912 49.273 26.088 ;
     RECT  49.021 2.016 49.277 22.2 ;
     RECT  49.057 28.512 49.277 31.224 ;
     RECT  49.277 2.016 49.313 18.936 ;
     RECT  49.205 44.448 49.349 46.152 ;
     RECT  48.755 0.144 49.381 0.696 ;
     RECT  48.953 32.928 49.42 34.152 ;
     RECT  48.629 35.712 49.453 36.552 ;
     RECT  47.945 37.584 49.453 37.608 ;
     RECT  49.349 44.448 49.489 44.472 ;
     RECT  49.453 35.712 49.573 37.608 ;
     RECT  49.573 35.712 49.619 37.656 ;
     RECT  49.619 37.632 49.628 37.656 ;
     RECT  49.277 30.72 49.637 31.224 ;
     RECT  48.697 47.856 49.637 48.504 ;
     RECT  49.277 20.16 49.669 22.2 ;
     RECT  49.628 37.632 49.673 38.184 ;
     RECT  49.489 44.16 49.709 44.472 ;
     RECT  49.628 27.312 49.715 27.336 ;
     RECT  49.673 38.16 49.715 38.184 ;
     RECT  49.273 23.904 49.745 26.088 ;
     RECT  49.709 44.16 49.763 44.376 ;
     RECT  49.669 20.16 49.781 22.584 ;
     RECT  49.619 35.712 49.853 36.12 ;
     RECT  49.381 0.096 49.885 0.696 ;
     RECT  49.745 23.904 49.889 24.936 ;
     RECT  49.42 33.6 50.003 34.152 ;
     RECT  50.003 34.128 50.029 34.152 ;
     RECT  49.853 35.712 50.029 35.736 ;
     RECT  49.885 0.048 50.033 0.696 ;
     RECT  49.349 46.128 50.033 46.152 ;
     RECT  48.193 40.416 50.137 41.016 ;
     RECT  50.033 0.096 50.141 0.696 ;
     RECT  50.141 0.144 50.209 0.696 ;
     RECT  50.209 0.144 50.213 1.176 ;
     RECT  49.745 26.064 50.353 26.088 ;
     RECT  50.213 0.192 50.425 1.176 ;
     RECT  49.313 2.256 50.425 18.936 ;
     RECT  49.277 28.512 50.425 29.064 ;
     RECT  50.353 26.064 50.533 26.232 ;
     RECT  49.781 20.256 50.569 22.584 ;
     RECT  49.637 31.104 50.569 31.224 ;
     RECT  50.425 27.84 50.713 29.064 ;
     RECT  50.569 31.104 50.732 31.32 ;
     RECT  50.425 0.192 51.008 18.936 ;
     RECT  50.569 20.256 51.008 23.112 ;
     RECT  49.889 24.72 51.008 24.936 ;
     RECT  50.533 26.064 51.008 26.808 ;
     RECT  50.713 27.84 51.008 29.4 ;
     RECT  50.732 30.72 51.008 32.184 ;
     RECT  50.029 34.128 51.008 35.736 ;
     RECT  50.137 40.416 51.008 41.64 ;
     RECT  49.763 44.16 51.008 44.184 ;
     RECT  49.637 47.856 51.008 48.024 ;
     RECT  49.633 50.016 51.008 50.04 ;
     RECT  51.008 0.192 51.112 51.852 ;
     RECT  51.112 0.192 51.185 51.582 ;
     RECT  51.185 2.418 51.304 51.582 ;
     RECT  51.185 0.192 51.361 1.224 ;
     RECT  51.361 0.096 51.443 1.224 ;
     RECT  51.443 0.096 51.548 1.176 ;
     RECT  51.304 17.184 51.725 17.208 ;
     RECT  51.304 15.408 51.923 15.48 ;
     RECT  51.304 4.512 51.971 11.976 ;
     RECT  51.548 0.048 52.013 1.176 ;
     RECT  51.971 6.912 52.067 11.976 ;
     RECT  52.067 6.912 52.115 11.016 ;
     RECT  51.971 4.512 52.121 5.592 ;
     RECT  52.115 8.016 52.163 11.016 ;
     RECT  51.304 2.496 52.193 3.432 ;
     RECT  52.163 8.016 52.259 8.568 ;
     RECT  52.259 8.016 52.307 8.52 ;
     RECT  52.163 9.696 52.355 11.016 ;
     RECT  52.121 4.512 52.499 4.536 ;
     RECT  51.304 13.104 52.499 14.424 ;
     RECT  52.193 3.408 52.547 3.432 ;
     RECT  52.499 13.104 52.547 13.848 ;
     RECT  52.355 9.696 52.595 10.296 ;
     RECT  52.121 5.568 52.643 5.592 ;
     RECT  51.923 15.408 52.643 15.432 ;
     RECT  52.595 9.696 52.691 9.72 ;
     RECT  52.013 0.048 52.787 0.552 ;
     RECT  52.547 13.152 52.787 13.848 ;
     RECT  52.787 0.096 52.841 0.552 ;
     RECT  52.787 13.824 52.931 13.848 ;
     RECT  52.115 6.912 52.949 6.936 ;
     RECT  52.841 0.096 53.027 0.264 ;
     RECT  52.307 8.496 53.027 8.52 ;
     RECT  53.027 0.192 53.417 0.264 ;
     RECT  53.417 0.24 53.489 0.264 ;
    LAYER M5 ;
     RECT  42.192 0.016 51.336 0.037 ;
     RECT  42.192 0.037 52.776 0.085 ;
     RECT  42.192 0.085 53.016 0.611 ;
     RECT  42.384 0.611 53.016 0.659 ;
     RECT  42.48 0.659 53.016 1.861 ;
     RECT  2.4 2.137 2.52 2.151 ;
     RECT  7.8 2.137 7.92 2.151 ;
     RECT  13.2 2.137 13.32 2.151 ;
     RECT  18.6 2.137 18.72 2.151 ;
     RECT  24 2.137 24.12 2.151 ;
     RECT  29.4 2.137 29.52 2.151 ;
     RECT  34.8 2.137 34.92 2.151 ;
     RECT  40.2 2.137 40.32 2.151 ;
     RECT  40.2 2.151 40.512 2.245 ;
     RECT  13.2 2.151 13.512 2.293 ;
     RECT  42.096 1.861 53.016 2.533 ;
     RECT  13.2 2.293 13.656 2.581 ;
     RECT  15.024 2.293 15.048 2.581 ;
     RECT  42.048 2.533 53.016 2.725 ;
     RECT  34.8 2.151 35.112 2.773 ;
     RECT  40.2 2.245 40.632 2.773 ;
     RECT  7.8 2.151 8.112 2.821 ;
     RECT  39.888 2.773 40.632 2.915 ;
     RECT  13.2 2.581 15.048 3.011 ;
     RECT  10.416 2.245 10.44 3.301 ;
     RECT  24 2.151 24.312 3.397 ;
     RECT  39.888 2.915 40.512 3.443 ;
     RECT  29.4 2.151 29.712 3.685 ;
     RECT  34.8 2.773 35.208 3.827 ;
     RECT  7.8 2.821 8.808 3.971 ;
     RECT  10.416 3.301 10.824 4.213 ;
     RECT  13.2 3.011 14.424 4.357 ;
     RECT  40.2 3.443 40.512 4.405 ;
     RECT  41.808 2.725 53.016 4.405 ;
     RECT  33.648 2.581 33.672 4.595 ;
     RECT  13.2 4.357 15.336 4.643 ;
     RECT  22.512 4.453 22.536 4.837 ;
     RECT  23.712 3.397 24.312 4.837 ;
     RECT  28.8 3.685 29.712 4.933 ;
     RECT  22.512 4.837 24.312 5.077 ;
     RECT  10.176 4.213 10.824 5.171 ;
     RECT  11.952 3.109 11.976 5.171 ;
     RECT  14.544 4.643 15.336 5.171 ;
     RECT  22.512 5.077 24.888 5.171 ;
     RECT  31.872 4.357 31.896 5.171 ;
     RECT  6.72 4.645 6.744 5.365 ;
     RECT  27.936 4.933 29.712 5.461 ;
     RECT  13.2 4.643 13.512 5.605 ;
     RECT  5.136 3.301 5.16 5.701 ;
     RECT  5.136 5.701 5.64 5.747 ;
     RECT  27.936 5.461 30.504 5.941 ;
     RECT  7.8 3.971 8.232 6.133 ;
     RECT  36.144 5.461 36.168 6.229 ;
     RECT  40.2 4.405 53.016 6.373 ;
     RECT  12.672 5.605 13.512 6.613 ;
     RECT  14.544 5.171 14.568 6.613 ;
     RECT  12.672 6.613 14.568 6.659 ;
     RECT  36.144 6.229 36.264 6.661 ;
     RECT  23.04 5.171 24.888 6.803 ;
     RECT  36.144 6.661 36.648 6.803 ;
     RECT  39.552 6.373 53.016 6.803 ;
     RECT  7.8 6.133 8.52 6.851 ;
     RECT  17.424 4.213 17.448 6.851 ;
     RECT  20.064 4.261 20.088 6.899 ;
     RECT  26.496 6.181 26.52 7.187 ;
     RECT  39.552 6.803 40.512 7.187 ;
     RECT  10.176 5.171 10.248 7.189 ;
     RECT  23.04 6.803 24.408 7.379 ;
     RECT  27.84 5.941 30.504 7.379 ;
     RECT  12.672 6.659 14.28 7.427 ;
     RECT  12.672 7.427 13.512 7.765 ;
     RECT  10.176 7.189 10.536 7.861 ;
     RECT  41.808 6.803 53.016 7.861 ;
     RECT  34.8 3.827 35.112 7.957 ;
     RECT  12.528 7.765 13.512 8.005 ;
     RECT  36.144 6.803 36.312 8.197 ;
     RECT  41.52 7.861 53.016 8.531 ;
     RECT  5.616 5.747 5.64 8.579 ;
     RECT  28.656 7.379 30.504 8.579 ;
     RECT  9.696 7.861 10.536 8.627 ;
     RECT  41.52 8.531 52.92 8.675 ;
     RECT  4.56 7.909 4.584 8.867 ;
     RECT  33.84 7.957 35.112 9.011 ;
     RECT  34.8 9.011 35.112 9.013 ;
     RECT  36.144 8.197 37.032 9.013 ;
     RECT  31.872 8.293 31.896 9.155 ;
     RECT  12.336 8.005 13.512 9.299 ;
     RECT  6.624 5.365 6.744 9.349 ;
     RECT  38.736 9.061 38.76 9.395 ;
     RECT  9.696 8.627 9.96 9.635 ;
     RECT  23.04 7.379 24.312 9.731 ;
     RECT  34.8 9.013 37.032 9.779 ;
     RECT  11.232 8.869 11.256 10.067 ;
     RECT  12.528 9.299 13.512 10.067 ;
     RECT  5.232 9.925 5.256 10.117 ;
     RECT  28.656 8.579 30.264 10.307 ;
     RECT  6.336 9.349 6.744 10.309 ;
     RECT  7.8 6.851 8.112 10.309 ;
     RECT  23.136 9.731 24.312 10.357 ;
     RECT  26.688 9.637 26.712 10.453 ;
     RECT  41.76 8.675 52.92 10.547 ;
     RECT  23.136 10.357 24.6 10.883 ;
     RECT  29.4 10.307 30.264 10.883 ;
     RECT  23.136 10.883 24.312 10.981 ;
     RECT  26.4 10.453 26.712 11.219 ;
     RECT  38.88 10.597 38.904 11.269 ;
     RECT  34.8 9.779 35.112 11.365 ;
     RECT  36.24 9.779 37.032 11.365 ;
     RECT  38.064 11.269 38.904 11.365 ;
     RECT  28.176 10.789 28.2 11.411 ;
     RECT  32.976 10.165 33 11.459 ;
     RECT  13.008 10.067 13.512 11.701 ;
     RECT  22.752 10.981 24.312 11.941 ;
     RECT  26.976 11.221 27 11.989 ;
     RECT  9.936 9.635 9.96 12.035 ;
     RECT  15.696 6.805 15.72 12.035 ;
     RECT  34.8 11.365 38.904 12.179 ;
     RECT  38.88 12.179 38.904 12.421 ;
     RECT  4.848 10.117 5.256 12.469 ;
     RECT  6.336 10.309 8.112 12.469 ;
     RECT  26.976 11.989 27.864 12.517 ;
     RECT  38.88 12.421 39.048 12.517 ;
     RECT  21.12 11.845 21.144 12.563 ;
     RECT  38.88 12.517 39.144 12.563 ;
     RECT  41.808 10.547 52.92 12.611 ;
     RECT  26.976 12.517 27.912 12.901 ;
     RECT  34.8 12.179 37.032 12.947 ;
     RECT  22.752 11.941 25.032 13.139 ;
     RECT  26.736 12.901 27.912 13.187 ;
     RECT  34.8 12.947 36.84 13.187 ;
     RECT  22.752 13.139 22.776 13.525 ;
     RECT  22.464 13.525 22.776 13.571 ;
     RECT  4.848 12.469 8.112 13.621 ;
     RECT  24 13.139 25.032 13.667 ;
     RECT  4.848 13.621 8.232 13.715 ;
     RECT  26.736 13.187 27.864 13.715 ;
     RECT  18.6 2.151 18.912 13.813 ;
     RECT  42.192 12.611 52.92 13.859 ;
     RECT  31.488 10.837 31.512 14.099 ;
     RECT  27.696 13.715 27.72 14.291 ;
     RECT  36.24 13.187 36.84 14.435 ;
     RECT  18.6 13.813 19.752 14.485 ;
     RECT  34.8 13.187 35.112 14.485 ;
     RECT  5.232 13.715 8.232 14.675 ;
     RECT  22.464 13.571 22.488 14.675 ;
     RECT  42.192 13.859 52.632 14.723 ;
     RECT  24 13.667 24.456 14.725 ;
     RECT  40.2 7.187 40.512 14.725 ;
     RECT  40.2 14.725 40.824 14.773 ;
     RECT  17.616 14.485 19.752 14.819 ;
     RECT  22.8 14.725 24.936 14.915 ;
     RECT  40.2 14.773 41.592 15.395 ;
     RECT  42.816 14.723 52.632 15.443 ;
     RECT  17.616 14.819 18.912 15.491 ;
     RECT  42.816 15.443 51.912 15.491 ;
     RECT  29.4 10.883 29.712 15.493 ;
     RECT  34.224 14.485 35.112 15.875 ;
     RECT  5.664 14.675 8.232 16.115 ;
     RECT  39.024 12.563 39.144 16.405 ;
     RECT  40.2 15.395 40.824 16.405 ;
     RECT  42.816 15.491 51.312 16.595 ;
     RECT  24 14.915 24.936 16.789 ;
     RECT  39.024 16.405 40.824 16.883 ;
     RECT  24 16.789 25.08 17.027 ;
     RECT  12.672 11.701 13.512 17.075 ;
     RECT  20.736 16.933 20.76 17.077 ;
     RECT  34.272 15.875 35.112 17.077 ;
     RECT  20.736 17.077 21.144 17.123 ;
     RECT  36.816 14.435 36.84 17.123 ;
     RECT  21.024 17.123 21.144 17.219 ;
     RECT  42.816 16.595 44.184 17.219 ;
     RECT  5.664 16.115 8.112 17.317 ;
     RECT  42.816 17.219 43.176 17.507 ;
     RECT  29.28 15.493 29.712 17.605 ;
     RECT  27.552 16.933 27.576 17.651 ;
     RECT  15.936 12.229 15.96 17.653 ;
     RECT  44.16 17.219 44.184 17.699 ;
     RECT  45.168 16.595 51.312 17.699 ;
     RECT  15.648 17.653 15.96 17.845 ;
     RECT  34.272 17.077 35.64 17.987 ;
     RECT  4.704 17.317 8.112 17.989 ;
     RECT  29.28 17.605 30.264 17.989 ;
     RECT  15.648 17.845 16.008 18.181 ;
     RECT  22.8 14.915 22.824 18.419 ;
     RECT  39.024 16.883 39.144 18.517 ;
     RECT  40.2 16.883 40.824 18.517 ;
     RECT  34.272 17.987 35.112 18.709 ;
     RECT  29.088 17.989 30.264 18.757 ;
     RECT  39.024 18.517 40.824 18.757 ;
     RECT  43.056 17.507 43.176 18.757 ;
     RECT  4.704 17.989 8.328 18.803 ;
     RECT  33.6 18.709 35.112 18.851 ;
     RECT  45.168 17.699 48.984 18.851 ;
     RECT  50.112 17.699 51.312 18.851 ;
     RECT  28.512 18.757 30.264 18.899 ;
     RECT  45.408 18.851 48.984 18.899 ;
     RECT  45.408 18.899 47.304 18.947 ;
     RECT  50.16 18.851 51.312 18.947 ;
     RECT  45.408 18.947 46.728 18.995 ;
     RECT  14.688 18.181 16.008 19.235 ;
     RECT  2.4 2.151 2.712 19.333 ;
     RECT  10.08 18.421 10.104 19.427 ;
     RECT  17.184 18.181 17.208 19.523 ;
     RECT  4.704 18.803 8.112 20.003 ;
     RECT  34.272 18.851 35.112 20.003 ;
     RECT  48.624 18.899 48.984 20.003 ;
     RECT  7.056 20.003 8.112 20.051 ;
     RECT  38.112 18.757 40.824 20.147 ;
     RECT  50.784 18.947 51.312 20.291 ;
     RECT  45.6 18.995 46.728 20.339 ;
     RECT  2.4 19.333 2.904 20.627 ;
     RECT  34.8 20.003 35.112 20.725 ;
     RECT  34.8 20.725 35.256 20.821 ;
     RECT  29.28 18.899 30.264 20.963 ;
     RECT  42.864 18.757 43.176 21.013 ;
     RECT  29.4 20.963 30.264 21.109 ;
     RECT  34.8 20.821 35.352 21.155 ;
     RECT  42.48 21.013 43.176 21.157 ;
     RECT  7.8 20.051 8.112 21.493 ;
     RECT  45.6 20.339 45.912 21.541 ;
     RECT  5.904 20.003 5.928 21.683 ;
     RECT  29.4 21.109 30.888 21.683 ;
     RECT  34.8 21.155 35.256 21.683 ;
     RECT  37.008 18.805 37.032 21.683 ;
     RECT  42.48 21.157 43.272 21.683 ;
     RECT  38.736 20.147 40.824 21.827 ;
     RECT  24 17.027 24.456 21.973 ;
     RECT  45.6 21.541 46.008 22.021 ;
     RECT  48.384 20.965 48.408 22.211 ;
     RECT  38.736 21.827 39.144 22.549 ;
     RECT  22.32 22.069 22.344 22.597 ;
     RECT  24 21.973 25.08 22.741 ;
     RECT  34.8 21.683 35.112 22.741 ;
     RECT  51 20.291 51.312 22.741 ;
     RECT  33.216 21.637 33.24 23.171 ;
     RECT  11.904 22.069 11.928 23.315 ;
     RECT  23.328 22.741 25.08 23.363 ;
     RECT  27.504 21.301 27.528 23.363 ;
     RECT  24 23.363 25.08 23.411 ;
     RECT  7.8 21.493 8.568 23.555 ;
     RECT  29.4 21.683 30.264 23.557 ;
     RECT  29.4 23.557 31.176 23.603 ;
     RECT  21.648 22.597 22.344 23.893 ;
     RECT  34.8 22.741 35.208 23.987 ;
     RECT  4.704 20.003 4.728 24.085 ;
     RECT  4.56 24.085 4.728 24.131 ;
     RECT  21.312 23.893 22.344 24.131 ;
     RECT  15.648 19.235 16.008 24.133 ;
     RECT  18.6 15.491 18.912 24.229 ;
     RECT  15.648 24.133 16.536 24.275 ;
     RECT  13.2 17.075 13.512 24.469 ;
     RECT  4.56 24.131 4.584 24.563 ;
     RECT  38.64 22.549 39.144 24.563 ;
     RECT  45.6 22.021 46.056 24.659 ;
     RECT  50.784 22.741 51.312 24.899 ;
     RECT  49.584 20.149 49.608 24.947 ;
     RECT  7.8 23.555 8.112 25.045 ;
     RECT  15.648 24.275 15.672 25.045 ;
     RECT  29.4 23.603 29.712 25.045 ;
     RECT  31.152 23.603 31.176 25.045 ;
     RECT  34.8 23.987 35.112 25.045 ;
     RECT  36.48 23.797 36.504 25.045 ;
     RECT  34.8 25.045 36.504 25.091 ;
     RECT  38.88 24.563 39.144 25.571 ;
     RECT  21.312 24.131 21.336 25.573 ;
     RECT  22.32 24.131 22.344 25.573 ;
     RECT  24 23.411 24.312 25.573 ;
     RECT  21.312 25.573 22.344 25.619 ;
     RECT  30.72 25.045 31.176 25.715 ;
     RECT  30.72 25.715 31.08 25.763 ;
     RECT  42.48 21.683 42.504 25.763 ;
     RECT  17.904 24.229 18.912 25.861 ;
     RECT  51 24.899 51.312 26.053 ;
     RECT  13.056 24.469 13.512 26.149 ;
     RECT  29.28 25.045 29.712 26.197 ;
     RECT  15.36 25.045 15.672 26.243 ;
     RECT  32.448 24.517 32.472 26.243 ;
     RECT  34.8 25.091 35.928 26.243 ;
     RECT  11.184 24.901 11.208 26.291 ;
     RECT  31.056 25.763 31.08 26.291 ;
     RECT  45.6 24.659 46.008 26.291 ;
     RECT  7.8 25.045 8.52 26.339 ;
     RECT  24 25.573 24.504 26.387 ;
     RECT  21.648 25.619 22.344 26.629 ;
     RECT  12.24 26.149 13.512 26.819 ;
     RECT  21.648 26.629 22.536 26.819 ;
     RECT  40.2 21.827 40.824 26.819 ;
     RECT  50.64 26.053 51.312 26.819 ;
     RECT  17.76 25.861 18.912 26.869 ;
     RECT  17.76 26.869 19.368 27.155 ;
     RECT  29.04 26.197 29.712 27.155 ;
     RECT  33.264 26.677 33.288 27.301 ;
     RECT  33.072 27.301 33.288 27.347 ;
     RECT  38.88 25.571 39 27.349 ;
     RECT  0.192 2.629 0.216 27.443 ;
     RECT  15.408 26.243 15.672 27.493 ;
     RECT  7.8 26.339 8.232 27.539 ;
     RECT  17.184 27.637 17.208 27.781 ;
     RECT  49.68 27.301 49.704 27.829 ;
     RECT  51 26.819 51.312 27.829 ;
     RECT  11.664 27.733 11.688 27.877 ;
     RECT  13.104 26.819 13.512 27.877 ;
     RECT  40.2 26.819 40.512 27.877 ;
     RECT  17.088 27.781 17.208 27.923 ;
     RECT  33.072 27.347 33.096 27.971 ;
     RECT  18.192 27.155 19.368 28.163 ;
     RECT  37.488 27.301 37.512 28.165 ;
     RECT  38.736 27.349 39 28.165 ;
     RECT  37.488 28.165 39 28.211 ;
     RECT  6 27.685 6.024 28.213 ;
     RECT  22.512 26.819 22.536 28.259 ;
     RECT  9.984 27.109 10.008 28.451 ;
     RECT  40.2 27.877 40.872 28.453 ;
     RECT  49.68 27.829 51.312 28.547 ;
     RECT  6 28.213 6.312 28.691 ;
     RECT  6.288 28.691 6.312 28.739 ;
     RECT  18.6 28.163 19.368 28.787 ;
     RECT  34.8 26.243 35.112 28.789 ;
     RECT  2.4 20.627 2.712 28.933 ;
     RECT  22.56 28.501 22.584 29.027 ;
     RECT  24 26.387 24.312 29.029 ;
     RECT  40.2 28.453 41.016 29.029 ;
     RECT  38.112 28.211 39 29.077 ;
     RECT  40.2 29.029 41.304 29.077 ;
     RECT  31.344 27.877 31.368 29.123 ;
     RECT  34.224 28.789 35.112 29.123 ;
     RECT  36.096 27.733 36.12 29.219 ;
     RECT  15.408 27.493 16.056 29.221 ;
     RECT  14.832 29.221 16.056 29.267 ;
     RECT  10.512 28.933 10.536 29.365 ;
     RECT  11.664 27.877 13.512 29.365 ;
     RECT  4.944 28.213 4.968 29.605 ;
     RECT  21.072 28.741 21.096 29.605 ;
     RECT  47.712 27.877 47.736 29.699 ;
     RECT  2.4 28.933 3.624 29.795 ;
     RECT  10.512 29.365 13.512 29.795 ;
     RECT  26.112 27.877 26.136 30.035 ;
     RECT  38.112 29.077 41.304 30.035 ;
     RECT  4.8 29.605 4.968 30.131 ;
     RECT  20.688 29.605 21.096 30.179 ;
     RECT  24 29.029 24.408 30.181 ;
     RECT  7.8 27.539 8.112 30.421 ;
     RECT  38.112 30.035 39 30.709 ;
     RECT  33.696 30.229 33.72 30.803 ;
     RECT  43.584 24.469 43.608 30.805 ;
     RECT  37.344 30.709 39 30.851 ;
     RECT  43.584 30.805 44.136 30.851 ;
     RECT  48.384 30.373 48.408 31.139 ;
     RECT  50.544 28.547 51.312 31.139 ;
     RECT  4.8 30.131 4.824 31.237 ;
     RECT  29.4 27.155 29.712 31.237 ;
     RECT  7.8 30.421 8.472 31.379 ;
     RECT  20.976 30.179 21.096 31.379 ;
     RECT  34.8 29.123 35.112 31.381 ;
     RECT  37.344 30.851 38.76 31.427 ;
     RECT  45.6 26.291 45.912 31.525 ;
     RECT  28.224 28.837 28.248 31.667 ;
     RECT  4.8 31.237 5.112 31.907 ;
     RECT  24 30.181 25.08 31.955 ;
     RECT  34.704 31.381 35.112 31.955 ;
     RECT  20.976 31.379 21 32.051 ;
     RECT  16.032 29.267 16.056 32.149 ;
     RECT  44.112 30.851 44.136 32.195 ;
     RECT  50.784 31.139 51.312 32.195 ;
     RECT  11.424 29.795 13.512 32.437 ;
     RECT  14.832 29.267 14.856 32.531 ;
     RECT  38.016 31.427 38.76 32.627 ;
     RECT  22.176 32.005 22.2 32.725 ;
     RECT  45.6 31.525 46.728 32.869 ;
     RECT  16.032 32.149 16.344 33.013 ;
     RECT  29.4 31.237 30.504 33.013 ;
     RECT  34.8 31.955 35.112 33.013 ;
     RECT  24 31.955 24.408 33.107 ;
     RECT  45.6 32.869 46.776 33.107 ;
     RECT  44.16 32.437 44.184 33.155 ;
     RECT  40.2 30.035 41.304 33.541 ;
     RECT  22.176 32.725 22.776 33.589 ;
     RECT  24 33.107 24.312 33.589 ;
     RECT  49.344 32.917 49.368 33.589 ;
     RECT  49.344 33.589 49.992 33.635 ;
     RECT  15.744 33.013 16.344 33.779 ;
     RECT  7.8 31.379 8.112 33.973 ;
     RECT  29.04 33.013 30.504 34.067 ;
     RECT  4.8 31.907 4.824 34.117 ;
     RECT  49.968 33.635 49.992 34.163 ;
     RECT  33.024 33.589 33.048 34.213 ;
     RECT  34.224 33.013 35.112 34.213 ;
     RECT  22.176 33.589 24.312 34.259 ;
     RECT  33.024 34.213 35.112 34.259 ;
     RECT  40.2 33.541 42.168 34.259 ;
     RECT  17.328 30.133 17.352 34.357 ;
     RECT  17.136 34.357 17.352 34.403 ;
     RECT  45.6 33.107 46.728 34.403 ;
     RECT  10.8 32.437 13.512 34.547 ;
     RECT  33.408 34.259 35.112 34.643 ;
     RECT  10.8 34.547 10.824 34.741 ;
     RECT  7.8 33.973 8.76 34.787 ;
     RECT  41.568 34.259 42.168 34.787 ;
     RECT  15.744 33.779 16.056 34.835 ;
     RECT  29.28 34.067 30.504 34.883 ;
     RECT  41.568 34.787 41.592 35.027 ;
     RECT  11.952 34.547 13.512 35.077 ;
     RECT  11.952 35.077 14.136 35.125 ;
     RECT  38.736 32.627 38.76 35.317 ;
     RECT  26.4 34.501 26.424 35.363 ;
     RECT  10.176 34.741 10.824 35.459 ;
     RECT  11.952 35.125 14.808 35.555 ;
     RECT  45.6 34.403 46.392 35.747 ;
     RECT  7.8 34.787 8.112 35.845 ;
     RECT  29.4 34.883 30.504 35.845 ;
     RECT  4.224 34.117 4.824 35.891 ;
     RECT  33.408 34.643 33.432 35.939 ;
     RECT  11.952 35.555 11.976 36.275 ;
     RECT  4.8 35.891 4.824 36.373 ;
     RECT  23.088 34.259 24.312 36.421 ;
     RECT  9.168 36.325 9.192 36.467 ;
     RECT  10.176 35.459 10.2 36.515 ;
     RECT  40.2 34.259 40.512 36.517 ;
     RECT  18.6 28.787 18.912 36.565 ;
     RECT  17.136 34.403 17.16 36.611 ;
     RECT  44.448 35.845 44.472 36.803 ;
     RECT  7.296 35.845 8.112 36.901 ;
     RECT  47.328 36.085 47.352 36.901 ;
     RECT  47.328 36.901 47.88 36.947 ;
     RECT  22.176 36.421 24.312 37.043 ;
     RECT  13.2 35.555 14.808 37.091 ;
     RECT  22.176 37.043 22.2 37.091 ;
     RECT  40.2 36.517 40.872 37.091 ;
     RECT  16.032 34.835 16.056 37.141 ;
     RECT  17.088 36.997 17.112 37.141 ;
     RECT  16.032 37.141 17.112 37.187 ;
     RECT  4.8 36.373 5.4 37.283 ;
     RECT  5.376 37.283 5.4 37.429 ;
     RECT  34.8 34.643 35.112 37.429 ;
     RECT  5.376 37.429 5.544 37.475 ;
     RECT  27.888 35.269 27.912 37.477 ;
     RECT  29.4 35.845 30.936 37.477 ;
     RECT  27.888 37.477 30.936 37.523 ;
     RECT  13.2 37.091 14.136 37.573 ;
     RECT  24 37.043 24.312 37.573 ;
     RECT  5.424 37.475 5.544 37.619 ;
     RECT  7.296 36.901 8.232 37.619 ;
     RECT  12.528 37.573 14.136 37.619 ;
     RECT  47.856 36.947 47.88 37.619 ;
     RECT  18.432 36.565 18.912 37.667 ;
     RECT  49.584 36.085 49.608 37.667 ;
     RECT  28.704 37.523 30.936 37.763 ;
     RECT  38.304 35.317 38.76 37.907 ;
     RECT  28.704 37.763 30.552 38.195 ;
     RECT  3.936 37.429 3.96 38.435 ;
     RECT  16.032 37.187 17.016 38.435 ;
     RECT  5.424 37.619 5.448 38.675 ;
     RECT  7.8 37.619 8.232 38.771 ;
     RECT  42.144 37.573 42.168 38.773 ;
     RECT  41.52 38.773 42.168 38.819 ;
     RECT  24 37.573 24.552 38.867 ;
     RECT  19.968 36.949 19.992 39.011 ;
     RECT  12.528 37.619 13.656 39.107 ;
     RECT  34.656 37.429 35.112 39.347 ;
     RECT  12.528 39.107 13.512 39.731 ;
     RECT  44.544 38.101 44.568 39.779 ;
     RECT  16.032 38.435 16.056 39.877 ;
     RECT  7.8 38.771 8.112 40.021 ;
     RECT  2.4 29.795 2.712 40.165 ;
     RECT  37.056 38.533 37.08 40.211 ;
     RECT  29.4 38.195 30.552 40.405 ;
     RECT  38.736 37.907 38.76 40.405 ;
     RECT  47.952 39.589 47.976 40.451 ;
     RECT  49.68 38.149 49.704 40.451 ;
     RECT  26.16 39.877 26.184 40.499 ;
     RECT  7.8 40.021 8.472 40.835 ;
     RECT  41.52 38.819 41.544 40.835 ;
     RECT  16.032 39.877 17.016 40.837 ;
     RECT  24 38.867 24.312 40.885 ;
     RECT  16.032 40.837 17.112 40.979 ;
     RECT  23.136 40.885 24.312 41.027 ;
     RECT  17.088 40.979 17.112 41.029 ;
     RECT  42.768 40.165 42.792 41.029 ;
     RECT  2.4 40.165 3.432 41.075 ;
     RECT  38.64 40.405 38.76 41.075 ;
     RECT  17.088 41.029 17.208 41.171 ;
     RECT  18.6 37.667 18.912 41.221 ;
     RECT  45.6 35.747 45.912 41.269 ;
     RECT  33.552 41.413 33.576 41.557 ;
     RECT  29.28 40.405 30.552 41.603 ;
     RECT  32.592 41.557 33.576 41.603 ;
     RECT  29.28 41.603 30.216 41.605 ;
     RECT  29.088 41.605 30.216 41.795 ;
     RECT  7.8 40.835 8.112 41.893 ;
     RECT  34.8 39.347 35.112 41.893 ;
     RECT  18.6 41.221 19.608 41.989 ;
     RECT  14.832 40.405 14.856 42.085 ;
     RECT  16.032 40.979 16.056 42.085 ;
     RECT  7.8 41.893 8.232 42.133 ;
     RECT  32.592 41.603 32.616 42.133 ;
     RECT  18.48 41.989 19.608 42.179 ;
     RECT  42.768 41.029 43.128 42.179 ;
     RECT  45.6 41.269 46.824 42.179 ;
     RECT  14.832 42.085 16.056 42.227 ;
     RECT  34.8 41.893 35.352 42.467 ;
     RECT  49.728 40.981 49.752 42.469 ;
     RECT  18.48 42.179 18.912 42.565 ;
     RECT  32.496 42.133 32.616 42.565 ;
     RECT  27.984 40.405 28.008 42.707 ;
     RECT  18.192 42.565 18.912 42.709 ;
     RECT  21.984 40.405 22.008 42.709 ;
     RECT  40.2 37.091 40.512 42.709 ;
     RECT  29.4 41.795 30.216 42.803 ;
     RECT  38.736 41.075 38.76 42.803 ;
     RECT  32.496 42.565 33.432 42.997 ;
     RECT  32.256 42.997 33.432 43.139 ;
     RECT  42.768 42.179 42.792 43.139 ;
     RECT  15.696 42.227 15.72 43.235 ;
     RECT  40.08 42.709 40.512 43.283 ;
     RECT  48.912 42.469 49.752 43.331 ;
     RECT  17.856 42.709 18.912 43.333 ;
     RECT  25.92 41.509 25.944 43.571 ;
     RECT  32.496 43.139 33.432 43.763 ;
     RECT  34.8 42.467 35.112 43.813 ;
     RECT  7.8 42.133 8.376 44.339 ;
     RECT  11.136 43.669 11.16 44.437 ;
     RECT  32.496 43.763 33.096 44.437 ;
     RECT  10.848 44.437 11.16 44.483 ;
     RECT  21.12 42.709 22.008 44.483 ;
     RECT  32.448 44.437 33.096 44.773 ;
     RECT  32.256 44.773 33.096 44.869 ;
     RECT  34.8 43.813 35.352 44.869 ;
     RECT  17.616 43.333 18.912 44.915 ;
     RECT  10.848 44.483 10.872 45.059 ;
     RECT  27.936 44.437 27.96 45.155 ;
     RECT  24 41.027 24.312 45.157 ;
     RECT  4.656 43.669 4.68 45.203 ;
     RECT  21.984 44.483 22.008 45.203 ;
     RECT  32.256 44.869 35.352 45.299 ;
     RECT  32.256 45.299 33.096 45.491 ;
     RECT  34.8 45.299 35.352 45.491 ;
     RECT  29.4 42.803 29.712 45.541 ;
     RECT  32.496 45.491 33.096 45.587 ;
     RECT  45.6 42.179 45.912 46.069 ;
     RECT  34.8 45.491 35.208 46.259 ;
     RECT  40.2 43.283 40.512 46.549 ;
     RECT  7.8 44.339 8.232 46.693 ;
     RECT  32.976 45.587 33.096 46.787 ;
     RECT  39.936 46.549 40.512 46.787 ;
     RECT  40.08 46.787 40.512 46.883 ;
     RECT  33.072 46.787 33.096 47.363 ;
     RECT  34.8 46.259 35.112 47.365 ;
     RECT  5.232 46.453 5.256 47.459 ;
     RECT  45.6 46.069 46.008 47.749 ;
     RECT  47.04 47.173 47.064 47.749 ;
     RECT  45.6 47.749 47.064 47.843 ;
     RECT  17.856 44.915 18.912 47.845 ;
     RECT  49.728 43.331 49.752 47.891 ;
     RECT  29.4 45.541 30.264 47.939 ;
     RECT  38.208 43.237 38.232 47.939 ;
     RECT  43.92 47.269 43.944 48.085 ;
     RECT  43.92 48.085 44.184 48.131 ;
     RECT  23.76 45.157 24.312 48.421 ;
     RECT  40.2 46.883 40.512 48.421 ;
     RECT  15.264 47.173 15.288 48.467 ;
     RECT  33.648 47.749 33.672 48.853 ;
     RECT  34.8 47.365 35.304 48.853 ;
     RECT  33.648 48.853 35.304 48.949 ;
     RECT  32.16 48.421 32.184 48.995 ;
     RECT  22.08 46.357 22.104 49.091 ;
     RECT  17.856 47.845 19.608 49.187 ;
     RECT  9.552 47.845 9.576 49.379 ;
     RECT  18.6 49.187 19.608 49.427 ;
     RECT  44.16 48.131 44.184 49.475 ;
     RECT  45.6 47.843 46.248 49.475 ;
     RECT  33.6 48.949 35.352 49.571 ;
     RECT  40.2 48.421 40.968 49.763 ;
     RECT  23.52 48.421 24.312 50.051 ;
     RECT  25.776 48.421 25.8 50.051 ;
     RECT  7.8 46.693 8.52 50.101 ;
     RECT  12 47.845 12.024 50.195 ;
     RECT  32.496 49.477 32.52 50.579 ;
     RECT  33.648 49.571 35.352 50.579 ;
     RECT  45.6 49.475 46.008 50.579 ;
     RECT  7.8 50.101 9.24 50.627 ;
     RECT  7.8 50.627 8.112 50.677 ;
     RECT  18.6 49.427 19.464 50.771 ;
     RECT  47.808 50.101 47.832 50.771 ;
     RECT  36.48 50.149 36.504 51.107 ;
     RECT  33.648 50.579 35.208 51.155 ;
     RECT  7.392 50.677 8.112 51.299 ;
     RECT  9.216 50.627 9.24 51.395 ;
     RECT  23.712 50.051 24.312 51.395 ;
     RECT  40.2 49.763 40.92 51.395 ;
     RECT  2.4 41.075 2.712 51.849 ;
     RECT  7.8 51.299 8.112 51.849 ;
     RECT  13.2 39.731 13.512 51.849 ;
     RECT  18.6 50.771 18.912 51.849 ;
     RECT  24 51.395 24.312 51.849 ;
     RECT  29.4 47.939 29.712 51.849 ;
     RECT  33.648 51.155 35.112 51.849 ;
     RECT  40.2 51.395 40.512 51.849 ;
     RECT  45.6 50.579 45.912 51.849 ;
     RECT  51 32.195 51.312 51.849 ;
     RECT  2.4 51.849 2.52 51.863 ;
     RECT  7.8 51.849 7.92 51.863 ;
     RECT  13.2 51.849 13.32 51.863 ;
     RECT  18.6 51.849 18.72 51.863 ;
     RECT  24 51.849 24.12 51.863 ;
     RECT  29.4 51.849 29.52 51.863 ;
     RECT  33.648 51.849 34.92 51.863 ;
     RECT  40.2 51.849 40.32 51.863 ;
     RECT  45.6 51.849 45.72 51.863 ;
     RECT  51 51.849 51.12 51.863 ;
     RECT  33.648 51.863 34.344 53.075 ;
     RECT  34.32 53.075 34.344 53.939 ;
     RECT  42.192 0.611 42.384 0.659 ;
     RECT  42.192 0.659 42.48 1.861 ;
     RECT  40.632 2.245 42.096 2.533 ;
     RECT  13.656 2.293 15.024 2.581 ;
     RECT  40.632 2.533 42.048 2.725 ;
     RECT  33.672 2.581 34.8 4.595 ;
     RECT  40.632 2.725 41.808 2.915 ;
     RECT  40.512 2.915 41.808 4.405 ;
     RECT  14.424 3.011 15.048 4.357 ;
     RECT  10.44 3.109 11.952 3.301 ;
     RECT  11.976 3.109 13.2 5.171 ;
     RECT  10.824 3.301 11.952 5.171 ;
     RECT  17.448 4.213 18.6 6.851 ;
     RECT  18.912 4.261 20.064 6.899 ;
     RECT  22.536 4.453 23.712 4.837 ;
     RECT  13.512 4.643 14.544 6.613 ;
     RECT  6.744 4.645 7.8 10.309 ;
     RECT  12.672 5.171 13.2 5.605 ;
     RECT  5.16 5.365 6.624 5.701 ;
     RECT  35.112 5.461 36.144 9.013 ;
     RECT  5.64 5.701 6.624 8.579 ;
     RECT  26.52 6.181 27.84 7.187 ;
     RECT  14.28 6.659 14.568 6.805 ;
     RECT  36.312 6.803 36.648 8.197 ;
     RECT  40.512 6.803 41.808 7.861 ;
     RECT  14.28 6.805 15.696 7.427 ;
     RECT  40.512 7.861 41.52 8.675 ;
     RECT  4.584 7.909 5.616 8.579 ;
     RECT  30.504 8.293 31.872 8.579 ;
     RECT  4.584 8.579 6.624 8.867 ;
     RECT  9.96 8.627 10.536 8.869 ;
     RECT  40.512 8.675 41.76 10.547 ;
     RECT  4.848 8.867 6.624 9.349 ;
     RECT  9.96 8.869 11.232 10.067 ;
     RECT  11.256 8.869 12.336 9.299 ;
     RECT  38.76 9.061 40.2 9.395 ;
     RECT  11.256 9.299 12.528 10.067 ;
     RECT  4.848 9.349 6.336 9.925 ;
     RECT  38.88 9.395 40.2 10.597 ;
     RECT  23.04 9.731 23.136 10.981 ;
     RECT  35.112 9.779 36.24 11.365 ;
     RECT  4.848 9.925 5.232 10.117 ;
     RECT  5.256 9.925 6.336 12.469 ;
     RECT  28.656 10.307 29.4 10.789 ;
     RECT  40.512 10.547 41.808 12.611 ;
     RECT  38.904 10.597 40.2 12.421 ;
     RECT  26.712 10.789 28.176 11.219 ;
     RECT  28.2 10.789 29.4 11.411 ;
     RECT  30.264 10.837 31.488 10.883 ;
     RECT  31.512 10.837 32.976 11.459 ;
     RECT  24.312 10.883 24.6 11.941 ;
     RECT  26.976 11.219 28.176 11.221 ;
     RECT  27 11.221 28.176 11.411 ;
     RECT  37.032 11.269 38.064 11.365 ;
     RECT  27 11.411 29.4 11.989 ;
     RECT  27.864 11.989 29.4 12.517 ;
     RECT  39.048 12.421 40.2 12.517 ;
     RECT  27.912 12.517 29.4 13.187 ;
     RECT  39.144 12.517 40.2 16.405 ;
     RECT  22.776 13.139 24 13.571 ;
     RECT  35.112 13.187 36.24 14.435 ;
     RECT  22.488 13.571 24 14.675 ;
     RECT  24.456 13.667 24.936 14.725 ;
     RECT  22.8 14.675 24 14.725 ;
     RECT  42.192 14.723 42.816 14.725 ;
     RECT  40.824 14.725 42.816 14.773 ;
     RECT  41.592 14.773 42.816 15.395 ;
     RECT  22.824 14.915 24 18.419 ;
     RECT  44.184 16.595 45.168 17.699 ;
     RECT  39.144 16.883 40.2 18.517 ;
     RECT  35.64 17.077 36.816 17.123 ;
     RECT  43.176 17.219 44.16 17.699 ;
     RECT  42.864 17.507 43.056 18.757 ;
     RECT  48.984 17.699 50.112 18.851 ;
     RECT  13.512 18.181 14.688 19.235 ;
     RECT  16.008 18.181 17.184 19.523 ;
     RECT  17.208 18.181 18.6 19.523 ;
     RECT  37.032 18.805 38.112 20.147 ;
     RECT  48.984 18.851 50.16 18.947 ;
     RECT  47.304 18.899 48.624 18.947 ;
     RECT  48.984 18.947 50.784 20.003 ;
     RECT  4.728 20.003 5.904 21.683 ;
     RECT  5.928 20.003 7.056 20.051 ;
     RECT  48.624 20.003 50.784 20.149 ;
     RECT  48.624 20.149 49.584 20.965 ;
     RECT  49.608 20.149 50.784 20.291 ;
     RECT  49.608 20.291 51 22.741 ;
     RECT  45.912 20.339 46.008 21.541 ;
     RECT  48.408 20.965 49.584 22.211 ;
     RECT  35.112 21.683 35.208 22.741 ;
     RECT  39.144 21.827 40.2 25.571 ;
     RECT  11.928 22.069 13.2 23.315 ;
     RECT  22.344 22.741 23.328 23.363 ;
     RECT  49.608 22.741 50.784 24.899 ;
     RECT  13.056 23.315 13.2 24.469 ;
     RECT  8.112 23.555 8.52 25.045 ;
     RECT  29.712 23.603 31.152 25.045 ;
     RECT  35.208 23.797 36.48 23.987 ;
     RECT  35.112 23.987 36.48 25.045 ;
     RECT  21.336 24.131 22.32 25.573 ;
     RECT  16.536 24.229 17.904 24.275 ;
     RECT  42.504 24.469 43.584 25.763 ;
     RECT  31.176 24.517 32.448 25.715 ;
     RECT  49.608 24.899 51 24.947 ;
     RECT  50.64 24.947 51 26.053 ;
     RECT  29.712 25.045 30.72 25.763 ;
     RECT  39 25.571 40.2 29.077 ;
     RECT  31.08 25.715 32.448 26.243 ;
     RECT  29.712 25.763 31.056 26.291 ;
     RECT  11.208 26.149 12.24 26.291 ;
     RECT  35.112 26.243 35.928 27.733 ;
     RECT  11.664 26.291 12.24 26.819 ;
     RECT  22.536 26.629 24 28.259 ;
     RECT  33.288 26.677 34.8 27.347 ;
     RECT  11.664 26.819 13.104 27.733 ;
     RECT  40.512 26.819 40.824 27.877 ;
     RECT  50.64 26.819 51 27.301 ;
     RECT  17.76 27.155 18.192 27.637 ;
     RECT  37.512 27.301 38.88 27.349 ;
     RECT  49.704 27.301 51 27.829 ;
     RECT  33.096 27.347 34.8 27.971 ;
     RECT  37.512 27.349 38.736 28.165 ;
     RECT  16.056 27.637 17.184 27.781 ;
     RECT  17.208 27.637 18.192 27.923 ;
     RECT  11.688 27.733 13.104 27.877 ;
     RECT  35.112 27.733 36.096 29.219 ;
     RECT  36.12 27.733 37.488 28.211 ;
     RECT  16.056 27.781 17.088 27.923 ;
     RECT  34.224 27.971 34.8 28.789 ;
     RECT  4.968 28.213 6 28.691 ;
     RECT  6.312 28.213 7.8 28.739 ;
     RECT  22.512 28.259 24 28.501 ;
     RECT  22.512 28.501 22.56 28.741 ;
     RECT  22.584 28.501 24 29.027 ;
     RECT  4.968 28.691 6.288 28.739 ;
     RECT  21.096 28.741 22.56 29.027 ;
     RECT  28.248 28.837 29.4 31.667 ;
     RECT  3.624 28.933 4.944 29.605 ;
     RECT  10.536 28.933 11.664 29.365 ;
     RECT  34.224 29.123 34.8 30.229 ;
     RECT  13.512 29.221 14.832 32.531 ;
     RECT  14.856 29.267 16.032 32.531 ;
     RECT  3.624 29.605 4.8 29.795 ;
     RECT  39 30.035 40.2 30.851 ;
     RECT  4.824 30.131 4.968 31.237 ;
     RECT  16.056 30.133 17.328 32.149 ;
     RECT  17.352 30.133 18.6 34.403 ;
     RECT  33.72 30.229 34.8 30.803 ;
     RECT  34.704 30.803 34.8 31.381 ;
     RECT  44.136 30.805 45.6 32.195 ;
     RECT  38.76 30.851 40.2 42.709 ;
     RECT  21 31.379 21.096 32.005 ;
     RECT  29.04 31.667 29.4 33.013 ;
     RECT  34.704 31.955 34.8 33.013 ;
     RECT  21 32.005 22.176 32.051 ;
     RECT  16.344 32.149 17.328 33.779 ;
     RECT  44.16 32.195 45.6 32.437 ;
     RECT  50.784 32.195 51 32.917 ;
     RECT  44.184 32.437 45.6 33.155 ;
     RECT  15.744 32.531 16.032 33.013 ;
     RECT  22.776 32.725 24 33.589 ;
     RECT  49.368 32.917 51 33.589 ;
     RECT  33.048 33.589 34.224 34.213 ;
     RECT  49.992 33.589 51 34.163 ;
     RECT  16.056 33.779 17.328 34.357 ;
     RECT  29.04 34.067 29.28 34.883 ;
     RECT  2.712 34.117 4.224 35.891 ;
     RECT  40.512 34.259 41.568 35.027 ;
     RECT  16.056 34.357 17.136 36.611 ;
     RECT  17.16 34.403 18.6 36.565 ;
     RECT  10.824 34.547 11.952 35.459 ;
     RECT  33.432 34.643 34.8 35.939 ;
     RECT  8.76 34.741 10.176 34.787 ;
     RECT  15.744 34.835 16.032 35.125 ;
     RECT  29.04 34.883 29.4 35.269 ;
     RECT  40.512 35.027 40.872 36.517 ;
     RECT  14.808 35.125 16.032 37.091 ;
     RECT  26.424 35.269 27.888 35.363 ;
     RECT  27.912 35.269 29.4 37.477 ;
     RECT  11.976 35.555 13.2 36.275 ;
     RECT  45.912 35.747 46.392 36.085 ;
     RECT  44.472 35.845 45.6 36.803 ;
     RECT  34.656 35.939 34.8 37.429 ;
     RECT  45.912 36.085 47.328 36.947 ;
     RECT  49.608 36.085 51 37.667 ;
     RECT  12.528 36.275 13.2 37.573 ;
     RECT  8.112 36.325 9.168 36.467 ;
     RECT  9.192 36.325 10.176 36.467 ;
     RECT  8.112 36.467 8.232 36.901 ;
     RECT  17.16 36.565 18.432 36.611 ;
     RECT  16.056 36.611 18.432 36.997 ;
     RECT  44.544 36.803 45.6 38.101 ;
     RECT  18.912 36.949 19.968 39.011 ;
     RECT  16.056 36.997 17.088 37.141 ;
     RECT  17.112 36.997 18.432 37.187 ;
     RECT  17.016 37.187 18.432 37.667 ;
     RECT  4.8 37.283 5.376 37.429 ;
     RECT  2.712 37.429 3.936 38.435 ;
     RECT  3.96 37.429 5.376 37.475 ;
     RECT  3.96 37.475 5.424 38.435 ;
     RECT  49.68 37.667 51 38.149 ;
     RECT  44.568 38.101 45.6 39.779 ;
     RECT  49.704 38.149 51 40.451 ;
     RECT  16.056 38.435 17.016 39.877 ;
     RECT  8.112 38.771 8.232 40.021 ;
     RECT  40.512 38.773 41.52 40.835 ;
     RECT  41.544 38.819 42.168 40.165 ;
     RECT  13.512 39.107 13.656 40.405 ;
     RECT  41.544 40.165 42.768 40.835 ;
     RECT  13.512 40.405 14.832 42.227 ;
     RECT  14.856 40.405 16.032 42.085 ;
     RECT  28.008 40.405 29.28 41.605 ;
     RECT  49.728 40.451 51 40.981 ;
     RECT  8.112 40.835 8.376 41.893 ;
     RECT  17.112 40.837 18.6 41.029 ;
     RECT  22.008 40.885 23.136 41.027 ;
     RECT  16.056 40.979 17.088 41.171 ;
     RECT  49.752 40.981 51 47.891 ;
     RECT  17.208 41.029 18.6 41.171 ;
     RECT  18.192 41.171 18.6 41.989 ;
     RECT  33.576 41.413 34.8 41.603 ;
     RECT  32.616 41.603 34.8 42.565 ;
     RECT  28.008 41.605 29.088 41.795 ;
     RECT  28.008 41.795 29.4 42.707 ;
     RECT  8.232 41.893 8.376 42.133 ;
     RECT  18.192 41.989 18.48 42.565 ;
     RECT  35.112 42.467 35.352 43.813 ;
     RECT  33.432 42.565 34.8 43.763 ;
     RECT  38.76 42.709 40.08 42.803 ;
     RECT  32.448 43.139 32.496 44.437 ;
     RECT  33.096 43.763 34.8 44.869 ;
     RECT  27.96 44.437 29.4 45.155 ;
     RECT  35.112 46.259 35.208 47.365 ;
     RECT  46.008 47.173 47.04 47.749 ;
     RECT  33.072 47.363 33.096 47.749 ;
     RECT  33.072 47.749 33.648 48.421 ;
     RECT  33.672 47.749 34.8 48.853 ;
     RECT  8.52 47.845 9.552 49.379 ;
     RECT  12.024 47.845 13.2 50.195 ;
     RECT  44.184 48.085 45.6 49.475 ;
     RECT  22.104 48.421 23.52 49.091 ;
     RECT  24.312 48.421 25.776 50.051 ;
     RECT  32.184 48.421 33.648 48.949 ;
     RECT  32.184 48.949 33.6 48.995 ;
     RECT  32.496 48.995 33.6 49.477 ;
     RECT  8.52 49.379 9.24 50.101 ;
     RECT  32.52 49.477 33.6 49.571 ;
     RECT  32.52 49.571 33.648 50.579 ;
     RECT  35.352 50.149 36.48 50.579 ;
     RECT  35.208 50.579 36.48 51.107 ;
     RECT  8.112 50.627 9.216 51.395 ;
  END
END ot_hgi_xp_rdc
END LIBRARY
